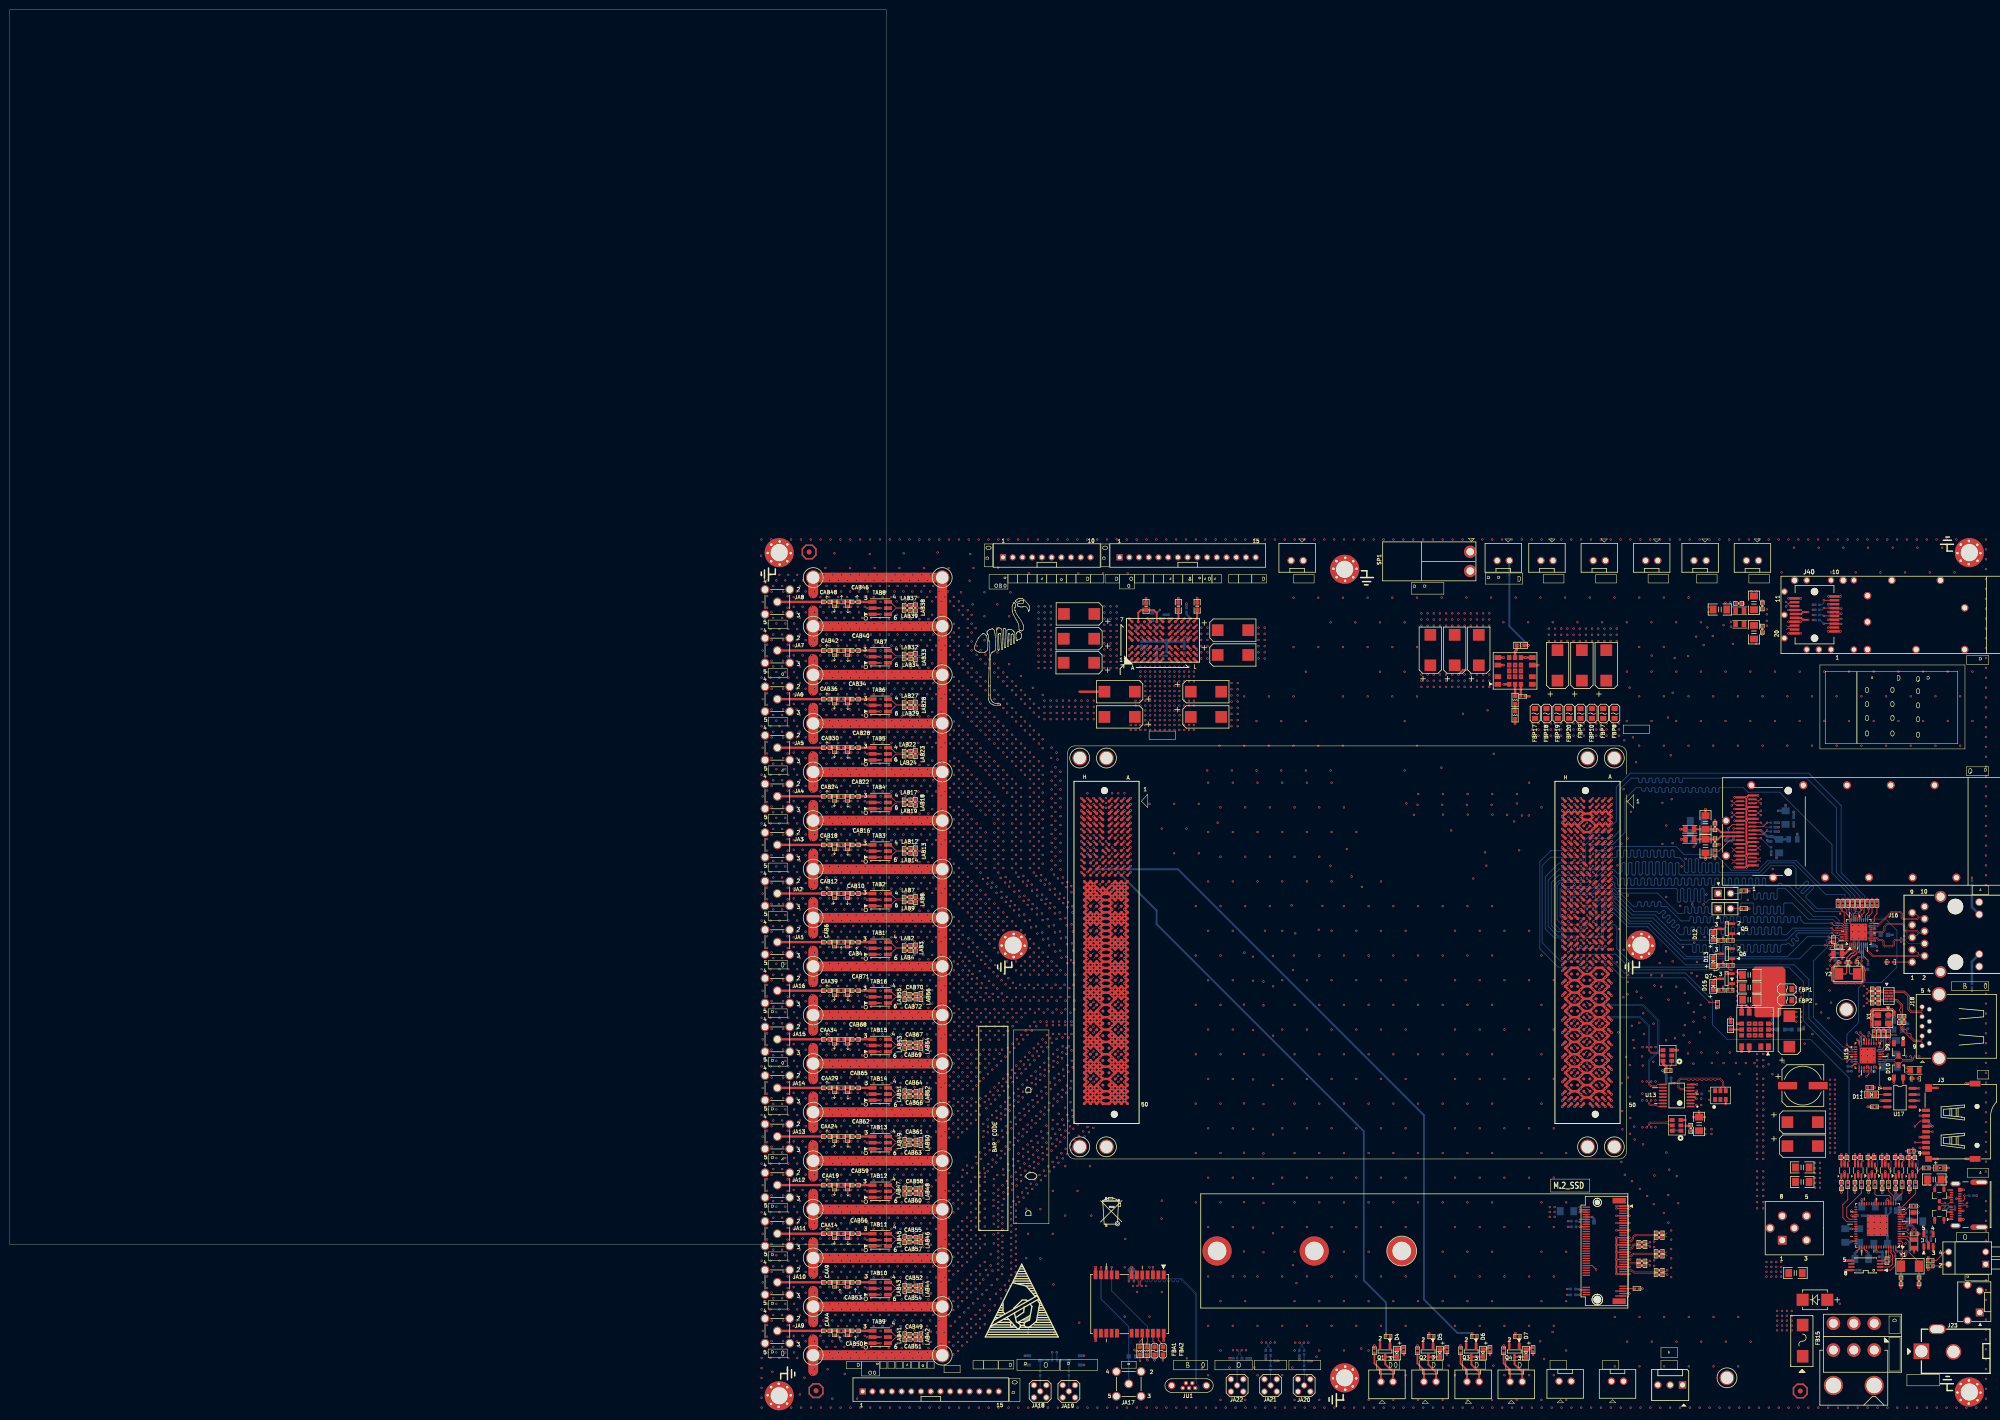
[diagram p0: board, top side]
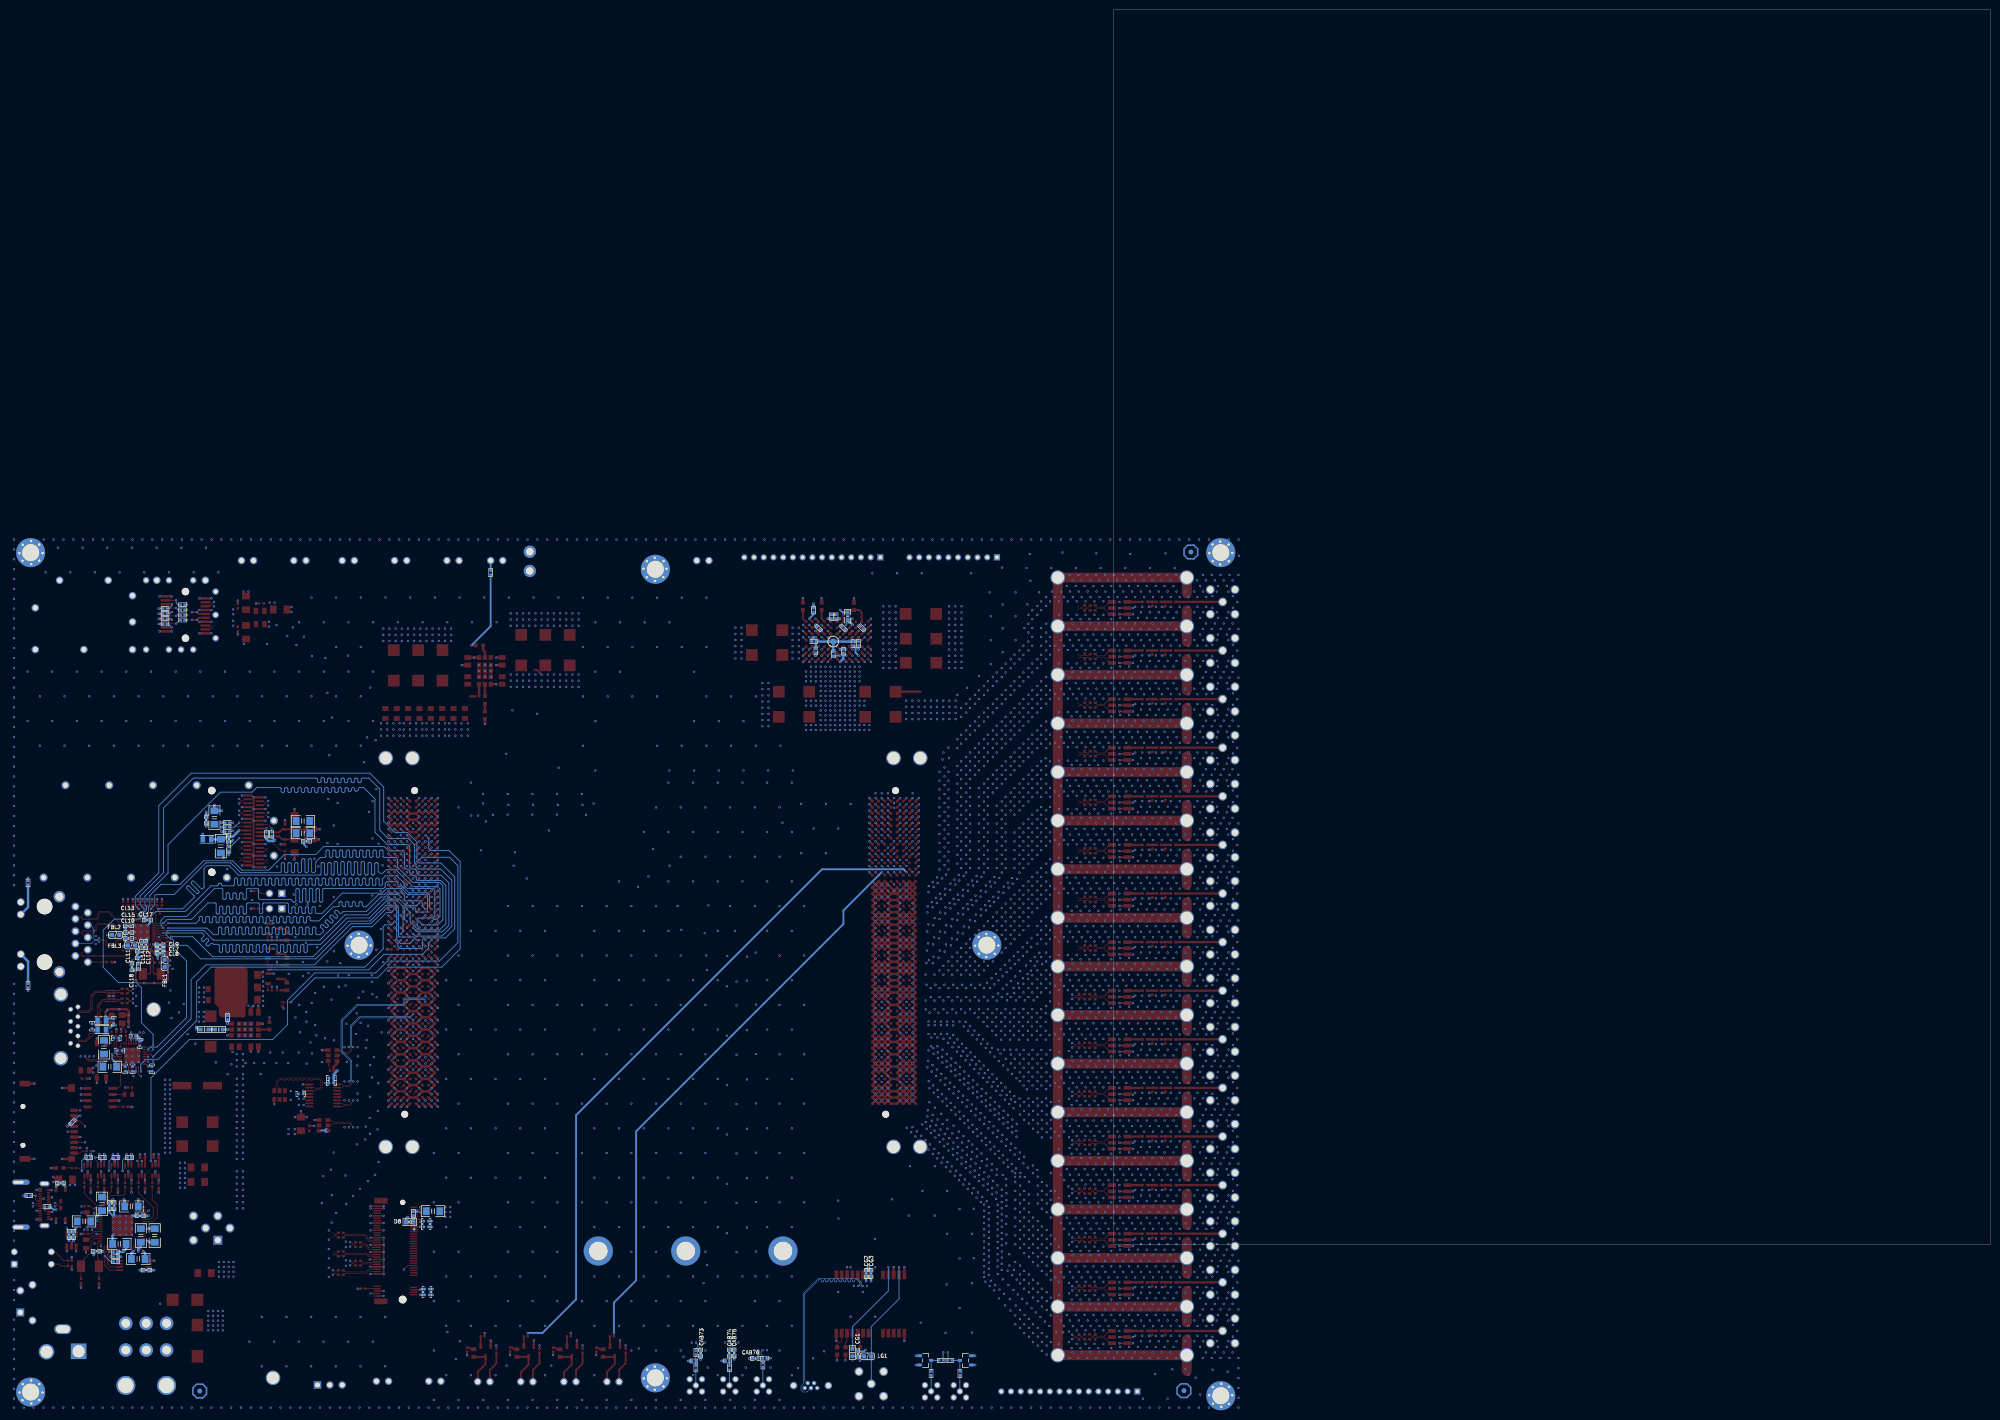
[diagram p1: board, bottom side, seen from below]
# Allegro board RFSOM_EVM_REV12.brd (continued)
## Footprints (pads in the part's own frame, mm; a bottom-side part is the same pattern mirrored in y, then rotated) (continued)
QFN40
  round 0.5 smd: (-3.8,3.8) (3.8,-3.8)
  oval 0.203x0.762 smd: 1(-1.8,-2.46) 2(-1.4,-2.46) 3(-1,-2.46) 4(-0.6,-2.46) 5(-0.2,-2.46) 6(0.2,-2.46) 7(0.6,-2.46) 8(1,-2.46) 9(1.4,-2.46) 10(1.8,-2.46) 21(1.8,2.46) 22(1.4,2.46) 23(1,2.46) 24(0.6,2.46) 25(0.2,2.46) 26(-0.2,2.46) 27(-0.6,2.46) 28(-1,2.46) 29(-1.4,2.46) 30(-1.8,2.46)
  oval 0.762x0.203 smd: 11(2.46,-1.8) 12(2.46,-1.4) 13(2.46,-1) 14(2.46,-0.6) 15(2.46,-0.2) 16(2.46,0.2) 17(2.46,0.6) 18(2.46,1) 19(2.46,1.4) 20(2.46,1.8) 31(-2.46,1.8) 32(-2.46,1.4) 33(-2.46,1) 34(-2.46,0.6) 35(-2.46,0.2) 36(-2.46,-0.2) 37(-2.46,-0.6) 38(-2.46,-1) 39(-2.46,-1.4) 40(-2.46,-1.8)
  rect 3.5x3.5 smd: 41(0,0)
QFN64
  oval 0.254x0.711 smd: 1(-3.749,-4.45) 2(-3.251,-4.45) 3(-2.751,-4.45) 4(-2.25,-4.45) 5(-1.75,-4.45) 6(-1.25,-4.45) 7(-0.749,-4.45) 8(-0.249,-4.45) 9(0.249,-4.45) 10(0.749,-4.45) 11(1.25,-4.45) 12(1.75,-4.45) 13(2.25,-4.45) 14(2.751,-4.45) 15(3.251,-4.45) 16(3.749,-4.45) 33(3.749,4.45) 34(3.251,4.45) 35(2.751,4.45) 36(2.25,4.45) 37(1.75,4.45) 38(1.25,4.45) 39(0.749,4.45) 40(0.249,4.45) 41(-0.249,4.45) 42(-0.749,4.45) 43(-1.25,4.45) 44(-1.75,4.45) 45(-2.25,4.45) 46(-2.751,4.45) 47(-3.251,4.45) 48(-3.749,4.45)
  oval 0.711x0.254 smd: 17(4.45,-3.749) 18(4.45,-3.251) 19(4.45,-2.751) 20(4.45,-2.25) 21(4.45,-1.75) 22(4.45,-1.25) 23(4.45,-0.749) 24(4.45,-0.249) 25(4.45,0.249) 26(4.45,0.749) 27(4.45,1.25) 28(4.45,1.75) 29(4.45,2.25) 30(4.45,2.751) 31(4.45,3.251) 32(4.45,3.749) 49(-4.45,3.749) 50(-4.45,3.251) 51(-4.45,2.751) 52(-4.45,2.25) 53(-4.45,1.75) 54(-4.45,1.25) 55(-4.45,0.749) 56(-4.45,0.249) 57(-4.45,-0.249) 58(-4.45,-0.749) 59(-4.45,-1.25) 60(-4.45,-1.75) 61(-4.45,-2.25) 62(-4.45,-2.751) 63(-4.45,-3.251) 64(-4.45,-3.749)
  rect 4.42x4.42 smd: 65(0,0)
QSFP28_CON
  round 1.549 hole 1.549 unplated: (-8.4,0) (8.4,0)
  oval 0.399x1.801 smd: 1(-7,7.37) 2(-6.2,7.37) 3(-5.4,7.37) 4(-4.6,7.37) 5(-3.8,7.37) 6(-3,7.37) 7(-2.2,7.37) 8(-1.4,7.37) 9(-0.6,7.37) 10(0.2,7.37) 11(1,7.37) 12(1.8,7.37) 13(2.6,7.37) 14(3.4,7.37) 15(4.2,7.37) 16(5,7.37) 17(5.8,7.37) 18(6.6,7.37) 19(7.4,7.37) 20(7,9.88) 21(6.2,9.88) 22(5.4,9.88) 23(4.6,9.88) 24(3.8,9.88) 25(3,9.88) 26(2.2,9.88) 27(1.4,9.88) 28(0.6,9.88) 29(-0.2,9.88) 30(-1,9.88) 31(-1.8,9.88) 32(-2.6,9.88) 33(-3.4,9.88) 34(-4.2,9.88) 35(-5,9.88) 36(-5.8,9.88) 37(-6.6,9.88) 38(-7.4,9.88)
R0402
  rect 0.5x0.5 smd: 1(-0.399,0) 2(0.399,0)
R0603
  rect 0.762x0.813 smd: 1(-0.762,0) 2(0.762,0)
SC70_6
  rect 1.016x0.406 smd: 1(-1.1,0.658) 2(-1.1,0) 3(-1.1,-0.658) 4(1.1,-0.658) 5(1.1,0) 6(1.1,0.658)
SFP_MODULE
  round 1.549 hole 1.524 unplated: (4.1,1.402) (4.1,-8.199)
  rect 2.007x0.508 smd: 1(0,0) 2(0,-0.8) 3(0,-1.6) 4(0,-2.4) 5(0,-3.2) 6(0,-4) 7(0,-4.8) 8(0,-5.6) 9(0,-6.4) 10(0,-7.2) 11(8.202,-6.799) 12(8.202,-5.999) 13(8.202,-5.199) 14(8.202,-4.399) 15(8.202,-3.599) 16(8.202,-2.799) 17(8.202,-1.999) 18(8.202,-1.199) 19(8.202,-0.399) 20(8.202,0.401)
  round 1.346 hole 0.838: 21(3.2,3.731) A1(-4,3.731) A2(0.701,3.731) A3(5.7,3.731) A4(10.3,1.402) A5(10.3,-3.399) A6(10.3,-8.199) A8(5.7,-10.518) A9(0.701,-10.518) A10(-4,-10.518)
  round 1.549 hole 1.041: 22(-6.8,3.731) 23(-16.8,3.731) 24(-26.8,3.731) 25(-26.8,-4.849) 26(-21.798,-10.518) 27(-11.798,-10.518) 28(-1.798,-10.518) 29(8.202,-10.518) 30(-6.8,-7.348) 31(-6.8,-1.948)
SIP2
  rect 1.524x1.524 hole 1.016: 1(-0.004,-0.008)
  round 1.524 hole 1.016: 2(2.536,-0.008)
SIP2_HV
  round 2.54 hole 1.524: 1(0.013,0.01) 2(3.973,0.01)
SIP10_2-0MM_S
  rect 1.27x1.27 hole 0.762: 1(-9,0)
  round 1.27 hole 0.762: 2(-7,0) 3(-5,0) 4(-3,0) 5(-1,0) 6(1,0) 7(3,0) 8(5,0) 9(7,0) 10(9,0)
SIP15_2-0MM_S
  rect 1.27x1.27 hole 0.762: 1(-14,0)
  round 1.27 hole 0.762: 2(-11.999,0) 3(-10,0) 4(-8.001,0) 5(-5.999,0) 6(-4,0) 7(-1.999,0) 8(0,0) 9(1.999,0) 10(4,0) 11(5.999,0) 12(8.001,0) 13(10,0) 14(11.999,0) 15(14,0)
SMB
  rect 2.489x2.489 smd: 1(-2.54,0) 2(2.54,0)
SMB_RF
  round 1.803 hole 1.321: 1(0,0) 2(-2.54,2.54) 3(2.54,2.54) 4(-2.54,-2.54) 5(2.54,-2.54)
SO-G3
  rect 0.838x1.245 smd: 1(0.95,1.275) 2(-0.95,1.275) 3(0,-1.275)
SO_8
  rect 1.803x0.61 smd: 1(-2.593,1.905)
  oval 1.803x0.61 smd: 2(-2.593,0.635) 3(-2.593,-0.635) 4(-2.593,-1.905) 5(2.593,-1.905) 6(2.593,-0.635) 7(2.593,0.635) 8(2.593,1.905)
SOT23
  rect 0.899x0.599 smd: 1(-1.151,0.95) 2(-1.151,-0.95) 3(1.151,0)
SOT_23
  rect 1.194x0.61 smd: 1(0,1.025)
  rect 1.194x0.508 smd: 2(0,-1.025) 3(2.225,0.05)
SOT_25
  rect 0.635x1.27 smd: 1(-0.95,-1.25) 2(0,-1.25) 3(0.95,-1.25) 4(0.95,1.25) 5(-0.95,1.25)
SWP1
  round 1.626 hole 1.118: (-1.66,2.523) (5.669,2.523) 2(4.483,0.01)
  rect 1.626x1.626 hole 1.118: 1(-0.01,0.01)
TCM1-63AX_
  rect 0.762x1.651 smd: 1(-1.27,1.59) 2(0,1.59) 3(1.27,1.59) 4(1.27,-1.59) 5(0,-1.59) 6(-1.27,-1.59)
TF01A
  round 1.016 hole 1.016 unplated: (-7.201,-10.5) (0.8,-10.5)
  rect 0.711x1.6 smd: 1(0,0) 2(-1.1,0) 3(-2.2,0) 4(-3.299,0) 5(-4.399,0) 6(-5.499,0) 7(-6.599,0) 8(-7.701,0) 9(-8.801,0)
  rect 1.194x1.397 smd: 10(-10,-0.5)
  rect 1.6x1.397 smd: 11(4.6,-0.5)
  rect 1.194x2.21 smd: 12(-10,-10.099) 13(5.499,-10.099)
TSSOP8
  rect 0.356x1.321 smd: 1(-0.975,-2.949) 2(-0.325,-2.949) 3(0.325,-2.949) 4(0.975,-2.949) 5(0.975,2.949) 6(0.325,2.949) 7(-0.325,2.949) 8(-0.975,2.949)
TSSOP16
  oval 1.702x0.356 smd: 1(-2.85,2.275) 2(-2.85,1.625) 3(-2.85,0.975) 4(-2.85,0.325) 5(-2.85,-0.325) 6(-2.85,-0.975) 7(-2.85,-1.625) 8(-2.85,-2.275) 9(2.85,-2.275) 10(2.85,-1.625) 11(2.85,-0.975) 12(2.85,-0.325) 13(2.85,0.325) 14(2.85,0.975) 15(2.85,1.625) 16(2.85,2.275)
TVS_0524J
  rect 0.305x0.686 smd: 1(-1.118,-0.442) 2(-0.61,-0.442) 3(0.61,-0.442) 4(1.118,-0.442) 5(1.118,0.442) 6(0.61,0.442) 7(-0.61,0.442) 8(-1.118,0.442)
  rect 0.508x0.889 smd: 9(0,0.432) 10(0,-0.432)
U95-T1N1-101A
  round 1.651 hole 1.041: 1(1.1,-3.1) 2(-3.4,-12.79) 3(-10.6,-12.79) 4(-17.9,-7.6) 5(-17.9,3.1) 6(-17.9,12.1) 7(-17.9,21.1) 8(-17.9,30.1) 9(1.1,34.6) 10(1.1,25.6) 11(1.1,16.6) 12(1.1,7.6)
unnamed#2
  round 1.016 smd: 1(0,0)
USB3-A
  round 1.016 hole 0.711: 1(-3.5,2) 2(-1,2) 3(1,2) 4(3.5,2) 5(4,3.5) 6(2,3.5) 7(0,3.5) 8(-2,3.5) 9(-4,3.5)
  round 2.997 hole 2.311: 10(-6.57,0) 11(6.57,0)
USB-MICRO-VER
  round 0.914 hole 0.432: 1(-1.3,0.5) 2(-0.665,-0.5) 3(0,0.5) 4(0.635,-0.5) 5(1.3,0.5)
  round 1.524 hole 1.016: 6(-3.575,0) 7(3.575,0)
XTALSMD_3225
  oval 1.397x1.194 smd: 1(-1.1,-0.85)
  rect 1.397x1.194 smd: 2(1.1,-0.85) 3(1.1,0.85) 4(-1.1,0.85)
XTALSMD_3225_DP
  rect 0.813x1.016 smd: 1(-1.1,-0.9) 2(0,-0.9) 3(1.1,-0.9) 4(1.1,0.9) 5(0,0.9) 6(-1.1,0.9)

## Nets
+1.8V: C2.1 C4.1 C6.1 C8.1 FBP1.1 FBP2.1 R7.1 R8.1 R9.1 R10.1 R64.1 R99.2 U3.6(VCCB) U4.6(VCCB) U5.6(VCCB) U6.6(VCCB) U15.28 U15.30
+3.3V: C13.1 C18.1 C31.1 C32.1 C39.1 C40.1 C41.1 C42.1 C43.1 C44.1 C78.1 C79.1 C80.1 C81.1 C84.1 C85.1 C86.1 C98.1 C101.1 C102.1 C103.1 C104.1 C288.1 C289.1 CG2.1 CG3.1 D14.2 D16.2 FB3.1 FB4.1 FB5.1 FB6.1 FB7.1 FBA1.2 FBA2.2 FBL2.1 FBL3.1 FBP7.1 FBP8.1 J3.4 J11.10 J17.2 J17.4 J17.12 J17.14 J17.16 J17.18 J17.70 J17.72 J17.74 R1.1 R2.1 R22.1 R23.1 R25.1 R26.1 R28.1 R29.1 R31.1 R32.1 R34.2 R35.2 R36.2 R37.2 R38.2 R39.2 R62.1 R63.1 R66.1 R72.2 R74.1 R78.1 R80.1 R104.2 R184.2 R186.2 R187.2 R188.2 R189.2 R190.2 R191.2 R208.2 RP129.1 U7.6(VCCB) U8.6(VCCB) U13.1 U13.2 U13.3 U13.4(VCC) U13.8 U15.8 U15.11 U15.14 U15.32 UG1.7 X1.4(VCC) XS1.1 XS1.6(VCC) XS2.1 XS2.6(VCC) Y7.6(VDD)
AVDD33: CL15.2 FBL2.2 U12.14
AVDDL: CL10.2 CL11.2 CL13.2 FBL1.2 U12.6 U12.11 U12.17
DGND: C1.2 C2.2 C3.2 C4.2 C5.2 C6.2 C7.2 C8.2 C9.2 C10.2 C11.2 C12.2 C13.2 C14.2 C15.2 C16.2 C17.2 C18.2 C19.2 C20.2 C21.2 C22.2 C23.2 C24.2 C25.2 C26.2 C27.2 C28.2 C29.2 C30.2 C31.2 C32.2 C33.2 C34.2 C35.2 C36.2 C37.2 C38.2 C39.2 C40.2 C41.2 C42.2 C43.2 C44.2 C45.2 C46.2 C47.2 C48.2 C53.2 C57.1 C58.1 C78.2 C79.2 C80.2 C81.2 C84.2 C85.2 C86.2 C90.2 C91.2 C93.2 C94.2 C98.2 C101.2 C102.2 C103.2 C104.2 C105.2 C106.2 C107.2 C109.2 C110.2 C288.2 C289.2 C290.2 CAB73.1 CAB75.1 CAB76.1 CG1.2 CG2.2 CG3.2 CIN1.2 CIN2.2 CIN3.2 CIN4.2 CIN5.2 CIN6.2 CIN7.2 CIN8.2 CIN9.2 CIN10.2 CIN11.2 CL7.1 CL8.1 CL9.1 CL10.1 CL11.1 CL12.1 CL13.1 CL14.1 CL15.1 CL17.1 CL18.1 COUT1.2 COUT2.2 COUT3.2 COUT4.2 COUT5.2 COUT9.2 COUT10.2 COUT11.2 COUT12.2 COUT13.2 COUT14.2 D1.1 D2.1 D3.2(K) D9.1 D10.1 D14.1 D16.1 EC1.2 FB13.1 FB14.1 H7.1 H8.1 H9.1 H10.1 H11.1 H12.1 H13.1 H14.1 H15.1 H16.1 H17.1 H18.1 H19.1 H20.1 H21.1 H22.1 H23.1 H24.1 H25.1 H26.1 H27.1 H28.1 H29.1 H30.1 H31.1 H32.1 H33.1 H34.1 H35.1 H36.1 H37.1 H38.1 H39.1 H40.1 H41.1 H41.2 H41.3 H41.4 H41.5(GND9) H41.6 H41.7 H41.8 H41.9 H42.1 H42.2 H42.3 H42.4 H42.5(GND9) H42.6 H42.7 H42.8 H42.9 H43.1 H43.2 H43.3 H43.4 H43.5(GND9) H43.6 H43.7 H43.8 H43.9 H44.1 H44.2 H44.3 H44.4 H44.5(GND9) H44.6 H44.7 H44.8 H44.9 H45.1 H45.2 H45.3 H45.4 H45.5(GND9) H45.6 H45.7 H45.8 H45.9 H46.1 H46.2 H46.3 H46.4 H46.5(GND9) H46.6 H46.7 H46.8 H46.9 H47.1 H47.2 H47.3 H47.4 H47.5(GND9) H47.6 H47.7 H47.8 H47.9 H48.1 H48.2 H48.3 H48.4 H48.5(GND9) H48.6 H48.7 H48.8 H48.9 J1.A1 J1.A2 J1.A3 J1.A4 J1.A5 J1.A6 J1.A7 J1.A8 J1.A9 J1.A10 J1.A11 J1.A12 J1.A13 J1.A14 J1.A15 J1.A16 J1.A17 J1.A18 J1.A19 J1.A20 J1.A21 J1.A22 J1.A23 J1.A24 J1.A25 J1.A26 J1.A27 J1.A28 J1.A29 J1.A30 J1.A31 J1.A32 J1.A33 J1.A34 J1.A35 J1.A36 J1.A37 J1.A38 J1.A39 J1.A40 J1.A41 J1.A42 J1.A43 J1.A44 J1.A45 J1.A46 J1.A47 J1.A48 J1.A49 J1.A50 J1.B3 J1.B4 J1.B5 J1.B6 J1.B8 J1.B10 J1.B12 J1.B14 J1.B15 J1.B16 J1.B17 J1.B19 J1.B20 J1.B21 J1.B23 J1.B24 J1.B25 J1.B27 J1.B28 J1.B29 J1.B31 J1.B32 J1.B33 J1.B35 J1.B36 J1.B37 J1.B39 J1.B40 J1.B41 J1.B43 J1.B44 J1.B45 J1.B47 J1.B48 J1.B49 J1.B50 J1.C3 J1.C4 J1.C5 J1.C6 J1.C8 J1.C10 J1.C12 J1.C14 J1.C15 J1.C16 J1.C17 J1.C19 J1.C20 J1.C21 J1.C23 J1.C24 J1.C25 J1.C27 J1.C28 J1.C29 J1.C31 J1.C32 J1.C33 J1.C35 J1.C36 J1.C37 J1.C39 J1.C40 J1.C41 J1.C43 J1.C44 J1.C45 J1.C47 J1.C48 J1.C49 J1.C50 J1.D3 J1.D4 J1.D5 J1.D6 J1.D7 J1.D9 J1.D11 J1.D13 J1.D15 J1.D16 J1.D17 J1.D18 J1.D19 J1.D20 J1.D21 J1.D22 J1.D23 J1.D24 J1.D25 J1.D26 J1.D27 J1.D28 J1.D29 J1.D30 J1.D31 J1.D32 J1.D34 J1.D35 J1.D36 J1.D38 J1.D39 J1.D40 J1.D42 J1.D43 J1.D44 J1.D46 J1.D47 J1.D48 J1.D49 J1.D50 J1.E3 J1.E4 J1.E5 J1.E6 J1.E7 J1.E9 J1.E11 J1.E13 J1.E15 J1.E16 J1.E17 J1.E18 J1.E19 J1.E20 J1.E21 J1.E22 J1.E23 J1.E24 J1.E25 J1.E26 J1.E27 J1.E28 J1.E29 J1.E30 J1.E31 J1.E32 J1.E33 J1.E34 J1.E36 J1.E37 J1.E38 J1.E40 J1.E41 J1.E42 J1.E44 J1.E45 J1.E46 J1.E48 J1.E49 J1.E50 J1.F3 J1.F4 J1.F5 J1.F6 J1.F8 J1.F10 J1.F12 J1.F14 J1.F15 J1.F16 J1.F17 J1.F19 J1.F20 J1.F21 J1.F23 J1.F24 J1.F25 J1.F27 J1.F28 J1.F29 J1.F31 J1.F32 J1.F33 J1.F35 J1.F36 J1.F37 J1.F39 J1.F40 J1.F41 J1.F43 J1.F44 J1.F45 J1.F47 J1.F48 J1.F49 J1.F50 J1.G3 J1.G4 J1.G5 J1.G6 J1.G8 J1.G10 J1.G12 J1.G14 J1.G15 J1.G16 J1.G17 J1.G19 J1.G20 J1.G21 J1.G23 J1.G24 J1.G25 J1.G27 J1.G28 J1.G29 J1.G31 J1.G32 J1.G33 J1.G35 J1.G36 J1.G37 J1.G39 J1.G40 J1.G41 J1.G43 J1.G44 J1.G45 J1.G47 J1.G48 J1.G49 J1.G50 J1.H1 J1.H2 J1.H3 J1.H4 J1.H5 J1.H6 J1.H7 J1.H8 J1.H9 J1.H10 J1.H11 J1.H12 J1.H13 J1.H14 J1.H15 J1.H16 J1.H17 J1.H18 J1.H19 J1.H20 J1.H21 J1.H22 J1.H23 J1.H24 J1.H25 J1.H26 J1.H27 J1.H28 J1.H29 J1.H30 J1.H31 J1.H32 J1.H33 J1.H34 J1.H35 J1.H36 J1.H37 J1.H38 J1.H39 J1.H40 J1.H41 J1.H42 J1.H43 J1.H44 J1.H45 J1.H46 J1.H47 J1.H48 J1.H49 J1.H50 J2.A1 J2.A2 J2.A3 J2.A4 J2.A5 J2.A6 J2.A7 J2.A8 J2.A9 J2.A10 J2.A11 J2.A12 J2.A13 J2.A14 J2.A15 J2.A16 J2.A17 J2.A18 J2.A19 J2.A20 J2.A21 J2.A22 J2.A23 J2.A24 J2.A25 J2.A26 J2.A27 J2.A28 J2.A29 J2.A30 J2.A31 J2.A32 J2.A33 J2.A34 J2.A35 J2.A36 J2.A37 J2.A38 J2.A39 J2.A40 J2.A41 J2.A42 J2.A43 J2.A44 J2.A45 J2.A46 J2.A47 J2.A48 J2.A49 J2.A50 J2.B3 J2.B5 J2.B6 J2.B8 J2.B10 J2.B12 J2.B14 J2.B16 J2.B18 J2.B20 J2.B22 J2.B24 J2.B26 J2.B28 J2.B30 J2.B32 J2.B34 J2.B36 J2.B38 J2.B40 J2.B42 J2.B44 J2.B46 J2.B48 J2.B49 J2.B50 J2.C3 J2.C5 J2.C6 J2.C8 J2.C10 J2.C12 J2.C14 J2.C16 J2.C18 J2.C20 J2.C22 J2.C24 J2.C26 J2.C28 J2.C30 J2.C32 J2.C34 J2.C36 J2.C38 J2.C40 J2.C42 J2.C44 J2.C46 J2.C48 J2.C49 J2.C50 J2.D3 J2.D4 J2.D6 J2.D7 J2.D9 J2.D11 J2.D13 J2.D15 J2.D17 J2.D19 J2.D21 J2.D23 J2.D25 J2.D27 J2.D29 J2.D31 J2.D33 J2.D35 J2.D37 J2.D39 J2.D41 J2.D43 J2.D45 J2.D47 J2.D49 J2.D50 J2.E3 J2.E4 J2.E6 J2.E7 J2.E9 J2.E11 J2.E13 J2.E15 J2.E17 J2.E19 J2.E21 J2.E23 J2.E25 J2.E27 J2.E29 J2.E31 J2.E33 J2.E35 J2.E37 J2.E39 J2.E41 J2.E43 J2.E45 J2.E47 J2.E49 J2.E50 J2.F3 J2.F5 J2.F6 J2.F8 J2.F10 J2.F12 J2.F14 J2.F16 J2.F18 J2.F20 J2.F22 J2.F24 J2.F26 J2.F28 J2.F30 J2.F32 J2.F34 J2.F36 J2.F38 J2.F40 J2.F42 J2.F44 J2.F46 J2.F48 J2.F49 J2.F50 J2.G3 J2.G5 J2.G6 J2.G8 J2.G10 J2.G12 J2.G14 J2.G16 J2.G18 J2.G20 J2.G22 J2.G24 J2.G26 J2.G28 J2.G30 J2.G32 J2.G34 J2.G36 J2.G38 J2.G40 J2.G42 J2.G44 J2.G46 J2.G48 J2.G49 J2.G50 J2.H1 J2.H2 J2.H3 J2.H4 J2.H5 J2.H6 J2.H7 J2.H8 J2.H9 J2.H10 J2.H11 J2.H12 J2.H13 J2.H14 J2.H15 J2.H16 J2.H17 J2.H18 J2.H19 J2.H20 J2.H21 J2.H22 J2.H23 J2.H24 J2.H25 J2.H26 J2.H27 J2.H28 J2.H29 J2.H30 J2.H31 J2.H32 J2.H33 J2.H34 J2.H35 J2.H36 J2.H37 J2.H38 J2.H39 J2.H40 J2.H41 J2.H42 J2.H43 J2.H44 J2.H45 J2.H46 J2.H47 J2.H48 J2.H49 J2.H50 J3.6(VSS) J3.10 J3.11 J3.12 J3.13 J4.A1 J4.A12 J4.B1 J4.B12 J4.SH1 J4.SH2 J4.SH3 J4.SH4 J9.9 J10.1 J10.15 J11.1 J11.15 J12.1 J12.4 J12.7 J12.13 J12.16 J12.19 J12.20 J12.23 J12.26 J12.32 J12.35 J12.38 J13.1 J13.2 J13.3 J13.4 J13.5 J13.6 J13.7 J13.8 J13.9(P9) J13.10 J13.11 J13.12 J16.10 J16.15 J16.16 J17.1 J17.3 J17.9 J17.15 J17.21 J17.27 J17.33 J17.39 J17.45 J17.51 J17.57 J17.71 J17.73 J17.75 J18.7 J19.2 J20.2 J21.2 J22.2 J24.2 J25.2 J27.2 J28.2 J32.1 J40.1 J40.10 J40.11 J40.14 J40.17 J40.20(VEET_20) J40.21 J40.22 J40.23 J40.24 J40.25 J40.26 J40.27 J40.28 J40.29 J40.30 J40.31 JA1.2 JA1.3 JA1.4 JA1.5(SHIELD4) JA2.2 JA2.3 JA2.4 JA2.5(SHIELD4) JA3.2 JA3.3 JA3.4 JA3.5(SHIELD4) JA4.2 JA4.3 JA4.4 JA4.5(SHIELD4) JA5.2 JA5.3 JA5.4 JA5.5(SHIELD4) JA6.2 JA6.3 JA6.4 JA6.5(SHIELD4) JA7.2 JA7.3 JA7.4 JA7.5(SHIELD4) JA8.2 JA8.3 JA8.4 JA8.5(SHIELD4) JA9.2 JA9.3 JA9.4 JA9.5(SHIELD4) JA10.2 JA10.3 JA10.4 JA10.5(SHIELD4) JA11.2 JA11.3 JA11.4 JA11.5(SHIELD4) JA12.2 JA12.3 JA12.4 JA12.5(SHIELD4) JA13.2 JA13.3 JA13.4 JA13.5(SHIELD4) JA14.2 JA14.3 JA14.4 JA14.5(SHIELD4) JA15.2 JA15.3 JA15.4 JA15.5(SHIELD4) JA16.2 JA16.3 JA16.4 JA16.5(SHIELD4) JA17.2 JA17.3 JA17.4 JA17.5(SHIELD4) JA18.2 JA18.3 JA18.4 JA18.5(SHIELD4) JA19.2 JA19.3 JA19.4 JA19.5(SHIELD4) JA20.2 JA20.3 JA20.4 JA20.5(SHIELD4) JA21.2 JA21.3 JA21.4 JA21.5(SHIELD4) JA22.2 JA22.3 JA22.4 JA22.5(SHIELD4) JFA6.2 JU1.5 JU1.6 JU1.7 P3.1 P4.1 P5.1 P7.1 P8.1 P9.1 P11.1 P12.1 P13.1 P14.1 Q1.2(E) Q2.2(E) Q3.2(E) Q4.2(E) Q5.2(E) Q6.2(E) Q7.2(E) R4.1 R13.2 R15.2 R40.2 R48.1 R49.2 R50.2 R68.1 R69.1 R73.2 R84.1 R85.1 R86.1 R87.1 R90.2 R92.2 R94.2 R96.2 R101.2 R185.2 RAA3.2 RAA4.2 RAA7.2 RAA8.2 RAA11.2 RAA12.2 RAA15.2 RAA16.2 RAA19.2 RAA20.2 RAA23.2 RAA24.2 RAA27.2 RAA28.2 RAA31.2 RAA32.2 RAB3.2 RAB4.2 RAB7.2 RAB8.2 RAB11.2 RAB12.2 RAB15.2 RAB16.2 RAB19.2 RAB20.2 RAB23.2 RAB24.2 RAB27.2 RAB28.2 RAB31.2 RAB32.2 RL16.2 RL17.2 RL18.2 RL19.2 RL20.2 RP2.2 SWC4.2 TAB1.1 TAB1.2 TAB1.5 TAB2.1 TAB2.2 TAB2.5 TAB3.1 TAB3.2 TAB3.5 TAB4.1 TAB4.2 TAB4.5 TAB5.1 TAB5.2 TAB5.5 TAB6.1 TAB6.2 TAB6.5 TAB7.1 TAB7.2 TAB7.5 TAB8.1 TAB8.2 TAB8.5 TAB9.1 TAB9.2 TAB9.5 TAB10.1 TAB10.2 TAB10.5 TAB11.1 TAB11.2 TAB11.5 TAB12.1 TAB12.2 TAB12.5 TAB13.1 TAB13.2 TAB13.5 TAB14.1 TAB14.2 TAB14.5 TAB15.1 TAB15.2 TAB15.5 TAB16.1 TAB16.2 TAB16.5 U2.1 U2.5 U2.10 U2.11 U2.13 U2.15 U2.25 U2.35 U2.47 U2.51 U2.65 U3.2 U4.2 U5.2 U6.2 U6.5 U7.2 U8.2 U8.5 U9.2 U10.5 U12.41 U13.5 U15.33 U17.3 U18.9 U18.10 U19.A4 U19.A5 U19.B1 U19.B2 U19.C5 U19.D3 U19.D4 U19.D5 U19.E1 U19.E2 U19.F5 U19.F7 U19.G3 U19.G4 U19.G5 U19.H1 U19.H2 U19.J5 U19.K3 U19.K4 U19.L1 U19.L2 U20.3 U20.8 U20.9 U20.10 U20.13 U20.14 U20.15 U20.16 U20.17 U20.18 U20.19 U20.20 U20.21 U20.22 U20.23 U21.3 U21.8 U21.9 U21.10 U21.13 U21.14 U21.15 U21.16 U21.17 U21.18 U21.19 U21.20 U21.21 U21.22 U21.23 U22.5 U22.6 U22.7 UG1.10 UG1.12 UG1.13 UG1.24 X1.2 XS1.3 XS2.3 Y7.3
DVDDL: CL7.2 CL8.2 CL9.2 FB9.1 FBL1.1 U12.38
VBUS: C15.1 C16.1 D1.2 D2.2 J4.A4 J4.A9 J4.B4 J4.B9(VBUS4) U9.1 U9.3
VCC_1V8_FT: C25.1 C26.1 C27.1 C28.1 U2.12 U2.37 U2.49(VREGOUT) U2.64
VCC_3V3_FT: C1.1 C3.1 C5.1 C7.1 C9.1 C10.1 C12.1 C17.1 C19.1 C20.1 C21.1 C22.1 C23.1 C24.1 C30.1 FB1.1 FB2.1 R5.2 R17.2 R19.2 R20.2 U2.20 U2.31 U2.42 U2.50 U2.56 U3.1 U3.5 U4.1 U4.5 U5.1 U5.5 U6.1 U7.1 U7.5 U8.1 U9.5(VOUT) U10.8(VCC)
VCC_5V: C290.1 COUT1.1 COUT2.1 COUT3.1 COUT4.1 J1.B1 J1.B2 J1.C1 J1.C2 J1.D1 J1.D2 J1.E1 J1.E2 J1.F1 J1.F2 J1.G1 J1.G2(VCC3D) J2.F1 J2.G1 J2.G2 J10.13 J11.13 RP12.1 U15.21 U17.7 U19.A1 U19.A2 U19.A3 U19.C1 U19.D1 U19.D2 U19.F1 U19.G1 U19.G2 U19.J1 U19.K1 U19.K2(VOUT4C)
VCC_12V: C109.1 C110.1 CIN1.1 CIN2.1 CIN3.1 CIN4.1 CIN5.1 CIN6.1 CIN7.1 CIN8.1 CIN9.1 CIN10.1 CIN11.1 EC1.1 J9.10 J10.14 J11.14 J19.1 J20.1 J21.1 J22.1 J24.1 J25.1 J27.1 J28.1 J32.2 RP3.1 RP4.1 RP5.1 RP6.1 U19.B3 U19.B4 U19.B5 U19.E3 U19.E4 U19.E5 U19.H3 U19.H4 U19.H5 U19.L3 U19.L4 U19.L5 U20.1 U20.2 U21.1 U21.2 U22.8
VCCO_89: FBP9.1 FBP10.1 J2.B2 J2.C1 J2.C2
VCCO_501: FBP17.1 FBP18.1 J2.E1 J2.E2 J2.F2
VCCO_502: FBP19.1 FBP20.1 J2.B1 J2.D1 J2.D2
VDD33: CL12.2 CL14.2 FBL3.2 U12.3
VDDH: CL17.2 CL18.2 RL10.2 RL11.2 RL14.2 RL15.2 RL21.2 U12.8 U12.27
BANK128_MGT_CLK1_N: J2.E40 XS1.5
BANK128_MGT_CLK1_P: J2.D40 XS1.4
BANK128_MGT_RX0_N: J2.C39 J12.18
BANK128_MGT_RX0_P: J2.B39 J12.17
BANK128_MGT_RX1_N: J2.G37 J12.21
BANK128_MGT_RX1_P: J2.F37 J12.22
BANK128_MGT_RX2_N: J2.E38 J12.15
BANK128_MGT_RX2_P: J2.D38 J12.14
BANK128_MGT_RX3_N: J2.C37 J12.24
BANK128_MGT_RX3_P: J2.B37 J12.25
BANK128_MGT_TX0_N: J2.G41 J12.37
BANK128_MGT_TX0_P: J2.F41 J12.36
BANK128_MGT_TX1_N: J2.E42 J12.2
BANK128_MGT_TX1_P: J2.D42 J12.3
BANK128_MGT_TX2_N: J2.G39 J12.34
BANK128_MGT_TX2_P: J2.F39 J12.33
BANK128_MGT_TX3_N: J2.C41 J12.5
BANK128_MGT_TX3_P: J2.B41 J12.6
BANK129_MGT_RX0_N: J2.C31 J40.12
BANK129_MGT_RX0_P: J2.B31 J40.13
BANK129_MGT_TX0_N: J2.E34 J40.19
BANK129_MGT_TX0_P: J2.D34 J40.18
BANK501_PS_MIO30: J2.D8 J10.2
BANK501_PS_MIO31: J2.C15 J10.3
BANK501_PS_MIO32: J2.D10 J10.4
BANK501_PS_MIO33: J2.B15 J10.5
BANK501_PS_MIO34: J2.G7 J10.6
BANK501_PS_MIO35: J2.C11 J10.7
BANK501_PS_MIO38: J2.G9 J10.8
BANK501_PS_MIO39: J2.E10 J10.9
BANK501_PS_MIO40: J2.B11 J10.10
BANK501_PS_MIO41: J2.F9 J10.11
BANK505_MGT_CLK0_N: J2.G33 U13.9
BANK505_MGT_CLK0_P: J2.F33 U13.10
BANK505_MGT_CLK2_N: J2.E36 Y7.5
BANK505_MGT_CLK2_P: J2.D36 Y7.4
BANK505_MGT_RX0_N: C72.2 J2.E48
BANK505_MGT_RX0_P: C73.2 J2.D48
BANK505_MGT_RX1_N: C68.2 J2.C47
BANK505_MGT_RX1_P: C69.2 J2.B47
BANK505_MGT_RX2_N: C92.2 J2.G45
BANK505_MGT_RX2_P: C95.2 J2.F45
BANK505_MGT_TX0_N: C74.2 J2.C45
BANK505_MGT_TX0_P: C75.2 J2.B45
BANK505_MGT_TX1_N: C70.2 J2.E44
BANK505_MGT_TX1_P: C71.2 J2.D44
BANK505_MGT_TX2_N: C97.2 J2.G43
BANK505_MGT_TX2_P: C96.2 J2.F43
CLK_100M_N: U13.7 XS2.5
CLK_100M_P: U13.6 XS2.4
CLKIN0_N: CAB75.2 J2.G4
CLKIN0_P: CAB74.2 J2.F4
DU+: D2.3 J4.A6 J4.B6 U2.8
DU-: D1.3 J4.A7 J4.B7 U2.7
EECLK: R19.1 U2.62 U10.2
EECS: R17.1 U2.63 U10.1
EEDATA: R18.2 R20.1 U2.61 U10.3
FT223_UART0_RX: R14.1 U2.38
FT223_UART0_TX: R16.1 U2.39
GPS_USB_DN: JU1.2 UG1.5
GPS_USB_DP: JU1.3 UG1.6
INTVCC1: RP10.1 U19.B6 U19.C4 U19.E6 U19.F4 U19.H6 U19.J4 U19.K5 U19.L6
JTAG_R_TCK: R6.1 U2.16
JTAG_R_TDI: R11.1 U2.17
JTAG_R_TDO: R12.1 U2.18
JTAG_R_TMS: R3.1 U2.19
JTAG_TCK: J2.E28 R10.2 R21.1 U4.4
JTAG_TDI: J2.F23 R7.2 U5.4
JTAG_TDO: J2.B25 R8.2 U6.4
JTAG_TMS: J2.D26 R9.2 U3.4
LEDG0: J1.C13 R24.1
LEDG1: J1.G7 R27.1
LEDG2: J1.G13 R30.1
LEDG3: J1.F7 R33.1
M2_DEV_CLKN: C76.2 U13.15
M2_DEV_CLKP: C77.2 U13.16
M2_NVME_DET: J17.69 R64.2
M2_PERST: J2.F7 J17.50 R63.2
NVME_ACT: D8.2(CATHODE) J17.10
OSCI: C11.1 U2.2 Y1.2
OSCO: C14.1 U2.3 Y1.1
PHY_LED_1000: J16.11 RL15.1 U12.22
PHY_LED_ACT: J16.14 RL18.1 U12.21
PHY_MDC: J2.D24 U12.40
PHY_MDINT: RL11.1 U12.20
PHY_MDIO: J2.E24 RL10.1 U12.39
PHY_RX_CLK: J2.G21 RL21.1 U12.31
PHY_RX_CTRL: J2.F21 RL17.1 U12.30
PHY_RXD0: J2.E20 RL20.1 U12.29
PHY_RXD1: J2.D22 RL19.1 U12.28
PHY_RXD2: J2.B23 RL16.1 U12.26
PHY_RXD3: J2.E22 RL14.1 U12.25
PHY_TRXN0: J16.3 U12.10
PHY_TRXN1: J16.7 U12.13
PHY_TRXN2: J16.6 U12.16
PHY_TRXN3: J16.9(T4-) U12.19
PHY_TRXP0: J16.2 U12.9
PHY_TRXP1: J16.4 U12.12
PHY_TRXP2: J16.5 U12.15
PHY_TRXP3: J16.8 U12.18
PHY_TX_CLK: J2.F19 U12.33
PHY_TX_CTRL: J2.C21 U12.32
PHY_TXD0: J2.G19 U12.34
PHY_TXD1: J2.C17 U12.35
PHY_TXD2: J2.B17 U12.36
PHY_TXD3: J2.C23 U12.37
PHY_XTAL_IN: C57.2 U12.5 Y2.2
PHY_XTAL_OUT: C58.2 U12.4(XTLO) Y2.1
PPS_1S_GPS: J1.B9 UG1.3
PS_DONE: J2.C27 R75.2
PS_ERR_STAT: J2.C25 R81.2
PS_ERROR: J2.G23 R79.2
PS_MODE0: J2.G25 SWC3.1
PS_MODE1: J2.E26 SWC2.1
PS_MODE2: J2.F25 SWC1.3
PS_MODE3: J2.D28 SWC1.1
PS_POR: J2.G11 R209.1
PS_POR_B: R209.2 U12.1
RX_00_N: CAB49.1 J1.C46 LAB42.2
RX_00_P: CAB51.1 J1.B46 LAB42.1
RX_01_N: CAB52.1 J1.G46 LAB44.2
RX_01_P: CAB54.1 J1.F46 LAB44.1
RX_02_N: CAB55.1 J1.C42 LAB46.2
RX_02_P: CAB57.1 J1.B42 LAB46.1
RX_03_N: CAB58.1 J1.G42 LAB48.2
RX_03_P: CAB60.1 J1.F42 LAB48.1
RX_04_N: CAB61.1 J1.C38 LAB50.2
RX_04_P: CAB63.1 J1.B38 LAB50.1
RX_05_N: CAB64.1 J1.G38 LAB52.2
RX_05_P: CAB66.1 J1.F38 LAB52.1
RX_06_N: CAB67.1 J1.C34 LAB54.2
RX_06_P: CAB69.1 J1.B34 LAB54.1
RX_07_N: CAB70.1 J1.G34 LAB56.2
RX_07_P: CAB72.1 J1.F34 LAB56.1
RXD_GPS: J2.C7 RG3.1
SDIO_CLK: J2.G13 J3.5
SDIO_CMD: J2.C13 J3.3
SDIO_DAT0: J2.D12 J3.7
SDIO_DAT1: J2.E14 J3.8
SDIO_DAT2: J2.F13 J3.1
SDIO_DAT3: J2.D14 J3.2 R2.2
SDIO_DETECT: J2.E12 J3.9 R1.2
SFP_VCCRX: C45.1 C46.1 FB6.2 J40.15
SFP_VCCTX: C47.1 C48.1 FB7.2 J40.16
SYS_CLK_OUT_N: CAB76.2 J2.C4
SYS_CLK_OUT_P: J2.B4 R93.2 R94.1
SYS_RESET#: J2.B27 SWC4.1
SYSREF_IN_N: CAB73.2 J2.E5
SYSREF_IN_P: J2.D5(SYSREF_P) R89.2
TRIG_IN: J1.C7 R76.1
TRIG_OUT: J1.B7 R82.1
TX_00_N: J1.C30 LAB2.2 LAB3.2
TX_00_P: J1.B30 LAB3.1 LAB4.2
TX_01_N: J1.G30 LAB7.2 LAB8.2
TX_01_P: J1.F30 LAB8.1 LAB9.2
TX_02_N: J1.C26 LAB12.2 LAB13.2
TX_02_P: J1.B26 LAB13.1 LAB14.2
TX_03_N: J1.G26 LAB17.2 LAB18.2
TX_03_P: J1.F26 LAB18.1 LAB19.2
TX_04_N: J1.C22 LAB22.2 LAB23.2
TX_04_P: J1.B22 LAB23.1 LAB24.2
TX_05_N: J1.G22 LAB27.2 LAB28.2
TX_05_P: J1.F22 LAB28.1 LAB29.2
TX_06_N: J1.C18 LAB32.2 LAB33.2
TX_06_P: J1.B18 LAB33.1 LAB34.2
TX_07_N: J1.G18 LAB37.2 LAB38.2
TX_07_P: J1.F18 LAB38.1 LAB39.2
TXD_GPS: J1.B13 J2.B9 RG2.1
UART0_RX: J2.B13 U7.4
UART0_TX: J2.F11 U8.4
USB_5V: C93.1 C94.1 D9.2 D10.2 FB12.1 R67.1 U17.6(OUT2) U17.8
USB_CLK: R70.1 U15.26
USB_CLKOUT: J2.C19 U15.1
USB_CPEN: U15.17 U17.1
USB_DATA0: J2.D16 U15.3
USB_DATA1: J2.B19 U15.4
USB_DATA2: J2.D18 U15.5
USB_DATA3: J2.E16 U15.6
USB_DATA4: J2.G15 U15.7
USB_DATA5: J2.B21 U15.9
USB_DATA6: J2.G17 U15.10
USB_DATA7: J2.F17 U15.13
USB_DIR: J2.D20 U15.31
USB_DM: D9.3 J18.2 U15.19
USB_DP: D10.3 J18.3 U15.18
USB_ID: R69.2 U15.23
USB_NXT: J2.E18 U15.2
USB_RESET#: J2.E8 R66.2 U15.27
USB_RX_N: C92.1 J18.5 U18.1 U18.8
USB_RX_P: C95.1 J18.6 U18.2 U18.7
USB_STP: J2.F15 U15.29
USB_TX_N: C88.1 C97.1 U18.3 U18.6
USB_TX_P: C89.1 C96.1 U18.4 U18.5(OUT4)
USER_IO0: J1.C11 J11.2
USER_IO1: J1.F9 J11.3
USER_IO2: J1.G9 J11.4
USER_IO3: J1.D14 J11.5
USER_IO4: J1.E14 J11.6
USER_IO5: J1.F11 J11.7
USER_IO6: J1.G11 J11.8
USER_IO7: J1.F13 J11.9
USER_IOB0: J1.C9 J9.1
USER_IOB1: J1.D8 J9.2
USER_IOB2: J1.E8 J9.3
USER_IOB3: J1.D10 J9.4
USER_IOB4: J1.E10 J9.5
USER_IOB5: J1.D12 J9.6
USER_IOB6: J1.E12 J9.7
USER_IOB7: J1.B11 J9.8
ZQSFP_VCC: C33.1 C34.1 FB3.2 J12.30
ZQSFP_VCCRX: C35.1 C36.1 FB4.2 J12.10
ZQSFP_VCCTX: C37.1 C38.1 FB5.2 J12.29(VCC_TX)
N21034969: RG1.1 UG1.9
N21034983: JA17.1 LG1.2 UG1.11
N21034987: CG1.1 LG1.1 RG1.2
N22362940: R70.2 X1.3
N22363073: C87.2 FB13.2 J18.4
N22363075: C91.1 FB14.2 J18.10 J18.11
N22363103: C87.1 FB12.2 J18.1(VBUS)
N22363153: D11.2(CATHODE) U17.2
N22481429: C108.2 D19.1 J23.2 J23.3 J26.4 J26.5 J26.6 U22.3(PSG)
N22481433: FB15.1 J23.1 J26.1 J26.2 J26.3
N22481513: C108.1 SP1.1 U22.1
N22481515: D19.2(CATHODE) FB15.2 SP1.2
N22531080: C29.1 U9.4
N22531228: R18.1 U10.4
N22531283: D3.1 R21.2
N22533284: RP4.2 U19.F6
N22533286: RP5.2 U19.J6
N22533326: RP9.2 U19.F2
N22533328: RP7.1 RP8.1 RP9.1 RP10.2 RP11.1 TP1.1(A)
N22533342: COUT5.1 U19.A6 U19.D6 U19.G6 U19.K6
N22533629: C105.1 U19.B7 U19.E7
N22533693: RP1.1 U19.A7 U19.D7 U19.G7 U19.J7
N22533770: RP3.2 U19.C6
N22533812: RP6.2 U19.K7
N22533845: RP7.2 U19.C3
N22533851: RP8.2 U19.C2
N22533867: RP11.2 U19.J2
N22533883: C106.1 U19.H7
N22533912: RP12.2 U19.F3
N22533999: C107.1 U19.L7
N22534068: RP1.2 RP2.1
N22535757: COUT9.1 COUT10.1 COUT11.1 FBP1.2 FBP2.2 R97.2 U20.6 U20.7(VOUT2)
N22535954: COUT12.1 COUT13.1 COUT14.1 FBP7.2 FBP8.2 FBP9.2 FBP10.2 FBP17.2 FBP18.2 FBP19.2 FBP20.2 R102.2 U21.6 U21.7(VOUT2)
N22536146: R95.2 R96.1
N22536167: R95.1 U20.4
N22536169: R97.1 U20.5
N22536187: R99.1 U20.11
N22536481: R100.2 R101.1
N22536506: R100.1 U21.4
N22536508: R102.1 U21.5
N22536526: R104.1 U21.11
N22545864: LAB32.1 TAB7.4
N22545929: CAB40.1 TAB7.3
N22545941: CAB40.2 RAB26.1 RAB27.1
N22545947: CAB42.1 RAB26.2 RAB28.1
N22545953: CAB42.2 JA7.1
N22545955: LAB34.1 TAB7.6(SE D)
N22546147: LAB37.1 TAB8.4
N22546214: CAB46.1 TAB8.3
N22546226: CAB46.2 RAB30.1 RAB31.1
N22546232: CAB48.1 RAB30.2 RAB32.1
N22546238: CAB48.2 JA8.1
N22546240: LAB39.1 TAB8.6(SE D)
N22613335: D4.2(CATHODE) J5.2 Q1.3
N22613341: D5.2(CATHODE) J6.2 Q2.3
N22613343: D6.2(CATHODE) J7.2 Q3.3
N22613345: D7.2(CATHODE) J8.2 Q4.3
N22692224: LAB2.1 TAB1.4
N22692289: CAB4.1 TAB1.3
N22692291: CAB4.2 RAB2.1 RAB3.1
N22692307: CAB6.1 RAB2.2 RAB4.1
N22692313: CAB6.2 JA1.1
N22692315: LAB4.1 TAB1.6(SE D)
N22692505: LAB7.1 TAB2.4
N22692570: CAB10.1 TAB2.3
N22692582: CAB10.2 RAB6.1 RAB7.1
N22692588: CAB12.1 RAB6.2 RAB8.1
N22692594: CAB12.2 JA2.1
N22692596: LAB9.1 TAB2.6(SE D)
N22693543: LAB12.1 TAB3.4
N22693600: CAB16.1 TAB3.3
N22693620: CAB16.2 RAB10.1 RAB11.1
N22693626: CAB18.1 RAB10.2 RAB12.1
N22693632: CAB18.2 JA3.1
N22693634: LAB14.1 TAB3.6(SE D)
N22693824: LAB17.1 TAB4.4
N22693889: CAB22.1 TAB4.3
N22693901: CAB22.2 RAB14.1 RAB15.1
N22693907: CAB24.1 RAB14.2 RAB16.1
N22693913: CAB24.2 JA4.1
N22693915: LAB19.1 TAB4.6(SE D)
N22694836: LAB22.1 TAB5.4
N22694901: CAB28.1 TAB5.3
N22694903: CAB28.2 RAB18.1 RAB19.1
N22694919: CAB30.1 RAB18.2 RAB20.1
N22694925: CAB30.2 JA5.1
N22694927: LAB24.1 TAB5.6(SE D)
N22695117: LAB27.1 TAB6.4
N22695182: CAB34.1 TAB6.3
N22695184: CAB34.2 RAB22.1 RAB23.1
N22695200: CAB36.1 RAB22.2 RAB24.1
N22695206: CAB36.2 JA6.1
N22695208: LAB29.1 TAB6.6(SE D)
N22696156: CAB49.2 LAB41.2 TAB9.4
N22696251: CAA4.1 JA9.1
N22696263: CAA4.2 RAA2.1 RAA3.1
N22696269: CAB50.2 RAA2.2 RAA4.1
N22696275: CAB50.1 TAB9.3
N22696283: CAB51.2 LAB41.1 TAB9.6(SE D)
N22696463: CAB52.2 LAB43.2 TAB10.4
N22696550: CAA9.1 JA10.1
N22696562: CAA9.2 RAA6.1 RAA7.1
N22696568: CAB53.2 RAA6.2 RAA8.1
N22696574: CAB53.1 TAB10.3
N22696580: CAB54.2 LAB43.1 TAB10.6(SE D)
N22697544: CAB55.2 LAB45.2 TAB11.4
N22697619: CAA14.1 JA11.1
N22697639: CAA14.2 RAA10.1 RAA11.1
N22697645: CAB56.2 RAA10.2 RAA12.1
N22697651: CAB56.1 TAB11.3
N22697657: CAB57.2 LAB45.1 TAB11.6(SE D)
N22697841: CAB58.2 LAB47.2 TAB12.4
N22697916: CAA19.1 JA12.1
N22697918: CAA19.2 RAA14.1 RAA15.1
N22697942: CAB59.2 RAA14.2 RAA16.1
N22697948: CAB59.1 TAB12.3
N22697954: CAB60.2 LAB47.1 TAB12.6(SE D)
N22698936: CAB61.2 LAB49.2 TAB13.4
N22699019: CAA24.1 JA13.1
N22699033: CAA24.2 RAA18.1 RAA19.1
N22699037: CAB62.2 RAA18.2 RAA20.1
N22699043: CAB62.1 TAB13.3
N22699049: CAB63.2 LAB49.1 TAB13.6(SE D)
N22699217: CAB64.2 LAB51.2 TAB14.4
N22699300: CAA29.1 JA14.1
N22699302: CAA29.2 RAA22.1 RAA23.1
N22699318: CAB65.2 RAA22.2 RAA24.1
N22699324: CAB65.1 TAB14.3
N22699330: CAB66.2 LAB51.1 TAB14.6(SE D)
N22700324: CAB70.2 LAB55.2 TAB16.4
N22700407: CAA39.1 JA16.1
N22700409: CAA39.2 RAA30.1 RAA31.1
N22700425: CAB71.2 RAA30.2 RAA32.1
N22700431: CAB71.1 TAB16.3
N22700437: CAB72.2 LAB55.1 TAB16.6(SE D)
N22700663: CAB67.2 LAB53.2 TAB15.4
N22700760: CAA34.1 JA15.1
N22700762: CAA34.2 RAA26.1 RAA27.1
N22700790: CAB68.2 RAA26.2 RAA28.1
N22700796: CAB68.1 TAB15.3
N22700802: CAB69.2 LAB53.1 TAB15.6(SE D)
N22703406: CAB74.1 R91.2 R92.1
N22703440: R88.2 R89.1 R90.1
N22704009: JA20.1 R88.1
N22704037: JA21.1 R91.1
N22704041: JA22.1 R93.1
N22704055: D14.3 R76.2 R77.1
N22704067: D16.3 R82.2 R83.1
N22704077: JA18.1 R77.2
N22704079: JA19.1 R83.2
N22849015: JFA6.1 RP129.2
N210349064: RG2.2 UG1.20
N210349065: RG3.2 UG1.21
N210349066: FBA1.1 UG1.22(V_BCKP)
N210349067: FBA2.1 UG1.23
N213200537: J12.8 R36.1
N213200538: J12.9 R37.1
N223618380: C76.1 J17.53
N223618460: C77.1 J17.55
N223618760: D8.1 R62.2
N223630967: C88.2 J18.8
N223630968: C89.2 J18.9
N223631803: R73.1 U17.4
N223632060: D11.1 R72.1
N225299922: R4.2 U2.6
N225299926: R5.1 U2.14
N225300261: R3.2 U3.3
N225301861: R6.2 U4.3
N225303331: R11.2 U5.3
N225303874: J4.A5 R13.1
N225305011: R12.2 U6.3
N225306131: R14.2 U7.3
N225307991: R16.2 U8.3
N226131680: Q1.1 R24.2
N226131900: Q2.1 R27.2
N226132090: Q3.1 R30.2
N226132280: Q4.1 R33.2
N226132550: J5.1 R23.2
N226132710: D4.1 R22.2
N226132880: D5.1 R25.2
N226132960: D6.1 R28.2
N226133040: D7.1 R31.2
N226133650: J6.1 R26.2
N226133910: J7.1 R29.2
N226134170: J8.1 R32.2
N227036900: D12.1 R74.2
N227036901: D12.2(CATHODE) Q5.3
N227037101: Q5.1 R75.1
N227037300: D13.1 R78.2
N227037301: D13.2(CATHODE) Q6.3
N227037501: Q6.1 R79.1
N227037700: D15.1 R80.2
N227037701: D15.2(CATHODE) Q7.3
N227037901: Q7.1 R81.1
N227038121: R84.2 SWC1.2
N227038123: R85.2 SWC1.4
N227038461: R86.2 SWC2.2
N227038671: R87.2 SWC3.2
N227138570: R48.2 U12.7
N227140082: FB9.2 U12.2
N227630989: C53.1 J16.1
N229316351: R208.1 Y7.1
N231249851: J40.3 R185.1
N231249931: J40.2 R184.1
N231250011: J40.4 R186.1
N231250091: J40.5 R187.1
N231250171: J40.6 R188.1
N231250401: J40.7 R189.1
N231250481: J40.9 R190.1
N231250561: J40.8 R191.1
N2132005310: J12.11 R34.1
N2132005311: J12.12 R35.1
N2132005326: J12.27 R38.1
N2132005327: J12.28 R39.1
N2132005330: J12.31 R40.1
N2236203114: C68.1 J17.29
N2236203115: C69.1 J17.31
N2236203117: C70.1 J17.35
N2236203118: C71.1 J17.37
N2236203120: C72.1 J17.41
N2236203121: C73.1 J17.43
N2236203123: C74.1 J17.47
N2236203124: C75.1 J17.49
N2236302324: R68.2 U15.24
N2236302326: R67.2 U15.22
N2236302328: C90.1 U15.20
N2252999246: FB1.2 U2.4
N2252999247: FB2.2 U2.9
N2253038716: J4.B5 R15.1
N2276309811: J16.12 R49.1
N2276309813: J16.13 R50.1

Pads without a net: J1 D33 D37 D41 D45 E35 E39 E43 E47; J2 B7 B29 B33 B35 B43 C9 C29 C33 C35 C43 D30 D32 D46 E30 E32 E46 F27 F29 F31 F35 F47 G27 G29 G31 G35 G47; J4 A2 A3 A8 A10 A11 B2 B3 B8 B10 B11; J10 12; J11 11 12; J17 5 6 7 8 11 13 17 19 20 22 23 24 25 26 28 30 32 34 36 38 40 42 44 46 48 52 54 56 58 67 68 76 77; J26 7 8; J32 3; J40 A1 A2 A3 A4 A5 A6 A8 A9 A10; JU1 1 4; NOREF#2 1; NOREF#5 1; NOREF#9 1; NOREF#10 1; NOREF#11 1; NOREF#12 1; U2 21 22 23 24 26 27 28 29 30 32 33 34 36 40 41 43 44 45 46 48 52 53 54 55 57 58 59 60; U10 6 7; U12 23 24; U13 11 12 13 14; U15 12 15 16 25; U17 5; U19 C7 J3; U20 12; U21 12; UG1 1 2 4 8 14 15 16 17 18 19; X1 1; XS1 2; XS2 2; Y7 2

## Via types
v1: diameter 0.457, hole 0.254, TOP to BOTTOM, 6864 vias

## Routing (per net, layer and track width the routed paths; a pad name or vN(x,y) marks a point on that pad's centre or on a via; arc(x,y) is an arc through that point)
+1.8V: length 15
  TOP w0.254: U15.30 v1(381.55,42.09) ; U15.28 v1(382.55,42.09)
  TOP w0.381: v1(382.48,18.49) C2.1 U3.6 ; v1(390.86,18.49) C4.1 U4.6 ; U6.6 C8.1 v1(385.27,18.49) ; R99.2 v1(354.08,46.63) ; R64.1 v1(335.95,-9.16) ; U5.6 C6.1 v1(388.06,18.49)
  BOTTOM w0.508: R7.1 v1(388.06,18.49) ; R8.1 v1(385.27,18.49) ; R10.1 v1(390.86,18.49) ; R9.1 v1(382.48,18.49)
  vias: v1(367.56,52.78) v1(367.56,51.78) v1(367.56,50.78) v1(367.56,49.78) v1(368.56,52.78) v1(368.56,51.78) v1(368.56,50.78) v1(368.56,49.78)
+3.3V: length 86.5
  TOP w0.254: U15.32 380.55,41.67 v1(380.13,42.09) ; U15.14 v1(383.05,35.54) ; J17.12 323.04,5.09 ; U15.11 v1(381.55,35.54) ; v1(379.03,36.56) 379.53,37.06 U15.8
  TOP w0.305: J17.70 v1(323.05,-9.41) ; J17.18 v1(323.05,3.59) ; J17.4 323.01,7.09
  TOP w0.356: U13.8 v1(347.2,32.86) ; U13.4 346.72,30.26 v1(347.05,29.92)
  TOP w0.381: v1(376.89,18.49) C18.1 U8.6 ; R63.1 351.38,48.72 v1(351.15,48.49) ; R32.1 v1(307.39,-20.84) ; R78.1 v1(352.54,58.1) ; R23.1 v1(280.8,-20.84) ; v1(395.66,24.24) 394.82,24.24 394.82,24.23 J3.4 ; FBA2.2 v1(237.27,-23.91) ; R72.2 v1(383.77,32.23) ; v1(379.68,18.49) C13.1 U7.6 ; R26.1 v1(289.66,-20.84) ; R1.1 v1(390.25,19.14) ; UG1.7 v1(230.84,-4.73) ; FBA1.2 v1(235.56,-23.91) ; v1(386.82,44.58) 386.57,44.82 X1.4 ; R22.1 v1(286.84,-22.83) ; R74.1 v1(352.54,63.23) ; R25.1 v1(295.71,-22.83) ; R29.1 v1(298.53,-20.84) ; R80.1 v1(352.54,52.97) ; R31.1 v1(313.44,-22.83) ; R28.1 v1(304.57,-22.83)
  TOP w0.508: R104.2 v1(312.5,123.21) ; FB5.1 v1(343.76,85.37) ; FB3.1 v1(343.92,83.29) ; v1(340.09,35.69) R208.2 340.84,36.5 340.18,37.16 Y7.6
  BOTTOM w0.381: v1(323.05,-10.41) 323.02,-10.44 C80.1 ; C103.1 379.01,36.58 v1(379.03,36.56) ; v1(395.66,24.24) 395.01,24.88 394.85,24.88 ; v1(380.13,42.09) 380.42,41.8 C101.1 380.8,42.47 381.14,42.81 R66.1 ; R190.2 v1(371.02,131.57) ; v1(383.05,35.54) 383.72,35.54 C104.1 ; v1(381.55,35.54) 381.58,35.57 C102.1 ; R184.2 v1(376.88,127.62) ; v1(323.05,-9.41) 322.88,-9.25 C81.1 ; FBL2.1 v1(387.41,63.64) ; R186.2 v1(376.88,128.67) ; R187.2 v1(371.02,129.47) ; FBL3.1 383.95,61.46 v1(384.2,61.21) ; v1(386.82,44.58) 386.13,45.26 C98.1 ; R189.2 v1(371.02,130.52) ; R188.2 v1(376.88,129.73) ; v1(312.5,123.21) 308.56,127.15 RP129.1 ; R191.2 v1(376.88,130.78)
  BOTTOM w0.508: R39.2 354.71,83.34 354.33,82.96 353.14,82.96 v1(352.99,83.11) 353.64,83.76 R38.2 ; FB4.1 v1(367.79,84.4) ; R34.2 v1(363.98,86.73) ; R37.2 v1(363.98,84.89) ; CG2.1 231.32,-5.21 v1(230.84,-4.73) 230.3,-5.26 CG3.1 ; D14.2 v1(208.89,-22.97) ; C40.1 v1(367.08,85.96) ; R35.2 v1(363.98,85.8) ; C288.1 C289.1 340.84,34.94 v1(340.09,35.69) ; R62.1 323.63,6.69 ; R36.2 v1(362.43,80.06) ; D16.2 v1(221.05,-24.87)
  vias: v1(323.05,7.59) v1(323.05,6.59) v1(323.05,4.59) v1(327.3,107.16) v1(327.3,105.89) v1(327.3,104.62) v1(328.57,107.16) v1(328.57,105.89) v1(328.57,104.62) v1(329.84,107.16) v1(329.84,105.89) v1(329.84,104.62) v1(331.11,107.16) v1(331.11,105.89) v1(331.11,104.62) v1(347.05,28.62) v1(348.05,29.92) v1(348.05,28.62) v1(348.89,23.66) v1(348.89,22.66) v1(349.71,31.49) v1(349.71,29.69) v1(350.16,23.66) v1(350.16,22.66) v1(353.03,132) v1(354.03,132) v1(354.18,128.07) v1(354.18,127.07)
AVDD33: length 1.5
  TOP w0.203: U12.14 v1(383.79,63.61)
  BOTTOM w0.254: CL15.2 383.53,63.87 v1(383.79,63.61)
AVDDL: length 5.5
  TOP w0.203: v1(380.58,60.1) 380.58,60.41 380.64,60.48 U12.6 ; U12.17 383.81,64.81 v1(383.82,64.82) ; U12.11 v1(383.79,62.41)
  BOTTOM w0.508: CL13.2 383.63,65.01 v1(383.82,64.82) ; CL10.2 383.6,62.6 v1(383.79,62.41) ; CL11.2 380.84,60.07 380.81,60.1 v1(380.58,60.1)
  vias: v1(374.04,56.63) v1(374.6,57.34)
DGND: length 1436
  TOP w0.173: 177.63,53.42 177.53,53.42
  TOP w0.254: U2.11 389.41,5.11 v1(389.65,4.87) 389.39,4.61 U2.10 ; v1(330.6,-6.16) J17.57 v1(333.29,-6.16) ; U2.47 v1(378.99,0.61) ; v1(333.29,2.84) J17.21 v1(330.6,2.84) ; v1(333.29,-0.16) J17.33 v1(330.6,-0.16) ; U2.51 381.58,-0.97 v1(382.08,-1.47) ; v1(333.42,-3.16) J17.45 v1(330.6,-3.16) ; J4.A1 v1(398.92,5.12) ; v1(333.29,-4.66) J17.51 v1(330.6,-4.66) ; U2.15 389.56,7.11 v1(389.86,7.42) ; J17.73 v1(333.29,-10.16) ; v1(333.29,1.34) J17.27 v1(330.6,1.34) ; U2.1 v1(388.78,-0.43) ; v1(390.16,6.36) 389.91,6.11 U2.13 ; J17.75 v1(330.6,-10.66) ; v1(333.29,5.84) J17.9 v1(330.6,5.84) ; v1(333.29,-1.66) J17.39 v1(330.6,-1.66) ; v1(333.29,4.34) J17.15 v1(330.6,4.34) ; v1(333.29,7.84) J17.1 v1(330.6,7.84) ; U2.25 v1(384.08,9.2) ; J4.A12 v1(398.92,11.12) ; U2.35 379.23,6.61 v1(378.95,6.89) ; v1(333.29,7.34) J17.3 v1(330.6,7.34) ; U2.5 v1(389.66,2.11) ; J17.71 v1(330.6,-9.66)
  TOP w0.356: U13.5 346.7,30.91 347.13,31.33 v1(347.13,31.54)
  TOP w0.381: J1.D6 v1(226.83,85.42) ; v1(376.71,133.28) J40.10 v1(374.22,133.28) ; RL19.2 v1(379.2,71.04) ; v1(173.13,91.14) 172.61,91.14 RAB15.2 ; v1(170.46,-8.86) 169.94,-8.86 RAA7.2 ; v1(173.13,11.14) 172.61,11.14 RAA16.2 ; v1(173.13,71.14) 172.61,71.14 RAB7.2 ; v1(170.46,1.14) 169.94,1.14 RAA11.2 ; RAB3.2 172.61,61.14 v1(173.13,61.14) ; v1(368.5,130.47) J40.14 v1(366.01,130.47) ; TAB1.1 v1(179.2,59.61) ; J1.F10 v1(223.02,80.34) ; TAB9.2 v1(179.2,-19.12) ; J1.D7 v1(226.83,84.15) ; J1.F6 v1(223.02,85.42) ; J1.E9 v1(225.56,80.34) ; J1.H12 v1(220.48,77.8) ; TAB6.1 v1(179.2,109.61) ; RAB31.2 172.61,131.14 v1(173.13,131.14) ; TAB4.2 v1(179.2,90.88) ; RAA4.2 172.61,-18.86 v1(173.13,-18.86) ; RAB4.2 169.94,61.14 v1(170.46,61.14) ; v1(308.55,-19.83) Q4.2 308.55,-20.98 ; TAB15.1 v1(179.2,39.61) ; J1.D11 v1(226.83,79.07) ; v1(359.74,80.33) J12.4 357.75,80.33 v1(357.35,79.93) ; TAB5.2 v1(179.2,100.88) ; v1(170.46,71.14) 169.94,71.14 RAB8.2 ; v1(390.32,35.3) 390.79,35.76 390.86,35.76 ; J1.B10 v1(229.37,80.34) ; C41.2 v1(348.83,26.13) ; C41.2 v1(346.38,26.13) ; C41.2 v1(347.6,27.36) ; J1.H10 v1(220.48,80.34) ; v1(357.35,79.93) J12.35 v1(354.91,79.93) ; v1(357.35,79.93) v1(357.35,77.53) ; v1(357.35,79.93) v1(357.35,82.33) ; v1(368.5,132.87) J40.11 v1(366.01,132.87) ; v1(359.74,92.33) J12.19 357.75,92.33 v1(357.35,91.93) ; RAA19.2 169.94,21.14 v1(170.46,21.14) ; XS1.3 v1(344.79,25.53) ; FB14.1 390.86,35.76 ; 390.86,35.76 v1(390.32,36.3) ; RL18.2 v1(383.2,71.04) ; J1.C6 v1(228.1,85.42) ; TAB5.1 v1(179.2,99.61) ; J1.G10 v1(221.75,80.34) ; v1(173.13,41.14) 172.61,41.14 RAA28.2 ; RAA3.2 169.94,-18.86 v1(170.46,-18.86) ; RAB12.2 169.94,81.14 v1(170.46,81.14) ; v1(330.6,1.34) v1(330.6,-0.16) v1(330.6,-1.66) v1(330.6,-3.16) v1(330.6,-4.66) v1(330.6,-6.16) ; J1.D9 v1(225.56,81.61) ; RAA23.2 169.94,31.14 v1(170.46,31.14) ; TAB15.2 v1(179.2,40.88) ; TAB13.1 v1(179.2,19.61) ; v1(354.91,89.53) J12.23 v1(357.35,89.53) ; J1.B8 v1(229.37,82.88) ; J1.E6 v1(224.29,85.42) ; J1.F12 v1(224.29,77.8) ; J1.A7 v1(230.64,84.15) ; TAB13.2 v1(179.2,20.88) ; v1(170.46,41.14) 169.94,41.14 RAA27.2 ; v1(359.74,87.53) J12.13 357.75,87.53 v1(357.35,87.13) ; J1.A6 v1(230.64,85.42) ; J1.H7 v1(220.48,84.15) ; v1(357.35,89.53) 357.75,89.93 J12.16 v1(359.74,89.93) ; v1(357.35,89.53) v1(357.35,87.13) ; v1(357.35,89.53) v1(357.35,91.93) ; v1(357.35,82.33) 357.75,82.73 J12.7 v1(359.74,82.73) ; v1(357.35,82.33) v1(357.35,87.13) ; v1(357.35,82.33) J12.32 v1(354.91,82.33) ; v1(380.4,59.05) 380.4,58.99 379.86,58.45 C57.1 380.56,57.9 381.6,56.87 v1(381.6,56.15) v1(381.6,54.32) 380.98,53.69 v1(379.84,53.69) v1(377.79,53.69) 375.57,53.69 v1(375.39,53.87) 374.94,54.32 v1(374.94,56.05) 374.94,56.88 375.97,57.92 C58.1 ; RAA12.2 172.61,1.14 v1(173.13,1.14) ; TAB10.2 v1(179.2,-9.12) ; v1(173.13,121.14) 172.61,121.14 RAB27.2 ; v1(170.46,111.14) 169.94,111.14 RAB24.2 ; RAB28.2 169.94,121.14 v1(170.46,121.14) ; v1(179.2,89.61) TAB4.1 v1(176.39,89.61) ; C48.2 v1(360.61,125.45) ; TAB11.2 v1(179.2,0.88) ; J1.G8 v1(221.75,82.88) ; J1.B6 v1(229.37,85.42) ; RAA24.2 172.61,31.14 v1(173.13,31.14) ; v1(170.46,131.14) 169.94,131.14 RAB32.2 ; TAB14.1 v1(179.2,29.61) ; J1.H9 v1(220.48,81.61) ; TAB10.1 v1(179.2,-10.39) ; 398.02,13.31 C15.2 ; 398.02,13.31 v1(398.55,12.78) ; 398.02,13.31 v1(398.55,13.84) ; J1.H13 v1(220.48,76.53) ; J1.F8 v1(223.02,82.88) ; v1(354.91,91.93) J12.20 v1(357.35,91.93) ; J1.E7 v1(224.29,84.15) ; TAB12.2 v1(179.2,10.88) ; J1.D13 v1(226.83,76.53) ; RAA8.2 172.61,-8.86 v1(173.13,-8.86) ; J1.B12 v1(229.37,77.8) ; C44.2 v1(356.84,131.83) ; RAB16.2 169.94,91.14 v1(170.46,91.14) ; v1(173.13,51.14) 172.61,51.14 RAA32.2 ; J1.H6 v1(220.48,85.42) ; v1(368.5,125.67) J40.20 v1(366.01,125.67) ; v1(357.35,87.13) J12.26 v1(354.91,87.13) ; v1(357.35,77.53) J12.38 v1(354.91,77.53) ; v1(357.35,77.53) 357.75,77.93 J12.1 v1(359.74,77.93) ; J1.H8 v1(220.48,82.88) ; C46.2 v1(360.61,132.42) ; Q3.2 v1(299.69,-19.83) ; RAB11.2 172.61,81.14 v1(173.13,81.14) ; RAA31.2 169.94,51.14 v1(170.46,51.14) ; J1.C12 v1(228.1,77.8) ; J1.E13 v1(225.56,76.53) ; TAB16.1 v1(179.2,49.61) ; v1(170.46,11.14) 169.94,11.14 RAA15.2 ; RAB23.2 172.61,111.14 v1(173.13,111.14) ; J1.C8 v1(228.1,82.88) ; TAB8.1 v1(179.2,129.61) ; RAA20.2 172.61,21.14 v1(173.13,21.14) ; v1(173.13,101.14) 172.61,101.14 RAB19.2 ; RL20.2 v1(378.2,71.04) ; RL17.2 v1(377.2,71.04) ; TAB3.1 v1(179.2,79.61) ; TAB6.2 v1(179.2,110.88) ; J1.A9 v1(230.64,81.61) ; TAB2.1 v1(179.2,69.61) ; RL16.2 v1(380.2,71.04) ; v1(376.71,126.08) J40.1 v1(374.22,126.08) ; J1.A10 v1(230.64,80.34) ; J1.A13 v1(230.64,76.53) ; J1.G6 v1(221.75,85.42) ; v1(368.5,128.07) J40.17 v1(366.01,128.07) ; TAB7.1 v1(179.2,119.61) ; Q2.2 v1(290.82,-19.83) ; v1(170.46,101.14) 169.94,101.14 RAB20.2 ; J1.C10 v1(228.1,80.34) ; Q1.2 v1(281.96,-19.83) ; XS2.3 v1(353.1,28.79) ; TAB14.2 v1(179.2,30.88) ; TAB2.2 v1(179.2,70.88) ; TAB16.2 v1(179.2,50.88) ; J1.G12 v1(221.75,76.53) ; TAB11.1 v1(179.2,-0.39) ; TAB9.1 v1(179.2,-20.39) ; TAB3.2 v1(179.2,80.88) ; J1.A8 v1(230.64,82.88) ; C42.2 v1(344.87,24.35) ; J1.E11 v1(225.56,79.07) ; J1.H11 v1(220.48,79.07) ; TAB12.1 v1(179.2,9.61) ; J1.A12 v1(230.64,77.8) ; J1.A11 v1(230.64,79.07) ; TAB7.2 v1(179.2,120.88) ; TAB1.2 v1(179.2,60.88) ; TAB8.2 v1(179.2,130.88)
  TOP w0.508: J2.B42 v1(328.33,39.7) J2.A41 v1(328.33,40.97) J2.B40 ; J2.B42 v1(328.33,38.43) J2.A43 v1(328.33,37.16) J2.B44 ; J2.B42 J2.C42 ; J2.E21 v1(324.52,66.37) ; v1(228.1,32.08) J1.B47 v1(229.37,32.08) ; v1(228.1,32.08) J1.C47 ; v1(228.1,32.08) J1.C48 ; v1(228.1,32.08) J1.B48 ; J1.B20 v1(229.37,66.37) ; J1.B20 v1(228.1,66.37) ; J1.B20 v1(229.37,67.64) ; J1.B20 v1(228.1,67.64) ; v1(229.37,66.37) J1.B21 v1(228.1,66.37) ; v1(229.37,66.37) J1.A21 v1(229.37,65.1) J1.A22 v1(229.37,63.83) J1.A23 v1(229.37,62.56) ; v1(229.37,66.37) J1.A20 v1(229.37,67.64) ; J2.F48 J2.G48 ; J2.F48 v1(323.25,30.81) J2.E49 ; J2.F48 v1(323.25,32.08) J2.E47 ; J2.G48 v1(320.71,30.81) ; J2.G48 v1(320.71,32.08) J2.H47 v1(320.71,33.35) J2.G46 ; v1(229.37,56.21) J1.A28 v1(229.37,57.48) ; v1(229.37,56.21) J1.B29 v1(228.1,56.21) ; v1(229.37,56.21) J1.A29 v1(229.37,54.94) J1.A30 v1(229.37,53.67) J1.A31 v1(229.37,52.4) ; v1(229.37,56.21) J1.B28 ; J2.H3 v1(319.44,89.23) ; J2.H3 v1(319.44,87.96) J2.H4 v1(319.44,86.69) J2.H5 v1(320.71,86.69) J2.G5 v1(321.98,86.69) J2.F5 ; J2.H3 v1(320.71,89.23) J2.G3 v1(321.98,89.23) J2.F3 v1(323.25,89.23) J2.E3 ; v1(226.83,40.97) J1.D40 ; v1(226.83,40.97) J1.C41 ; v1(226.83,40.97) J1.C40 ; J1.D40 v1(226.83,42.24) ; J1.D40 J1.E40 ; J1.G44 v1(221.75,35.89) ; J1.G44 v1(223.02,37.16) ; J1.G44 v1(223.02,35.89) ; J1.G44 v1(221.75,37.16) ; v1(221.75,35.89) J1.H44 v1(221.75,37.16) ; v1(221.75,35.89) J1.G45 v1(223.02,35.89) ; v1(221.75,35.89) J1.H45 v1(221.75,34.62) J1.H46 v1(221.75,33.35) J1.H47 v1(221.75,32.08) ; J2.C48 v1(325.79,30.81) J2.D49 ; J2.C48 J2.B48 ; J2.C48 v1(325.79,32.08) J2.D47 ; J2.D25 v1(325.79,61.29) ; v1(229.37,42.24) J1.A40 v1(229.37,40.97) ; v1(229.37,42.24) J1.A39 v1(229.37,43.51) J1.A38 v1(229.37,44.78) J1.A37 v1(229.37,46.05) ; v1(229.37,42.24) J1.B39 v1(228.1,42.24) ; v1(229.37,42.24) J1.B40 ; C3.2 v1(390.86,10.62) ; J1.H14 221.75,73.99 ; 221.75,73.99 J1.G15 ; 221.75,73.99 J1.H15 221.75,72.72 ; 221.75,73.99 J1.G14 v1(223.02,73.99) ; J1.G48 v1(223.02,32.08) ; J1.G48 v1(221.75,30.81) ; J1.G48 v1(221.75,32.08) ; J1.G48 v1(223.02,30.81) ; v1(223.02,32.08) J1.F48 ; v1(223.02,32.08) J1.G47 v1(221.75,32.08) ; v1(223.02,32.08) J1.F47 ; J2.H42 v1(319.44,38.43) ; R68.1 v1(384.58,44.27) ; J2.D49 v1(325.79,29.54) ; J2.D49 J2.E49 ; v1(228.1,67.64) J1.B19 v1(229.37,67.64) ; v1(228.1,67.64) J1.C19 v1(226.83,67.64) ; v1(228.1,67.64) J1.C20 ; v1(229.37,37.16) J1.A44 v1(229.37,35.89) ; v1(229.37,37.16) J1.B44 ; v1(229.37,37.16) J1.B43 v1(228.1,37.16) ; v1(229.37,37.16) J1.A43 v1(229.37,38.43) J1.A42 v1(229.37,39.7) J1.A41 v1(229.37,40.97) ; J1.F48 v1(223.02,30.81) ; J1.F48 v1(224.29,30.81) ; J1.F48 v1(224.29,32.08) ; v1(228.1,47.32) J1.B36 ; v1(228.1,47.32) J1.C35 ; v1(228.1,47.32) J1.C36 ; v1(228.1,47.32) J1.B35 v1(229.37,47.32) ; J1.B36 v1(229.37,47.32) ; J1.B36 v1(229.37,46.05) ; J1.B36 v1(228.1,46.05) ; J1.D23 v1(226.83,63.83) J1.D22 ; J1.D23 v1(226.83,62.56) ; J1.D23 J1.E23 ; J2.G34 v1(320.71,48.59) J2.H35 v1(320.71,47.32) J2.G36 ; J2.G34 v1(320.71,49.86) J2.H33 v1(320.71,51.13) J2.G32 ; J2.G34 J2.F34 ; J1.G5 v1(221.75,86.69) ; J2.E37 v1(323.25,46.05) J2.F36 ; J2.E37 v1(323.25,44.78) J2.F38 ; J2.E37 J2.D37 ; J1.F20 v1(223.02,66.37) ; J1.F20 v1(224.29,67.64) ; J1.F20 v1(224.29,66.37) ; J1.F20 v1(223.02,67.64) ; v1(223.02,66.37) J1.G20 ; v1(223.02,66.37) J1.F21 v1(224.29,66.37) ; v1(223.02,66.37) J1.G21 v1(221.75,66.37) ; R101.2 v1(309.74,107.03) ; v1(223.02,42.24) J1.F40 ; v1(223.02,42.24) J1.G39 v1(221.75,42.24) ; v1(223.02,42.24) J1.F39 ; v1(223.02,42.24) J1.G40 ; J1.F40 v1(223.02,40.97) ; J1.F40 v1(224.29,40.97) ; J1.F40 v1(224.29,42.24) ; v1(223.02,62.56) J1.G23 v1(221.75,62.56) ; v1(223.02,62.56) J1.F23 v1(224.29,62.56) ; v1(223.02,62.56) J1.G24 ; v1(223.02,62.56) J1.F24 ; J2.C12 v1(327.06,77.8) ; v1(226.83,71.45) J1.D16 ; v1(226.83,71.45) J1.C17 v1(228.1,71.45) ; v1(226.83,71.45) J1.D17 ; v1(226.83,71.45) J1.C16 ; J1.D16 v1(226.83,72.72) J1.C15 ; J1.D16 v1(225.56,72.72) ; J1.D16 J1.E16 ; v1(221.75,30.81) J1.G49 ; v1(221.75,30.81) J1.H48 v1(221.75,32.08) ; v1(221.75,30.81) J1.H49 v1(221.75,29.54) ; J1.G49 v1(223.02,29.54) ; J1.G49 v1(223.02,30.81) ; J1.G49 v1(221.75,29.54) ; J2.H17 v1(319.44,71.45) ; J1.E32 v1(224.29,52.4) ; J1.E32 J1.D32 ; J1.E32 v1(224.29,51.13) ; v1(224.29,52.4) J1.F32 ; v1(224.29,52.4) J1.F31 v1(223.02,52.4) ; v1(224.29,52.4) J1.E31 ; J2.F36 J2.G36 ; J2.F36 v1(323.25,47.32) J2.E35 ; J2.G36 v1(320.71,46.05) J2.H37 v1(320.71,44.78) J2.G38 ; J2.H13 v1(319.44,76.53) ; v1(228.1,56.21) J1.C29 v1(226.83,56.21) ; v1(228.1,56.21) J1.C28 ; v1(228.1,56.21) J1.B28 ; J2.A49 v1(329.6,29.54) ; v1(221.75,57.48) J1.G27 v1(223.02,57.48) ; v1(221.75,57.48) J1.H28 v1(221.75,56.21) ; v1(221.75,57.48) J1.H27 v1(221.75,58.75) J1.H26 v1(221.75,60.02) J1.H25 v1(221.75,61.29) ; v1(221.75,57.48) J1.G28 ; J2.E27 v1(323.25,57.48) ; v1(224.29,62.56) J1.E24 ; v1(224.29,62.56) J1.F24 ; v1(224.29,62.56) J1.E23 ; J1.D32 v1(226.83,52.4) ; J1.D32 v1(226.83,51.13) ; v1(226.83,52.4) J1.C32 ; v1(226.83,52.4) J1.D31 ; v1(226.83,52.4) J1.C31 v1(228.1,52.4) ; J2.D37 v1(325.79,44.78) J2.C38 ; J2.D37 v1(325.79,46.05) J2.C36 ; v1(224.29,67.64) J1.E19 ; v1(224.29,67.64) J1.F19 v1(223.02,67.64) ; v1(224.29,67.64) J1.E20 ; v1(221.75,29.54) J1.G50 v1(223.02,29.54) ; v1(221.75,29.54) J1.H50 ; J1.F32 v1(223.02,51.13) ; J1.F32 v1(224.29,51.13) ; J1.F32 v1(223.02,52.4) ; J1.E19 J1.D19 ; J1.E19 v1(224.29,68.91) J1.E18 ; J1.D19 v1(226.83,68.91) J1.D18 ; J1.D19 v1(226.83,67.64) ; J2.E47 v1(323.25,33.35) J2.F46 ; J2.E47 J2.D47 ; v1(394.41,0.69) 394.82,0.28 U9.2 ; J2.H23 v1(319.44,63.83) ; J1.C33 v1(226.83,51.13) ; J1.C33 v1(226.83,49.86) J1.D34 ; J1.C33 v1(228.1,51.13) ; v1(226.83,51.13) J1.C32 ; v1(223.02,51.13) J1.F33 ; v1(223.02,51.13) J1.G32 ; v1(223.02,51.13) J1.G33 v1(221.75,51.13) ; C7.2 v1(385.27,10.62) ; J2.A9 v1(329.6,81.61) ; 221.75,67.64 J1.H20 v1(221.75,66.37) ; 221.75,67.64 J1.G20 ; 221.75,67.64 J1.H19 v1(221.75,68.91) J1.H18 v1(221.75,70.18) J1.H17 221.75,71.45 ; 221.75,67.64 J1.G19 v1(223.02,67.64) ; J2.C16 v1(327.06,72.72) ; J1.E24 v1(224.29,61.29) ; J1.E24 J1.D24 ; J2.C32 v1(325.79,52.4) J2.D31 ; J2.C32 v1(325.79,51.13) J2.D33 ; J2.C32 J2.B32 ; J2.A3 v1(329.6,89.23) ; J2.A3 v1(329.6,87.96) J2.A4 v1(329.6,86.69) J2.A5 v1(328.33,86.69) J2.B5 v1(327.06,86.69) J2.C5 ; J2.A3 v1(328.33,89.23) J2.B3 v1(327.06,89.23) J2.C3 v1(325.79,89.23) J2.D3 ; J2.D27 v1(325.79,57.48) ; J2.B44 v1(328.33,35.89) J2.A45 v1(328.33,34.62) J2.B46 ; J2.B44 J2.C44 ; J1.F3 v1(223.02,89.23) ; J2.A46 v1(329.6,33.35) ; v1(226.83,61.29) J1.D24 ; v1(226.83,61.29) J1.C24 ; v1(226.83,61.29) J1.D25 ; v1(226.83,61.29) J1.C25 v1(228.1,61.29) ; J1.D24 v1(226.83,62.56) ; J1.D18 v1(226.83,70.18) J1.D17 ; J1.D18 J1.E18 ; v1(228.1,71.45) J1.B17 v1(229.37,71.45) ; v1(228.1,71.45) J1.C16 ; v1(228.1,71.45) J1.B16 ; UG1.13 v1(223.44,-19.92) ; v1(228.1,30.81) J1.B48 ; v1(228.1,30.81) J1.B49 ; v1(228.1,30.81) J1.C48 ; v1(228.1,30.81) J1.C49 ; J1.B48 v1(229.37,30.81) ; J1.B48 v1(229.37,32.08) ; v1(226.83,57.48) J1.C27 v1(228.1,57.48) ; v1(226.83,57.48) J1.D28 ; v1(226.83,57.48) J1.C28 ; v1(226.83,57.48) J1.D27 ; U19.F5 v1(236.66,126.16) ; J2.H25 v1(319.44,61.29) ; J1.E17 v1(224.29,71.45) ; J1.E17 v1(224.29,70.18) J1.E18 ; J1.E17 J1.D17 ; v1(224.29,71.45) J1.E16 ; v1(224.29,71.45) J1.F16 ; v1(224.29,71.45) J1.F17 v1(223.02,71.45) ; J2.H16 v1(319.44,72.72) ; J2.F20 v1(321.98,67.64) ; v1(228.1,57.48) J1.B27 v1(229.37,57.48) ; v1(228.1,57.48) J1.C28 ; v1(228.1,57.48) J1.B28 ; v1(221.75,51.13) J1.G32 ; v1(221.75,51.13) J1.H33 v1(221.75,49.86) J1.H34 v1(221.75,48.59) J1.H35 v1(221.75,47.32) ; v1(221.75,51.13) J1.H32 v1(221.75,52.4) ; C13.2 v1(380.7,18.49) ; v1(357.4,49.05) 357.92,48.53 U20.8 ; J1.F49 v1(224.29,29.54) ; J1.F49 v1(223.02,30.81) ; J1.F49 v1(224.29,30.81) ; J1.F49 v1(223.02,29.54) ; v1(224.29,29.54) J1.F50 v1(223.02,29.54) ; v1(224.29,29.54) J1.E49 ; v1(224.29,29.54) J1.E50 J1.D50 v1(226.83,29.54) ; J1.C24 v1(228.1,61.29) ; J1.C24 v1(228.1,62.56) ; J1.C24 v1(226.83,62.56) ; J2.G22 v1(320.71,65.1) ; v1(225.56,72.72) J1.E15 v1(224.29,72.72) ; v1(225.56,72.72) J1.E16 ; v1(225.56,72.72) J1.D15 v1(226.83,73.99) ; J2.B38 v1(328.33,43.51) J2.A39 v1(328.33,42.24) J2.B40 ; J2.B38 J2.C38 ; J2.B38 v1(328.33,44.78) J2.A37 v1(328.33,46.05) J2.B36 ; J1.C47 v1(226.83,32.08) ; J1.C47 v1(226.83,33.35) ; v1(226.83,32.08) J1.D48 ; v1(226.83,32.08) J1.C48 ; v1(226.83,32.08) J1.D47 v1(226.83,33.35) ; J2.B46 v1(328.33,33.35) J2.A47 v1(328.33,32.08) J2.B48 ; J2.B46 J2.C46 ; 221.75,71.45 J1.G16 ; 221.75,71.45 J1.G17 v1(223.02,71.45) ; 221.75,71.45 J1.H16 221.75,72.72 ; J1.G16 v1(223.02,72.72) ; J1.G16 v1(223.02,71.45) ; J1.G16 221.75,72.72 ; U20.13 v1(356.37,39.61) ; J2.C18 v1(325.79,70.18) ; J2.D39 J2.E39 ; J2.D39 v1(325.79,42.24) J2.C40 ; J2.D39 v1(325.79,43.51) J2.C38 ; J2.E39 v1(323.25,42.24) J2.F40 ; J2.E39 v1(323.25,43.51) J2.F38 ; v1(228.1,51.13) J1.B33 v1(229.37,51.13) ; v1(228.1,51.13) J1.C32 ; v1(228.1,51.13) J1.B32 ; J2.D3 J2.E3 ; J2.D3 v1(325.79,87.96) J2.D4 ; J2.E3 v1(323.25,87.96) J2.E4 ; J2.B32 v1(328.33,51.13) J2.A33 v1(328.33,49.86) J2.B34 ; J2.B32 v1(328.33,52.4) J2.A31 v1(328.33,53.67) J2.B30 ; J2.H2 v1(319.44,90.5) ; J2.G6 v1(320.71,85.42) ; v1(221.75,52.4) J1.G32 ; v1(221.75,52.4) J1.G31 v1(223.02,52.4) ; v1(221.75,52.4) J1.H31 v1(221.75,53.67) J1.H30 v1(221.75,54.94) J1.H29 v1(221.75,56.21) ; J1.G32 v1(223.02,52.4) ; J2.D43 J2.E43 ; J2.D43 v1(325.79,37.16) J2.C44 ; J2.D43 v1(325.79,38.43) J2.C42 ; J2.E43 v1(323.25,38.43) J2.F42 ; J2.E43 v1(323.25,37.16) J2.F44 ; v1(224.29,66.37) J1.E20 ; v1(224.29,66.37) J1.E21 ; v1(229.37,51.13) J1.A32 v1(229.37,52.4) ; v1(229.37,51.13) J1.B32 ; v1(229.37,51.13) J1.A33 v1(229.37,49.86) J1.A34 v1(229.37,48.59) J1.A35 v1(229.37,47.32) ; J1.C28 v1(226.83,56.21) ; v1(226.83,33.35) J1.D46 ; COUT10.2 356.05,55.4 v1(355.4,56.05) ; v1(353.29,66.08) 353.44,65.92 Q5.2 ; J2.F14 v1(321.98,75.26) ; J1.A1 v1(230.64,91.77) ; v1(229.37,57.48) J1.A27 v1(229.37,58.75) J1.A26 v1(229.37,60.02) J1.A25 v1(229.37,61.29) ; v1(229.37,57.48) J1.B28 ; v1(229.37,73.99) J1.A15 v1(229.37,72.72) ; v1(229.37,73.99) J1.A14 ; v1(229.37,73.99) J1.B15 ; v1(229.37,73.99) J1.B14 v1(228.1,73.99) ; U19.C5 v1(232.85,126.16) ; J2.B22 v1(328.33,65.1) ; v1(228.1,61.29) J1.B25 v1(229.37,61.29) ; v1(228.1,61.29) J1.B24 ; v1(229.37,67.64) J1.A19 v1(229.37,68.91) J1.A18 v1(229.37,70.18) J1.A17 v1(229.37,71.45) ; J2.G30 v1(320.71,53.67) J2.H31 v1(320.71,52.4) J2.G32 ; J2.G30 J2.F30 ; J2.G30 v1(320.71,54.94) J2.H29 v1(320.71,56.21) J2.G28 J2.F28 v1(323.25,56.21) J2.E29 ; v1(223.02,71.45) J1.F16 ; v1(226.83,66.37) J1.C21 v1(228.1,66.37) ; v1(226.83,66.37) J1.D20 ; v1(226.83,66.37) J1.D21 ; v1(226.83,66.37) J1.C20 ; J2.H36 v1(319.44,46.05) ; J2.D29 v1(325.79,54.94) J2.C30 ; J2.D29 J2.E29 ; J2.D29 v1(325.79,56.21) J2.C28 J2.B28 v1(328.33,56.21) J2.A29 v1(328.33,54.94) J2.B30 ; v1(229.37,46.05) J1.A36 v1(229.37,47.32) ; v1(229.37,46.05) J1.B37 v1(228.1,46.05) ; J1.F33 v1(224.29,49.86) ; J1.F33 v1(224.29,51.13) ; J2.A32 v1(329.6,51.13) ; J1.F28 v1(224.29,57.48) ; J1.F28 v1(223.02,56.21) ; J1.F28 v1(223.02,57.48) ; J1.F28 v1(224.29,56.21) ; v1(224.29,57.48) J1.E28 ; v1(224.29,57.48) J1.F27 v1(223.02,57.48) ; v1(224.29,57.48) J1.E27 ; J2.C5 v1(325.79,85.42) J2.D6 J2.E6 v1(323.25,85.42) J2.F5 ; J2.C5 v1(325.79,86.69) J2.D4 ; Q6.2 v1(353.24,60.79) ; v1(226.83,38.43) J1.C43 ; v1(226.83,38.43) J1.D43 v1(226.83,37.16) ; v1(226.83,38.43) J1.D42 ; J1.C43 v1(228.1,37.16) ; J1.C43 v1(226.83,37.16) ; C37.2 v1(348.93,89.48) ; D1.1 v1(397.99,11.86) ; R85.1 v1(394.75,-2.67) ; J2.C50 v1(327.06,28.27) ; v1(221.75,61.29) J1.H24 v1(221.75,62.56) ; v1(221.75,61.29) J1.G25 v1(223.02,61.29) ; v1(221.75,61.29) J1.G24 ; v1(223.02,73.99) J1.F15 ; v1(223.02,73.99) J1.G15 ; v1(223.02,73.99) J1.F14 ; J1.F15 v1(223.02,72.72) ; J1.F15 v1(224.29,72.72) ; J1.G4 v1(221.75,87.96) ; J2.A14 v1(329.6,75.26) ; J1.B44 v1(229.37,35.89) ; J1.B44 v1(228.1,37.16) ; J1.B44 v1(228.1,35.89) ; J1.B15 v1(229.37,72.72) ; J1.B15 v1(228.1,73.99) ; J1.B15 v1(228.1,72.72) ; v1(229.37,72.72) J1.B16 ; v1(229.37,72.72) J1.A16 v1(229.37,71.45) ; v1(226.83,67.64) J1.D20 ; v1(226.83,67.64) J1.C20 ; J1.D20 J1.E20 ; 394.31,22.04 v1(393.01,22.04) ; v1(228.1,46.05) J1.C37 ; v1(228.1,46.05) J1.C36 ; J1.C37 v1(226.83,44.78) J1.D38 ; J1.C37 v1(226.83,46.05) ; v1(226.83,48.59) J1.C35 ; v1(226.83,48.59) J1.D34 ; v1(226.83,48.59) J1.D35 v1(226.83,47.32) ; J1.C35 v1(226.83,47.32) ; v1(221.75,66.37) J1.H21 221.75,65.1 J1.H22 v1(221.75,63.83) J1.H23 v1(221.75,62.56) ; v1(221.75,66.37) J1.G20 ; J1.F47 v1(224.29,33.35) J1.E46 ; J1.F47 v1(224.29,32.08) ; C107.2 v1(244.33,132.93) ; J2.D15 v1(324.52,72.72) ; J2.C40 v1(325.79,40.97) J2.D41 ; J2.C40 J2.B40 ; U19.K3 v1(243.01,122.35) ; v1(228.1,40.97) J1.C40 ; v1(228.1,40.97) J1.B41 v1(229.37,40.97) ; v1(228.1,40.97) J1.B40 ; v1(228.1,40.97) J1.C41 ; J1.C40 v1(228.1,42.24) ; J1.C40 v1(226.83,42.24) ; v1(221.75,46.05) J1.H36 v1(221.75,47.32) ; v1(221.75,46.05) J1.G36 ; v1(221.75,46.05) J1.G37 v1(223.02,46.05) ; v1(221.75,46.05) J1.H37 v1(221.75,44.78) J1.H38 v1(221.75,43.51) J1.H39 v1(221.75,42.24) ; J2.G24 v1(320.71,61.29) ; v1(229.37,61.29) J1.A24 v1(229.37,62.56) ; v1(229.37,61.29) J1.B24 ; J2.E11 v1(324.52,77.8) ; J2.F38 J2.G38 ; J2.G38 v1(320.71,43.51) J2.H39 v1(320.71,42.24) J2.G40 ; J1.G15 v1(223.02,72.72) ; J1.G15 221.75,72.72 ; U20.14 v1(357.92,39.62) ; J2.D11 v1(325.79,79.07) ; J1.C15 v1(228.1,72.72) ; J1.C15 v1(228.1,73.99) ; J1.C15 v1(226.83,73.99) ; v1(228.1,72.72) J1.B16 ; v1(228.1,72.72) J1.C16 ; v1(228.1,29.54) J1.C49 ; v1(228.1,29.54) J1.C50 v1(226.83,29.54) ; v1(228.1,29.54) J1.B50 v1(229.37,29.54) ; v1(228.1,29.54) J1.B49 ; J1.C49 v1(226.83,29.54) ; J1.C49 v1(226.83,30.81) ; J1.G3 v1(221.75,89.23) ; J1.H1 v1(220.48,91.77) ; J1.H5 v1(220.48,86.69) ; J2.H46 v1(319.44,33.35) ; v1(229.37,30.81) J1.A48 v1(229.37,32.08) ; v1(229.37,30.81) J1.B49 ; v1(229.37,30.81) J1.A49 v1(229.37,29.54) ; U6.2 v1(385.93,14.96) ; J2.D33 v1(325.79,49.86) J2.C34 ; J2.D33 J2.E33 ; J2.E50 v1(323.25,28.27) ; C38.2 v1(350.88,87.22) ; C91.2 v1(391.03,34.06) ; U21.13 v1(307.4,120.7) ; J2.E25 v1(324.52,61.29) ; J1.D30 v1(226.83,53.67) J1.D31 ; J1.D30 v1(226.83,54.94) J1.D29 ; J1.D30 J1.E30 ; J1.E16 v1(224.29,72.72) ; J2.D41 v1(325.79,39.7) J2.C42 ; J2.D41 J2.E41 ; v1(229.37,32.08) J1.A47 v1(229.37,33.35) J1.A46 v1(229.37,34.62) J1.A45 v1(229.37,35.89) ; J2.D31 J2.E31 ; J2.D31 v1(325.79,53.67) J2.C30 ; J2.E31 v1(323.25,53.67) J2.F30 ; J2.E31 v1(323.25,52.4) J2.F32 ; v1(224.29,46.05) J1.E37 v1(224.29,44.78) ; v1(224.29,46.05) J1.F37 ; v1(224.29,46.05) J1.F36 ; v1(224.29,46.05) J1.E36 ; J1.F24 v1(223.02,61.29) ; J1.F24 v1(224.29,61.29) ; v1(223.02,61.29) J1.G24 ; v1(223.02,61.29) J1.F25 v1(224.29,61.29) ; J2.A8 v1(329.6,82.88) ; J2.A15 v1(329.6,73.99) ; v1(224.29,44.78) J1.E38 ; v1(224.29,44.78) J1.F37 ; J1.C32 v1(228.1,52.4) ; J2.F40 v1(323.25,40.97) J2.E41 ; J2.F40 J2.G40 ; C106.2 v1(240.46,132.93) ; v1(223.02,56.21) J1.G28 ; v1(223.02,56.21) J1.G29 v1(221.75,56.21) ; v1(223.02,56.21) J1.F29 v1(224.29,56.21) ; J1.G28 v1(221.75,56.21) ; J1.G28 v1(223.02,57.48) ; J1.D25 v1(226.83,60.02) J1.D26 ; J1.D25 J1.E25 ; v1(228.1,42.24) J1.C39 ; v1(228.1,42.24) J1.B40 ; v1(224.29,49.86) J1.E33 v1(224.29,51.13) ; v1(224.29,49.86) J1.E34 ; v1(223.02,37.16) J1.F44 ; v1(223.02,37.16) J1.G43 v1(221.75,37.16) ; v1(223.02,37.16) J1.F43 ; J1.F44 v1(224.29,37.16) ; J1.F44 v1(224.29,35.89) ; J1.F44 v1(223.02,35.89) ; v1(223.02,46.05) J1.G36 ; v1(223.02,46.05) J1.F37 ; v1(223.02,46.05) J1.F36 ; J1.G36 v1(223.02,47.32) ; J1.G36 v1(221.75,47.32) ; U21.3 v1(307.4,115.2) ; v1(228.1,73.99) J1.C14 v1(226.83,73.99) ; J2.F32 J2.G32 ; J2.F32 v1(323.25,51.13) J2.E33 ; U19.D5 v1(234.12,126.16) ; R40.2 v1(350.88,79.26) ; C18.2 v1(377.9,18.49) ; C2.2 v1(383.49,18.49) ; J1.D26 v1(226.83,58.75) J1.D27 ; J1.D26 J1.E26 ; v1(221.75,42.24) J1.H40 v1(221.75,40.97) ; v1(221.75,42.24) J1.G40 ; J2.C36 J2.B36 ; J2.C36 v1(325.79,47.32) J2.D35 ; J2.B36 v1(328.33,47.32) J2.A35 v1(328.33,48.59) J2.B34 ; J2.F42 v1(323.25,39.7) J2.E41 ; J2.F42 J2.G42 ; J1.B32 v1(228.1,52.4) ; J1.B32 v1(229.37,52.4) ; J1.D5 v1(226.83,86.69) ; v1(224.29,37.16) J1.F43 ; v1(224.29,37.16) J1.E44 ; J2.H40 v1(319.44,40.97) ; J2.D35 J2.E35 ; J2.D35 v1(325.79,48.59) J2.C34 ; J2.E35 v1(323.25,48.59) J2.F34 ; J2.C46 v1(325.79,34.62) J2.D45 ; J2.C46 v1(325.79,33.35) J2.D47 ; v1(224.29,61.29) J1.E25 ; J1.E25 v1(224.29,60.02) J1.E26 ; J2.D45 J2.E45 ; J2.D45 v1(325.79,35.89) J2.C44 ; J2.E45 v1(323.25,34.62) J2.F46 ; J2.E45 v1(323.25,35.89) J2.F44 ; J1.E22 v1(224.29,65.1) J1.E21 ; J1.E22 v1(224.29,63.83) J1.E23 ; J1.E22 J1.D22 ; J2.H8 v1(319.44,82.88) ; C4.2 v1(391.87,18.49) ; J1.D4 v1(226.83,87.96) ; v1(224.29,35.89) J1.E44 ; v1(224.29,35.89) J1.E45 v1(224.29,34.62) ; v1(224.29,35.89) J1.F45 ; J1.E44 J1.D44 ; J1.E5 v1(224.29,86.69) ; v1(221.75,47.32) J1.G35 v1(223.02,47.32) ; J1.E42 J1.D42 ; J1.E42 v1(224.29,38.43) J1.F43 ; J1.E42 v1(224.29,39.7) ; J1.D42 v1(226.83,39.7) J1.C41 ; J2.G12 v1(320.71,77.8) ; J2.D4 J2.E4 ; J2.A7 v1(329.6,84.15) ; J2.C10 v1(327.06,80.34) ; J2.G46 v1(320.71,34.62) J2.H45 v1(320.71,35.89) J2.G44 ; J2.G46 J2.F46 ; J2.F44 J2.G44 ; J2.A28 v1(329.6,56.21) ; J1.C20 v1(228.1,66.37) ; J2.B18 v1(328.33,70.18) ; J2.A50 v1(329.6,28.27) ; J2.F12 v1(321.98,77.8) ; v1(228.1,52.4) J1.B31 v1(229.37,52.4) ; U19.H1 v1(240.47,119.81) ; C1.2 v1(382.48,10.62) ; J2.G44 v1(320.71,37.16) J2.H43 v1(320.71,38.43) J2.G42 ; v1(221.75,40.97) J1.H41 v1(221.75,39.7) J1.H42 v1(221.75,38.43) J1.H43 v1(221.75,37.16) ; v1(221.75,40.97) J1.G40 ; v1(221.75,40.97) J1.G41 v1(223.02,40.97) ; C14.2 v1(392.86,-8.99) ; v1(223.02,67.64) J1.G20 ; J1.C44 v1(226.83,35.89) ; J1.C44 v1(226.83,37.16) ; J1.C44 v1(228.1,37.16) ; J1.C44 v1(228.1,35.89) ; v1(226.83,35.89) J1.C45 ; v1(226.83,35.89) J1.D44 ; v1(224.29,39.7) J1.E41 v1(224.29,40.97) ; v1(224.29,39.7) J1.F41 ; J1.D46 J1.E46 ; J1.D46 v1(226.83,34.62) J1.C45 ; J2.H32 v1(319.44,51.13) ; v1(226.83,42.24) J1.D39 v1(226.83,43.51) ; v1(226.83,42.24) J1.C39 ; v1(223.02,35.89) J1.F45 ; J1.F45 v1(224.29,34.62) ; J2.A20 v1(329.6,67.64) ; J2.G10 v1(320.71,80.34) ; J1.D21 v1(226.83,65.1) J1.D22 ; J1.D21 J1.E21 ; J2.H7 v1(319.44,84.15) ; J1.C45 v1(228.1,35.89) ; J1.E46 v1(224.29,34.62) ; C17.2 v1(376.89,10.62) ; J1.B16 v1(229.37,71.45) ; J2.F5 v1(323.25,86.69) J2.E4 ; J1.B3 v1(229.37,89.23) ; J2.G40 v1(320.71,40.97) J2.H41 v1(320.71,39.7) J2.G42 ; C33.2 v1(348.93,79.17) ; C53.2 v1(385.87,58.03) ; U19.E1 v1(235.39,119.81) ; J2.B16 v1(328.33,72.72) ; R4.1 v1(392.89,2.11) ; J2.F24 v1(321.98,61.29) ; v1(223.02,40.97) J1.G40 ; v1(223.02,40.97) J1.F41 ; v1(356.4,49.05) 356.37,49.01 U20.9 ; J1.C5 v1(228.1,86.69) ; J2.A30 v1(329.6,53.67) ; J2.C34 J2.B34 ; J2.B48 v1(328.33,30.81) ; J1.B49 v1(229.37,29.54) ; v1(229.37,29.54) J1.A50 ; v1(223.02,47.32) J1.F35 ; v1(223.02,47.32) J1.F36 ; J1.F35 v1(224.29,47.32) ; J1.F35 v1(224.29,48.59) J1.E34 ; v1(224.29,30.81) J1.E49 ; v1(224.29,30.81) J1.E48 ; J2.H26 v1(319.44,58.75) ; v1(383.08,44.7) v1(383.08,45.77) 383.08,47.08 v1(383.03,47.13) ; J2.H48 v1(319.44,30.81) ; U20.3 v1(362.7,42.96) ; J1.F16 v1(223.02,72.72) ; J1.D31 J1.E31 ; v1(229.37,62.56) J1.B23 v1(228.1,62.56) ; v1(229.37,62.56) J1.B24 ; J2.B26 v1(328.33,58.75) ; J2.F26 v1(321.98,58.75) ; J1.A5 v1(230.64,86.69) ; J1.F39 v1(224.29,43.51) J1.E38 ; J1.F39 v1(224.29,42.24) ; J1.E38 J1.D38 ; J2.E17 v1(323.25,71.45) ; J2.A17 v1(329.6,71.45) ; R73.2 v1(382.32,28.24) ; J1.F5 v1(223.02,86.69) ; v1(228.1,35.89) J1.B45 v1(229.37,35.89) ; J1.C48 v1(226.83,30.81) ; v1(226.83,30.81) J1.D48 ; v1(226.83,30.81) J1.D49 ; J1.G24 v1(221.75,62.56) ; J2.E29 v1(323.25,54.94) J2.F30 ; J2.H50 v1(319.44,28.27) ; J1.D34 J1.E34 ; J1.D3 v1(226.83,89.23) ; J1.D48 J1.E48 ; J1.B4 v1(229.37,87.96) ; J1.E29 J1.D29 ; J1.E29 v1(224.29,56.21) ; J1.E29 v1(224.29,54.94) J1.E30 ; J1.D29 v1(226.83,56.21) ; R87.1 v1(357.91,72.67) ; v1(383.03,47.13) X1.2 ; v1(383.03,47.13) 383.03,47.98 383.39,48.34 v1(384.96,48.34) 387.25,48.34 v1(387.46,48.12) 387.8,47.79 v1(387.8,46.89) ; J2.A40 v1(329.6,40.97) ; J1.E27 v1(224.29,58.75) J1.E26 ; J1.E27 J1.D27 ; J2.C14 v1(325.79,73.99) ; J1.F36 v1(224.29,47.32) ; v1(224.29,47.32) J1.E36 ; J2.C24 v1(325.79,62.56) ; J1.F4 v1(223.02,87.96) ; J2.C30 J2.B30 ; J1.E28 v1(224.29,56.21) ; J1.E28 J1.D28 ; U7.2 v1(380.34,14.96) ; J1.D44 v1(226.83,37.16) ; J2.G50 v1(320.71,28.27) ; J1.E4 v1(224.29,87.96) ; J2.C6 v1(327.06,85.42) ; v1(226.83,62.56) J1.C23 v1(228.1,62.56) ; R69.1 v1(385.6,44.27) ; 394.81,32.14 v1(396.74,32.14) ; J1.C36 v1(226.83,46.05) ; J1.C36 v1(226.83,47.32) ; J2.F22 v1(321.98,65.1) ; J1.E3 v1(224.29,89.23) ; J2.F10 v1(321.98,80.34) ; J2.C26 v1(327.06,58.75) ; J2.B14 v1(328.33,75.26) ; v1(226.83,47.32) J1.D36 ; J2.F34 v1(323.25,49.86) J2.E33 ; U19.J5 v1(241.74,126.16) ; J2.D21 v1(325.79,65.1) ; U19.G3 v1(239.2,122.35) ; J2.H21 v1(319.44,66.37) ; D9.1 v1(389.59,42.34) ; UG1.10 v1(225.64,-4.73) ; J2.B8 v1(328.33,82.88) ; J2.G26 v1(320.71,58.75) ; v1(228.1,62.56) J1.B24 ; J2.B24 v1(327.06,62.56) ; J2.F50 v1(321.98,28.27) ; v1(226.83,43.51) J1.D38 ; v1(226.83,43.51) J1.C39 ; U19.H2 v1(240.47,121.08) ; J1.E36 J1.D36 ; J1.D36 v1(226.83,46.05) ; J1.D49 v1(226.83,29.54) ; J1.D49 J1.E49 ; J2.A21 v1(329.6,66.37) ; J1.E48 v1(224.29,32.08) ; J2.H30 v1(319.44,53.67) ; J1.H3 v1(220.48,89.23) ; J1.E30 v1(224.29,53.67) J1.E31 ; v1(226.83,56.21) J1.D28 ; J2.H6 v1(319.44,85.42) ; U5.2 v1(388.72,14.96) ; J2.C49 v1(327.06,29.54) ; U19.F7 v1(236.66,128.7) ; J1.B40 v1(229.37,40.97) ; U21.10 v1(311.95,120.7) U21.9 ; J2.E15 v1(323.25,72.72) ; J2.B20 v1(328.33,67.64) ; C5.2 v1(388.06,10.62) ; J2.G18 v1(320.71,70.18) ; U19.D3 v1(234.12,122.35) ; J2.F16 v1(321.98,72.72) ; UG1.12 v1(223.44,-4.73) ; J2.A22 v1(329.6,65.1) ; J2.A18 v1(329.6,70.18) ; J2.D9 v1(325.79,81.61) ; v1(224.29,40.97) J1.F41 ; v1(224.29,40.97) J1.E40 ; J2.A38 v1(329.6,43.51) ; U17.3 v1(384.99,29.51) ; J2.B50 v1(328.33,28.27) ; UG1.24 v1(237.44,-19.92) ; J2.H19 v1(319.44,68.91) ; J2.F8 v1(321.98,82.88) ; C34.2 v1(351.79,82.27) ; J2.G20 v1(320.71,67.64) ; J2.A1 v1(329.6,91.77) ; J2.H15 v1(319.44,73.99) ; J2.A16 v1(329.6,72.72) ; D2.1 v1(396.09,4.38) ; J2.H38 v1(319.44,43.51) ; U19.E2 v1(235.39,121.08) ; J2.H27 v1(319.44,57.48) ; J2.H44 v1(319.44,35.89) ; U19.A5 v1(230.31,126.16) ; U19.D4 v1(234.12,124.89) ; C12.2 v1(379.68,10.62) ; J1.E40 v1(224.29,42.24) ; J2.A2 v1(329.6,90.5) ; J2.B49 v1(328.33,29.54) ; J2.A23 v1(329.6,63.83) ; J2.G14 v1(320.71,75.26) ; C11.2 v1(389.15,-8.99) ; U6.5 v1(385.93,17.12) ; J1.B5 v1(229.37,86.69) ; D10.1 v1(387.69,33.26) ; J2.A44 v1(329.6,35.89) ; J2.F18 v1(321.98,70.18) ; R84.1 v1(394.75,-5.23) ; J1.C4 v1(228.1,87.96) ; J2.A13 v1(329.6,76.53) ; J2.A11 v1(329.6,79.07) ; C8.2 v1(386.29,18.49) ; J2.A27 v1(329.6,57.48) ; J2.E7 v1(323.25,84.15) ; R86.1 v1(357.91,69.03) ; J2.G16 v1(320.71,72.72) ; 220.14,113.67 COUT2.2 ; C6.2 v1(389.08,18.49) ; J2.D19 v1(325.79,67.64) ; J1.H2 v1(220.48,90.5) ; J4.B1 v1(401.99,11.17) ; U19.K4 v1(243.01,124.89) ; J2.G8 v1(320.71,82.88) ; U19.G4 v1(239.2,124.89) ; U19.L1 v1(244.28,119.81) ; J2.A10 v1(329.6,80.34) ; J2.G49 v1(320.71,29.54) ; J2.A12 v1(329.6,77.8) ; J2.H28 v1(319.44,56.21) ; J1.A2 v1(230.64,90.5) ; J2.E19 v1(323.25,68.91) ; 404.41,33.03 v1(402.47,33.03) ; J2.C22 v1(327.06,65.1) ; J1.A4 v1(230.64,87.96) ; J2.A6 v1(329.6,85.42) ; J2.F6 v1(321.98,85.42) ; J2.D50 v1(325.79,28.27) ; J2.A24 v1(329.6,62.56) ; J2.B6 v1(328.33,85.42) ; v1(323.25,29.54) J2.E49 ; J2.H12 v1(319.44,77.8) ; J2.C20 v1(327.06,67.64) ; J2.H49 v1(319.44,29.54) ; J2.C8 v1(327.06,82.88) ; U10.5 v1(377.8,-3.4) ; U3.2 v1(383.13,14.96) ; J1.H4 v1(220.48,87.96) ; J2.F49 v1(321.98,29.54) ; J2.H14 v1(319.44,75.26) ; J2.H34 v1(319.44,48.59) ; C105.2 v1(233.82,132.91) ; J1.A3 v1(230.64,89.23) ; J2.A48 v1(329.6,30.81) ; U20.10 v1(355.47,45.36) ; J2.A26 v1(329.6,58.75) ; U8.2 v1(377.55,14.96) ; J1.C3 v1(228.1,89.23) ; J2.A36 v1(329.6,46.05) ; J2.H22 v1(319.44,65.1) ; D3.2 v1(398.98,15.67) ; J2.H11 v1(319.44,79.07) ; J2.D17 v1(324.52,70.18) ; J2.D7 v1(325.79,84.15) ; J2.B12 v1(328.33,77.8) ; U19.G5 v1(239.2,126.16) ; J2.H24 v1(319.44,62.56) ; U4.2 v1(391.52,14.96) ; J2.A19 v1(329.6,68.91) ; J2.B10 v1(328.33,80.34) ; U19.B2 v1(231.58,121.08) ; U19.A4 v1(230.31,124.89) ; J2.E13 v1(323.25,76.53) ; J2.A25 v1(329.84,60.66) ; J2.H1 v1(319.44,91.77) ; J2.A42 v1(329.6,38.43) ; Q7.2 v1(353.19,55.66) ; U21.14 v1(307.4,119.15) ; U8.5 v1(377.55,17.12) ; 394.81,17.54 v1(396.74,17.54) ; J2.E9 v1(323.25,81.61) ; U19.L2 v1(244.28,121.08) ; J2.H9 v1(319.44,81.61) ; J2.H20 v1(319.44,67.64) ; J4.B12 v1(401.99,5.07) ; 404.41,17.54 v1(402.47,17.54) ; Y7.3 v1(343.27,39.92) ; J2.D13 v1(324.52,76.53) ; J2.E23 v1(323.25,63.83) ; J2.A34 v1(329.6,48.59) ; J2.H10 v1(319.44,80.34) ; J2.H18 v1(319.44,70.18) ; U19.B1 v1(231.58,119.81) ; J2.D23 v1(325.79,63.83) ; U21.8 v1(314.5,119.15)
  ART10 w0.135: 386.2,23.64 386.65,23.19 386.65,21.13 387.52,20.25 392.33,20.25 393.01,20.94 ; 393.01,23.14 393.01,24.73 391.83,25.92 387.48,25.92 386.2,24.64
  BOTTOM w0.381: C85.2 v1(320.62,3.56) ; CL18.1 382,56.56 v1(381.6,56.15) 381.04,56.71 R48.1 ; R15.2 v1(404.72,9.98) ; v1(377.99,61.74) 377.85,61.61 CL9.1 CL7.1 CL8.1 377.1,58.79 v1(377.03,58.72) ; R49.2 v1(403.75,52.12) ; C98.2 387.27,46.4 FB13.1 387.7,46.79 v1(387.8,46.89) ; R50.2 v1(403.75,75.4) ; v1(231.42,-21.74) 231.75,-22.07 CG1.2 ; v1(342.54,33.11) C288.2 C289.2 ; C103.2 v1(378.96,35.58) ; C94.2 v1(385.1,41.8) ; COUT5.2 236.12,129.97 v1(236.65,130.51) ; C78.2 v1(347.13,31.54) ; R13.2 399.15,7.71 398.56,7.12 v1(397.9,7.12) ; C81.2 v1(320.45,-9.25) ; v1(386.18,5.74) 387.02,6.58 C21.2 ; R185.2 v1(371.02,128.42) ; C86.2 v1(320.62,4.72) ; 343.38,23.39 342.7,23.39 ; 342.7,23.39 342.34,23.75 ; 342.7,23.39 342.34,23.04 ; CL12.1 379.5,62.71 379.19,63.02 ; v1(346.49,81.76) 346.99,82.26 C32.2 ; v1(379.19,65.56) 378.68,66.07 CL17.1 ; C80.2 v1(320.45,-10.44) ; v1(380.4,59.05) CL11.1
  BOTTOM w0.508: CAB76.1 v1(255.34,-23.52) ; v1(365.4,90.35) C39.2 v1(363.87,89.17) ; C30.2 v1(380.76,-5.35) ; C27.2 v1(390.19,-2.26) ; D14.1 v1(208.89,-24.87) ; C35.2 363.55,79.96 v1(363.55,79.46) ; C36.2 361.89,82.86 v1(361.61,83.13) ; 369.2,44.71 368.65,44.16 R96.2 ; v1(384.08,9.2) 383.87,8.99 C19.2 ; C40.2 v1(367.08,88.95) ; v1(378.99,0.61) 378.76,0.38 C20.2 ; C16.2 397.56,12.29 v1(397.99,11.86) ; RP2.2 v1(236.66,128.7) ; CG2.2 v1(231.32,-7.63) ; D16.1 v1(221.05,-22.97) ; v1(382.08,-1.47) 382.47,-1.87 C26.2 ; R92.2 v1(261.02,-24.03) ; v1(386.18,5.74) 386.05,5.87 C22.2 ; C29.2 v1(395.33,0.69) ; R94.2 v1(250.98,-23.47) ; C24.2 v1(394.41,0.69) ; CAB73.1 v1(265.35,-23.71) ; CAB75.1 v1(258.46,-23.68) ; CG3.2 v1(230.3,-7.63) ; R90.2 v1(267.92,-24.06) ; v1(386.18,1.93) 386.36,1.75 C10.2 ; v1(382.37,5.74) 382.26,5.86 C28.2
  vias: v1(154.61,141.65) v1(154.67,144.99) v1(154.71,137.72) v1(154.71,126.57) v1(154.71,116.57) v1(154.71,106.57) v1(154.71,96.57) v1(154.71,86.57) v1(154.71,76.57) v1(154.71,66.57) v1(154.71,56.57) v1(154.71,46.57) v1(154.71,36.57) v1(154.71,26.57) v1(154.71,16.57) v1(154.71,6.57) v1(154.71,-3.43) v1(154.71,-13.43) v1(154.71,-23.43) v1(154.7,-25.51) v1(154.7,-27.54) v1(154.7,-29.58) v1(154.7,-31.61) v1(154.7,-33.64) v1(154.94,132.13) v1(154.94,122.13) v1(154.94,112.13) v1(154.94,102.13) v1(154.94,92.13) v1(154.94,82.13) v1(154.94,72.13) v1(154.94,62.13) v1(154.94,52.13) v1(154.94,42.13) v1(154.94,32.13) v1(154.94,22.13) v1(154.94,12.13) v1(154.94,2.13) v1(154.94,-7.87) v1(154.94,-17.87) v1(155.91,136.58) v1(155.83,133.35) v1(155.83,130.96) v1(155.91,127.71) v1(155.83,123.35) v1(155.83,120.96) v1(155.91,117.71) v1(155.83,113.35) v1(155.83,110.96) v1(155.91,107.71) v1(155.83,103.35) v1(155.83,100.96) v1(155.91,97.71) v1(155.83,93.35) v1(155.83,90.96) v1(155.91,87.71) v1(155.83,83.35) v1(155.83,80.96) v1(155.91,77.71) v1(155.83,73.35) v1(155.83,70.96) v1(155.91,67.71) v1(155.83,63.35) v1(155.83,60.96) v1(155.91,57.71) v1(155.83,53.35) v1(155.83,50.96) v1(155.91,47.71) v1(155.83,43.35) v1(155.83,40.96) v1(155.91,37.71) v1(155.83,33.35) v1(155.83,30.96) v1(155.91,27.71) v1(155.83,23.35) v1(155.83,20.96) v1(155.91,17.71) v1(155.83,13.35) v1(155.83,10.96) v1(155.91,7.71) v1(155.83,3.35) v1(155.83,0.96) v1(155.91,-2.29) v1(155.83,-6.65) v1(155.83,-9.04) v1(155.91,-12.29) v1(155.83,-16.65) v1(155.83,-19.04) v1(155.91,-22.29) v1(156.54,137.72) v1(156.54,126.57) v1(156.54,116.57) v1(156.54,106.57) v1(156.54,96.57) v1(156.54,86.57) v1(156.54,76.57) v1(156.54,66.57) v1(156.54,56.57) v1(156.54,46.57) v1(156.54,36.57) v1(156.54,26.57) v1(156.54,16.57) v1(156.54,6.57) v1(156.54,-3.43) v1(156.54,-13.43) v1(156.54,-23.43) v1(156.7,144.99) v1(156.77,134.26) v1(156.75,130.03) v1(156.77,124.26) v1(156.75,120.03) v1(156.77,114.26) v1(156.75,110.03) v1(156.77,104.26) v1(156.75,100.03) v1(156.77,94.26) v1(156.75,90.03) v1(156.77,84.26) v1(156.75,80.03) v1(156.77,74.26) v1(156.75,70.03) v1(156.77,64.26) v1(156.75,60.03) v1(156.77,54.26) v1(156.75,50.03) v1(156.77,44.26) v1(156.75,40.03) v1(156.77,34.26) v1(156.75,30.03) v1(156.77,24.26) v1(156.75,20.03) v1(156.77,14.26) v1(156.75,10.03) v1(156.77,4.26) v1(156.75,0.03) v1(156.77,-5.74) v1(156.75,-9.97) v1(156.77,-15.74) v1(156.75,-19.97) v1(156.92,-26.26) v1(157.1,135.43) v1(157.1,128.86) v1(157.1,125.43) v1(157.1,118.86) v1(157.1,115.43) v1(157.1,108.86) v1(157.1,105.43) v1(157.1,98.86) v1(157.1,95.43) v1(157.1,88.86) v1(157.1,85.43) v1(157.1,78.86) v1(157.1,75.43) v1(157.1,68.86) v1(157.1,65.43) v1(157.1,58.86) v1(157.1,55.43) v1(157.1,48.86) v1(157.1,45.43) v1(157.1,38.86) v1(157.1,35.43) v1(157.1,28.86) v1(157.1,25.43) v1(157.1,18.86) v1(157.1,15.43) v1(157.1,8.86) v1(157.1,5.43) v1(157.1,-1.14) v1(157.1,-4.57) v1(157.1,-11.14) v1(157.1,-14.57) v1(157.1,-21.14) v1(157.73,136.58) v1(157.73,127.71) v1(157.73,117.71) v1(157.73,107.71) v1(157.73,97.71) v1(157.73,87.71) v1(157.73,77.71) v1(157.73,67.71) v1(157.73,57.71) v1(157.73,47.71) v1(157.73,37.71) v1(157.73,27.71) v1(157.73,17.71) v1(157.73,7.71) v1(157.73,-2.29) v1(157.73,-12.29) v1(157.73,-22.29) v1(158.24,69.97) v1(158.37,137.72) v1(158.37,126.57) v1(158.37,116.57) v1(158.37,106.57) v1(158.37,96.57) v1(158.37,86.57) v1(158.37,76.57) v1(158.37,66.57) v1(158.37,56.57) v1(158.37,46.57) v1(158.37,36.57) v1(158.37,26.57) v1(158.37,16.57) v1(158.37,6.57) v1(158.37,-3.43) v1(158.37,-13.43) v1(158.37,-23.43) v1(158.93,135.43) v1(158.93,128.86) v1(158.93,125.43) v1(158.93,118.86) v1(158.93,115.43) v1(158.93,108.86) v1(158.93,105.43) v1(158.93,98.86) v1(158.93,95.43) v1(158.93,88.86) v1(158.93,85.43) v1(158.93,78.86) v1(158.93,75.43) v1(158.93,68.86) v1(158.93,65.43) v1(158.93,58.86) v1(158.93,55.43) v1(158.93,48.86) v1(158.93,45.43) v1(158.93,38.86) v1(158.93,35.43) v1(158.93,28.86) v1(158.93,25.43) v1(158.93,18.86) v1(158.93,15.43) v1(158.93,8.86) v1(158.93,5.43) v1(158.93,-1.14) v1(158.93,-4.57) v1(158.93,-11.14) v1(158.93,-14.57) v1(158.93,-21.14) v1(159.16,134.26) v1(159.14,130.03) v1(159.16,124.26) v1(159.14,120.03) v1(159.16,114.26) v1(159.14,110.03) v1(159.16,104.26) v1(159.14,100.03) v1(159.16,94.26) v1(159.14,90.03) v1(159.16,84.26) v1(159.14,80.03) v1(159.16,74.26) v1(159.14,70.03) v1(159.16,64.26) v1(159.14,60.03) v1(159.16,54.26) v1(159.14,50.03) v1(159.16,44.26) v1(159.14,40.03) v1(159.16,34.26) v1(159.14,30.03) v1(159.16,24.26) v1(159.14,20.03) v1(159.16,14.26) v1(159.14,10.03) v1(159.16,4.26) v1(159.14,0.03) v1(159.16,-5.74) v1(159.14,-9.97) v1(159.16,-15.74) v1(159.14,-19.97) v1(159.56,136.58) v1(159.56,127.71) v1(159.56,117.71) v1(159.56,107.71) v1(159.56,97.71) v1(159.56,87.71) v1(159.56,77.71) v1(159.56,67.71) v1(159.56,57.71) v1(159.56,47.71) v1(159.56,37.71) v1(159.56,27.71) v1(159.56,17.71) v1(159.56,7.71) v1(159.56,-2.29) v1(159.56,-12.29) v1(159.56,-22.29) v1(160.07,133.33) v1(160.07,130.94) v1(160.07,123.33) v1(160.07,120.94) v1(160.07,113.33) v1(160.07,110.94) v1(160.07,103.33) v1(160.07,100.94) v1(160.07,93.33) v1(160.07,90.94) v1(160.07,83.33) v1(160.07,80.94) v1(160.07,73.33) v1(160.07,70.94) v1(160.07,63.33) v1(160.07,60.94) v1(160.07,53.33) v1(160.07,50.94) v1(160.07,43.33) v1(160.07,40.94) v1(160.07,33.33) v1(160.07,30.94) v1(160.07,23.33) v1(160.07,20.94) v1(160.07,13.33) v1(160.07,10.94) v1(160.07,3.33) v1(160.07,0.94) v1(160.07,-6.67) v1(160.07,-9.06) v1(160.07,-16.67) v1(160.07,-19.06) v1(160.03,-25.85) v1(160.2,137.72) v1(160.2,126.57) v1(160.2,116.57) v1(160.2,106.57) v1(160.2,96.57) v1(160.2,86.57) v1(160.2,76.57) v1(160.2,66.57) v1(160.2,56.57) v1(160.2,46.57) v1(160.2,36.57) v1(160.2,26.57) v1(160.2,16.57) v1(160.2,6.57) v1(160.2,-3.43) v1(160.2,-13.43) v1(160.2,-23.43) v1(160.76,144.99) v1(160.8,-33.64) v1(161.32,133.15) v1(161.32,131.14) v1(161.32,123.15) v1(161.32,121.14) v1(161.32,113.15) v1(161.32,111.14) v1(161.32,103.15) v1(161.32,101.14) v1(161.32,93.15) v1(161.32,91.14) v1(161.32,83.15) v1(161.32,81.14) v1(161.32,73.15) v1(161.32,71.14) v1(161.32,63.15) v1(161.32,61.14) v1(161.32,53.15) v1(161.32,51.14) v1(161.32,43.15) v1(161.32,41.14) v1(161.32,33.15) v1(161.32,31.14) v1(161.32,23.15) v1(161.32,21.14) v1(161.32,13.15) v1(161.32,11.14) v1(161.32,3.15) v1(161.32,1.14) v1(161.32,-6.85) v1(161.32,-8.86) v1(161.32,-16.85) v1(161.32,-18.86) v1(161.39,136.58) v1(161.39,127.71) v1(161.39,117.71) v1(161.39,107.71) v1(161.39,97.71) v1(161.39,87.71) v1(161.39,77.71) v1(161.39,67.71) v1(161.39,57.71) v1(161.39,47.71) v1(161.39,37.71) v1(161.39,27.71) v1(161.39,17.71) v1(161.39,7.71) v1(161.39,-2.29) v1(161.39,-12.29) v1(161.39,-22.29) v1(161.95,134.29) v1(161.95,130) v1(161.95,124.29) v1(161.95,120) v1(161.95,114.29) v1(161.95,110) v1(161.95,104.29) v1(161.95,100) v1(161.95,94.29) v1(161.95,90) v1(161.95,84.29) v1(161.95,80) v1(161.95,74.29) v1(161.95,70) v1(161.95,64.29) v1(161.95,60) v1(161.95,54.29) v1(161.95,50) v1(161.95,44.29) v1(161.95,40) v1(161.95,34.29) v1(161.95,30) v1(161.95,24.29) v1(161.95,20) v1(161.95,14.29) v1(161.95,10) v1(161.95,4.29) v1(161.95,0) v1(161.95,-5.71) v1(161.95,-10) v1(161.95,-15.71) v1(161.95,-20) v1(162.03,137.72) v1(162.03,126.57) v1(162.03,116.57) v1(162.03,106.57) v1(162.03,96.57) v1(162.03,86.57) v1(162.03,76.57) v1(162.03,66.57) v1(162.03,56.57) v1(162.03,46.57) v1(162.03,36.57) v1(162.03,26.57) v1(162.03,16.57) v1(162.03,6.57) v1(162.03,-3.43) v1(162.03,-13.43) v1(162.03,-23.43) v1(162.59,135.43) v1(162.59,128.86) v1(162.59,125.43) v1(162.59,118.86) v1(162.59,115.43) v1(162.59,108.86) v1(162.59,105.43) v1(162.59,98.86) v1(162.59,95.43) v1(162.59,88.86) v1(162.59,85.43) v1(162.59,78.86) v1(162.59,75.43) v1(162.59,68.86) v1(162.59,65.43) v1(162.59,58.86) v1(162.59,55.43) v1(162.59,48.86) v1(162.59,45.43) v1(162.59,38.86) v1(162.59,35.43) v1(162.59,28.86) v1(162.59,25.43) v1(162.59,18.86) v1(162.59,15.43) v1(162.59,8.86) v1(162.59,5.43) v1(162.59,-1.14) v1(162.59,-4.57) v1(162.59,-11.14) v1(162.59,-14.57) v1(162.59,-21.14) v1(162.57,-30.93) v1(162.8,144.99) v1(162.83,-33.64) v1(163.22,136.58) v1(163.14,133.15) v1(163.14,131.14) v1(163.14,123.15) v1(163.14,121.14) v1(163.14,113.15) v1(163.14,111.14) v1(163.14,103.15) v1(163.14,101.14) v1(163.14,93.15) v1(163.14,91.14) v1(163.14,83.15) v1(163.14,81.14) v1(163.14,73.15) v1(163.14,71.14) v1(163.14,63.15) v1(163.14,61.14) v1(163.14,53.15) v1(163.14,51.14) v1(163.14,43.15) v1(163.14,41.14) v1(163.14,33.15) v1(163.14,31.14) v1(163.14,23.15) v1(163.14,21.14) v1(163.14,13.15) v1(163.14,11.14) v1(163.14,3.15) v1(163.14,1.14) v1(163.14,-6.85) v1(163.14,-8.86) v1(163.14,-16.85) v1(163.14,-18.86) v1(163.53,-27.48) v1(163.78,134.29) v1(163.78,130) v1(163.78,124.29) v1(163.78,120) v1(163.78,114.29) v1(163.78,110) v1(163.78,104.29) v1(163.78,100) v1(163.78,94.29) v1(163.78,90) v1(163.78,84.29) v1(163.78,80) v1(163.78,74.29) v1(163.78,70) v1(163.78,64.29) v1(163.78,60) v1(163.78,54.29) v1(163.78,50) v1(163.78,44.29) v1(163.78,40) v1(163.78,34.29) v1(163.78,30) v1(163.78,24.29) v1(163.78,20) v1(163.78,14.29) v1(163.78,10) v1(163.78,4.29) v1(163.78,0) v1(163.78,-5.71) v1(163.78,-10) v1(163.78,-15.71) v1(163.78,-20) v1(164.83,144.99) v1(164.86,-33.64) v1(164.97,133.15) v1(164.97,131.14) v1(164.97,123.15) v1(164.97,121.14) v1(164.97,113.15) v1(164.97,111.14) v1(164.97,103.15) v1(164.97,101.14) v1(164.97,93.15) v1(164.97,91.14) v1(164.97,83.15) v1(164.97,81.14) v1(164.97,73.15) v1(164.97,71.14) v1(164.97,63.15) v1(164.97,61.14) v1(164.97,53.15) v1(164.97,51.14) v1(164.97,43.15) v1(164.97,41.14) v1(164.97,33.15) v1(164.97,31.14) v1(164.97,23.15) v1(164.97,21.14) v1(164.97,13.15) v1(164.97,11.14) v1(164.97,3.15) v1(164.97,1.14) v1(164.97,-6.85) v1(164.97,-8.86) v1(164.97,-16.85) v1(164.97,-18.86) v1(164.97,-26.85) v1(165.61,134.29) v1(165.61,130) v1(165.61,124.29) v1(165.61,120) v1(165.61,114.29) v1(165.61,110) v1(165.61,104.29) v1(165.61,100) v1(165.61,94.29) v1(165.61,90) v1(165.61,84.29) v1(165.61,80) v1(165.61,74.29) v1(165.61,70) v1(165.61,64.29) v1(165.61,60) v1(165.61,54.29) v1(165.61,50) v1(165.61,44.29) v1(165.61,40) v1(165.61,34.29) v1(165.61,30) v1(165.61,24.29) v1(165.61,20) v1(165.61,14.29) v1(165.61,10) v1(165.61,4.29) v1(165.61,0) v1(165.61,-5.71) v1(165.61,-10) v1(165.61,-15.71) v1(165.61,-20) v1(165.61,-25.71) v1(166.8,133.15) v1(166.8,131.14) v1(166.8,123.15) v1(166.8,121.14) v1(166.8,113.15) v1(166.8,111.14) v1(166.8,103.15) v1(166.8,101.14) v1(166.8,93.15) v1(166.8,91.14) v1(166.8,83.15) v1(166.8,81.14) v1(166.8,73.15) v1(166.8,71.14) v1(166.8,63.15) v1(166.8,61.14) v1(166.8,53.15) v1(166.8,51.14) v1(166.8,43.15) v1(166.8,41.14) v1(166.8,33.15) v1(166.8,31.14) v1(166.8,23.15) v1(166.8,21.14) v1(166.8,13.15) v1(166.8,11.14) v1(166.8,3.15) v1(166.8,1.14) v1(166.8,-6.85) v1(166.8,-8.86) v1(166.8,-16.85) v1(166.8,-18.86) v1(166.86,144.99) v1(166.89,-33.64) v1(167.51,137.72) v1(167.44,134.29) v1(167.44,130) v1(167.51,126.57) v1(167.44,124.29) v1(167.44,120) v1(167.51,116.57) v1(167.44,114.29) v1(167.44,110) v1(167.51,106.57) v1(167.44,104.29) v1(167.44,100) v1(167.51,96.57) v1(167.44,94.29) v1(167.44,90) v1(167.51,86.57) v1(167.44,84.29) v1(167.44,80) v1(167.51,76.57) v1(167.44,74.29) v1(167.44,70) v1(167.51,66.57) v1(167.44,64.29) v1(167.44,60) v1(167.51,56.57) v1(167.44,54.29) v1(167.44,50) v1(167.51,46.57) v1(167.44,44.29) v1(167.44,40) v1(167.51,36.57) v1(167.44,34.29) v1(167.44,30) v1(167.51,26.57) v1(167.44,24.29) v1(167.44,20) v1(167.51,16.57) v1(167.44,14.29) v1(167.44,10) v1(167.51,6.57) v1(167.44,4.29) v1(167.44,0) v1(167.51,-3.43) v1(167.44,-5.71) v1(167.44,-10) v1(167.51,-13.43) v1(167.44,-15.71) v1(167.44,-20) v1(167.51,-23.43) v1(167.82,139.12) v1(168.07,135.43) v1(168.07,128.86) v1(168.07,125.43) v1(168.07,118.86) v1(168.07,115.43) v1(168.07,108.86) v1(168.07,105.43) v1(168.07,98.86) v1(168.07,95.43) v1(168.07,88.86) v1(168.07,85.43) v1(168.07,78.86) v1(168.07,75.43) v1(168.07,68.86) v1(168.07,65.43) v1(168.07,58.86) v1(168.07,55.43) v1(168.07,48.86) v1(168.07,45.43) v1(168.07,38.86) v1(168.07,35.43) v1(168.07,28.86) v1(168.07,25.43) v1(168.07,18.86) v1(168.07,15.43) v1(168.07,8.86) v1(168.07,5.43) v1(168.07,-1.14) v1(168.07,-4.57) v1(168.07,-11.14) v1(168.07,-14.57) v1(168.07,-21.14) v1(168.3,-25.76) v1(168.71,136.58) v1(168.63,133.15) v1(168.63,131.14) v1(168.71,127.71) v1(168.63,123.15) v1(168.63,121.14) v1(168.71,117.71) v1(168.63,113.15) v1(168.63,111.14) v1(168.71,107.71) v1(168.63,103.15) v1(168.63,101.14) v1(168.71,97.71) v1(168.63,93.15) v1(168.63,91.14) v1(168.71,87.71) v1(168.63,83.15) v1(168.63,81.14) v1(168.71,77.71) v1(168.63,73.15) v1(168.63,71.14) v1(168.71,67.71) v1(168.63,63.15) v1(168.63,61.14) v1(168.71,57.71) v1(168.63,53.15) v1(168.63,51.14) v1(168.71,47.71) v1(168.63,43.15) v1(168.63,41.14) v1(168.71,37.71) v1(168.63,33.15) v1(168.63,31.14) v1(168.71,27.71) v1(168.63,23.15) v1(168.63,21.14) v1(168.71,17.71) v1(168.63,13.15) v1(168.63,11.14) v1(168.71,7.71) v1(168.63,3.15) v1(168.63,1.14) v1(168.71,-2.29) v1(168.63,-6.85) v1(168.63,-8.86) v1(168.71,-12.29) v1(168.63,-16.85) v1(168.63,-18.86) v1(168.71,-22.29) v1(168.89,144.99) v1(168.93,-33.64) v1(169.27,134.29) v1(169.27,130) v1(169.27,124.29) v1(169.27,120) v1(169.27,114.29) v1(169.27,110) v1(169.27,104.29) v1(169.27,100) v1(169.27,94.29) v1(169.27,90) v1(169.27,84.29) v1(169.27,80) v1(169.27,74.29) v1(169.27,70) v1(169.27,64.29) v1(169.27,60) v1(169.27,54.29) v1(169.27,50) v1(169.27,44.29) v1(169.27,40) v1(169.27,34.29) v1(169.27,30) v1(169.27,24.29) v1(169.27,20) v1(169.27,14.29) v1(169.27,10) v1(169.27,4.29) v1(169.27,0) v1(169.27,-5.71) v1(169.27,-10) v1(169.27,-15.71) v1(169.27,-20) v1(169.27,-31.79) v1(169.34,137.72) v1(169.34,126.57) v1(169.34,116.57) v1(169.34,106.57) v1(169.34,96.57) v1(169.34,86.57) v1(169.34,76.57) v1(169.34,66.57) v1(169.34,56.57) v1(169.34,46.57) v1(169.34,36.57) v1(169.34,26.57) v1(169.34,16.57) v1(169.34,6.57) v1(169.34,-3.43) v1(169.34,-13.43) v1(169.34,-23.43) v1(169.68,142.15) v1(169.9,135.43) v1(169.9,128.86) v1(169.9,125.43) v1(169.9,118.86) v1(169.9,115.43) v1(169.9,108.86) v1(169.9,105.43) v1(169.9,98.86) v1(169.9,95.43) v1(169.9,88.86) v1(169.9,85.43) v1(169.9,78.86) v1(169.9,75.43) v1(169.9,68.86) v1(169.9,65.43) v1(169.9,58.86) v1(169.9,55.43) v1(169.9,48.86) v1(169.9,45.43) v1(169.9,38.86) v1(169.9,35.43) v1(169.9,28.86) v1(169.9,25.43) v1(169.9,18.86) v1(169.9,15.43) v1(169.9,8.86) v1(169.9,5.43) v1(169.9,-1.14) v1(169.9,-4.57) v1(169.9,-11.14) v1(169.9,-14.57) v1(169.9,-21.14) v1(170.46,133.15) v1(170.46,123.15) v1(170.46,113.15) v1(170.46,103.15) v1(170.46,93.15) v1(170.46,83.15) v1(170.46,73.15) v1(170.46,63.15) v1(170.46,53.15) v1(170.46,43.15) v1(170.46,33.15) v1(170.46,23.15) v1(170.46,13.15) v1(170.46,3.15) v1(170.46,-6.85) v1(170.46,-16.85) v1(170.54,136.58) v1(170.54,127.71) v1(170.54,117.71) v1(170.54,107.71) v1(170.54,97.71) v1(170.54,87.71) v1(170.54,77.71) v1(170.54,67.71) v1(170.54,57.71) v1(170.54,47.71) v1(170.54,37.71) v1(170.54,27.71) v1(170.54,17.71) v1(170.54,7.71) v1(170.54,-2.29) v1(170.54,-12.29) v1(170.54,-22.29) v1(170.92,144.99) v1(170.96,-33.64) v1(171.09,134.29) v1(171.09,130) v1(171.09,124.29) v1(171.09,120) v1(171.09,114.29) v1(171.09,110) v1(171.09,104.29) v1(171.09,100) v1(171.09,94.29) v1(171.09,90) v1(171.09,84.29) v1(171.09,80) v1(171.09,74.29) v1(171.09,70) v1(171.09,64.29) v1(171.09,60) v1(171.09,54.29) v1(171.09,50) v1(171.09,44.29) v1(171.09,40) v1(171.09,34.29) v1(171.09,30) v1(171.09,24.29) v1(171.09,20) v1(171.09,14.29) v1(171.09,10) v1(171.09,4.29) v1(171.09,0) v1(171.09,-5.71) v1(171.09,-10) v1(171.09,-15.71) v1(171.09,-20) v1(171.17,137.72) v1(171.17,126.57) v1(171.17,116.57) v1(171.17,106.57) v1(171.17,96.57) v1(171.17,86.57) v1(171.17,76.57) v1(171.17,66.57) v1(171.17,56.57) v1(171.17,46.57) v1(171.17,36.57) v1(171.17,26.57) v1(171.17,16.57) v1(171.17,6.57) v1(171.17,-3.43) v1(171.17,-13.43) v1(171.17,-23.43) v1(171.68,131.14) v1(171.68,121.14) v1(171.68,111.14) v1(171.68,101.14) v1(171.68,91.14) v1(171.68,81.14) v1(171.68,71.14) v1(171.68,61.14) v1(171.68,51.14) v1(171.68,41.14) v1(171.68,31.14) v1(171.68,21.14) v1(171.68,11.14) v1(171.68,1.14) v1(171.68,-8.86) v1(171.68,-18.86) v1(171.73,135.43) v1(171.73,128.86) v1(171.73,125.43) v1(171.73,118.86) v1(171.73,115.43) v1(171.73,108.86) v1(171.73,105.43) v1(171.73,98.86) v1(171.73,95.43) v1(171.73,88.86) v1(171.73,85.43) v1(171.73,78.86) v1(171.73,75.43) v1(171.73,68.86) v1(171.73,65.43) v1(171.73,58.86) v1(171.73,55.43) v1(171.73,48.86) v1(171.73,45.43) v1(171.73,38.86) v1(171.73,35.43) v1(171.73,28.86) v1(171.73,25.43) v1(171.73,18.86) v1(171.73,15.43) v1(171.73,8.86) v1(171.73,5.43) v1(171.73,-1.14) v1(171.73,-4.57) v1(171.73,-11.14) v1(171.73,-14.57) v1(171.73,-21.14) v1(171.81,-26.71) v1(172.29,133.15) v1(172.29,123.15) v1(172.29,113.15) v1(172.29,103.15) v1(172.29,93.15) v1(172.29,83.15) v1(172.29,73.15) v1(172.29,63.15) v1(172.29,53.15) v1(172.29,43.15) v1(172.29,33.15) v1(172.29,23.15) v1(172.29,13.15) v1(172.29,3.15) v1(172.29,-6.85) v1(172.29,-16.85) v1(172.36,136.58) v1(172.36,127.71) v1(172.36,117.71) v1(172.36,107.71) v1(172.36,97.71) v1(172.36,87.71) v1(172.36,77.71) v1(172.36,67.71) v1(172.36,57.71) v1(172.36,47.71) v1(172.36,37.71) v1(172.36,27.71) v1(172.36,17.71) v1(172.36,7.71) v1(172.36,-2.29) v1(172.36,-12.29) v1(172.36,-22.29) v1(172.9,139.12) v1(172.96,144.99) v1(173,137.72) v1(172.92,134.29) v1(172.92,130) v1(173,126.57) v1(172.92,124.29) v1(172.92,120) v1(173,116.57) v1(172.92,114.29) v1(172.92,110) v1(173,106.57) v1(172.92,104.29) v1(172.92,100) v1(173,96.57) v1(172.92,94.29) v1(172.92,90) v1(173,86.57) v1(172.92,84.29) v1(172.92,80) v1(173,76.57) v1(172.92,74.29) v1(172.92,70) v1(173,66.57) v1(172.92,64.29) v1(172.92,60) v1(173,56.57) v1(172.92,54.29) v1(172.92,50) v1(173,46.57) v1(172.92,44.29) v1(172.92,40) v1(173,36.57) v1(172.92,34.29) v1(172.92,30) v1(173,26.57) v1(172.92,24.29) v1(172.92,20) v1(173,16.57) v1(172.92,14.29) v1(172.92,10) v1(173,6.57) v1(172.92,4.29) v1(172.92,0) v1(173,-3.43) v1(172.92,-5.71) v1(172.92,-10) v1(173,-13.43) v1(172.92,-15.71) v1(172.92,-20) v1(173,-23.43) v1(172.99,-33.64) v1(173.56,135.43) v1(173.56,128.86) v1(173.56,125.43) v1(173.56,118.86) v1(173.56,115.43) v1(173.56,108.86) v1(173.56,105.43) v1(173.56,98.86) v1(173.56,95.43) v1(173.56,88.86) v1(173.56,85.43) v1(173.56,78.86) v1(173.56,75.43) v1(173.56,68.86) v1(173.56,65.43) v1(173.56,58.86) v1(173.56,55.43) v1(173.56,48.86) v1(173.56,45.43) v1(173.56,38.86) v1(173.56,35.43) v1(173.56,28.86) v1(173.56,25.43) v1(173.56,18.86) v1(173.56,15.43) v1(173.56,8.86) v1(173.56,5.43) v1(173.56,-1.14) v1(173.56,-4.57) v1(173.56,-11.14) v1(173.56,-14.57) v1(173.56,-21.14) v1(174.12,133.15) v1(174.12,123.15) v1(174.12,113.15) v1(174.12,103.15) v1(174.12,93.15) v1(174.12,83.15) v1(174.12,73.15) v1(174.12,63.15) v1(174.12,53.15) v1(174.12,43.15) v1(174.12,33.15) v1(174.12,23.15) v1(174.12,13.15) v1(174.12,3.15) v1(174.12,-6.85) v1(174.12,-16.85) v1(174.19,136.58) v1(174.19,127.71) v1(174.19,117.71) v1(174.19,107.71) v1(174.19,97.71) v1(174.19,87.71) v1(174.19,77.71) v1(174.19,67.71) v1(174.19,57.71) v1(174.19,47.71) v1(174.19,37.71) v1(174.19,27.71) v1(174.19,17.71) v1(174.19,7.71) v1(174.19,-2.29) v1(174.19,-12.29) v1(174.19,-22.29) v1(174.35,-31.79) v1(174.5,131.14) v1(174.5,121.14) v1(174.5,111.14) v1(174.5,101.14) v1(174.5,91.14) v1(174.5,81.14) v1(174.5,71.14) v1(174.5,61.14) v1(174.5,51.14) v1(174.5,41.14) v1(174.5,31.14) v1(174.5,21.14) v1(174.5,11.14) v1(174.5,1.14) v1(174.5,-8.86) v1(174.5,-18.86) v1(174.75,134.29) v1(174.75,130) v1(174.75,124.29) v1(174.75,120) v1(174.75,114.29) v1(174.75,110) v1(174.75,104.29) v1(174.75,100) v1(174.75,94.29) v1(174.75,90) v1(174.75,84.29) v1(174.75,80) v1(174.75,74.29) v1(174.75,70) v1(174.75,64.29) v1(174.75,60) v1(174.75,54.29) v1(174.75,50) v1(174.75,44.29) v1(174.75,40) v1(174.75,34.29) v1(174.75,30) v1(174.75,24.29) v1(174.75,20) v1(174.75,14.29) v1(174.75,10) v1(174.75,4.29) v1(174.75,0) v1(174.75,-5.71) v1(174.75,-10) v1(174.75,-15.71) v1(174.75,-20) v1(174.83,137.72) v1(174.83,126.57) v1(174.83,116.57) v1(174.83,106.57) v1(174.83,96.57) v1(174.83,86.57) v1(174.83,76.57) v1(174.83,66.57) v1(174.83,56.57) v1(174.83,46.57) v1(174.83,36.57) v1(174.83,26.57) v1(174.83,16.57) v1(174.83,6.57) v1(174.83,-3.43) v1(174.83,-13.43) v1(174.83,-23.43) v1(174.99,144.99) v1(175.02,-33.64) v1(175.39,135.43) v1(175.39,128.86) v1(175.39,125.43) v1(175.39,118.86) v1(175.39,115.43) v1(175.39,108.86) v1(175.39,105.43) v1(175.39,98.86) v1(175.39,95.43) v1(175.39,88.86) v1(175.39,85.43) v1(175.39,78.86) v1(175.39,75.43) v1(175.39,68.86) v1(175.39,65.43) v1(175.39,58.86) v1(175.39,55.43) v1(175.39,48.86) v1(175.39,45.43) v1(175.39,38.86) v1(175.39,35.43) v1(175.39,28.86) v1(175.39,25.43) v1(175.39,18.86) v1(175.39,15.43) v1(175.39,8.86) v1(175.39,5.43) v1(175.39,-1.14) v1(175.39,-4.57) v1(175.39,-11.14) v1(175.39,-14.57) v1(175.39,-21.14) v1(175.95,133.15) v1(175.95,131.14) v1(175.95,123.15) v1(175.95,121.14) v1(175.95,113.15) v1(175.95,111.14) v1(175.95,103.15) v1(175.95,101.14) v1(175.95,93.15) v1(175.95,91.14) v1(175.95,83.15) v1(175.95,81.14) v1(175.95,73.15) v1(175.95,71.14) v1(175.95,63.15) v1(175.95,61.14) v1(175.95,53.15) v1(175.95,51.14) v1(175.95,43.15) v1(175.95,41.14) v1(175.95,33.15) v1(175.95,31.14) v1(175.95,23.15) v1(175.95,21.14) v1(175.95,13.15) v1(175.95,11.14) v1(175.95,3.15) v1(175.95,1.14) v1(175.95,-6.85) v1(175.95,-8.86) v1(175.95,-16.85) v1(175.95,-18.86) v1(176.02,136.58) v1(176.02,127.71) v1(176.02,117.71) v1(176.02,107.71) v1(176.02,97.71) v1(176.02,87.71) v1(176.02,77.71) v1(176.02,67.71) v1(176.02,57.71) v1(176.02,47.71) v1(176.02,37.71) v1(176.02,27.71) v1(176.02,17.71) v1(176.02,7.71) v1(176.02,-2.29) v1(176.02,-12.29) v1(176.02,-22.29) v1(176.39,130.88) v1(176.39,129.61) v1(176.39,120.88) v1(176.39,119.61) v1(176.39,110.88) v1(176.39,109.61) v1(176.39,100.88) v1(176.39,99.61) v1(176.39,90.88) v1(176.39,80.88) v1(176.39,79.61) v1(176.39,70.88) v1(176.39,69.61) v1(176.39,60.88) v1(176.39,59.61) v1(176.39,50.88) v1(176.39,49.61) v1(176.39,40.88) v1(176.39,39.61) v1(176.41,30.76) v1(176.39,29.61) v1(176.39,20.88) v1(176.39,19.61) v1(176.39,10.88) v1(176.39,9.61) v1(176.39,0.88) v1(176.39,-0.39) v1(176.39,-9.12) v1(176.39,-10.39) v1(176.39,-19.12) v1(176.39,-20.39) v1(176.58,134.29) v1(176.58,124.29) v1(176.58,114.29) v1(176.58,104.29) v1(176.58,94.29) v1(176.58,84.29) v1(176.58,74.29) v1(176.58,64.29) v1(176.58,54.29) v1(176.58,44.29) v1(176.58,34.29) v1(176.58,24.29) v1(176.58,14.29) v1(176.58,4.29) v1(176.58,-5.71) v1(176.58,-15.71) v1(176.66,137.72) v1(176.66,126.57) v1(176.66,116.57) v1(176.66,106.57) v1(176.66,96.57) v1(176.66,86.57) v1(176.66,76.57) v1(176.66,66.57) v1(176.66,56.57) v1(176.66,46.57) v1(176.66,36.57) v1(176.66,26.57) v1(176.66,16.57) v1(176.66,6.57) v1(176.66,-3.43) v1(176.66,-13.43) v1(176.66,-23.43) v1(177.02,144.99) v1(176.97,141.99) v1(177.05,-33.64) v1(177.22,135.43) v1(177.22,128.86) v1(177.22,125.43) v1(177.22,118.86) v1(177.22,115.43) v1(177.22,108.86) v1(177.22,105.43) v1(177.22,98.86) v1(177.22,95.43) v1(177.22,88.86) v1(177.22,85.43) v1(177.22,78.86) v1(177.22,75.43) v1(177.22,68.86) v1(177.22,65.43) v1(177.22,58.86) v1(177.22,55.43) v1(177.22,48.86) v1(177.22,45.43) v1(177.22,38.86) v1(177.22,35.43) v1(177.22,28.86) v1(177.22,25.43) v1(177.22,18.86) v1(177.22,15.43) v1(177.22,8.86) v1(177.22,5.43) v1(177.22,-1.14) v1(177.22,-4.57) v1(177.22,-11.14) v1(177.22,-14.57) v1(177.22,-21.14) v1(177.77,133.15) v1(177.77,123.15) v1(177.77,113.15) v1(177.77,103.15) v1(177.77,93.15) v1(177.77,83.15) v1(177.77,73.15) v1(177.77,63.15) v1(177.77,53.15) v1(177.77,43.15) v1(177.77,33.15) v1(177.77,23.15) v1(177.77,13.15) v1(177.77,3.15) v1(177.77,-6.85) v1(177.77,-16.85) v1(177.85,136.58) v1(177.85,127.71) v1(177.85,117.71) v1(177.85,107.71) v1(177.85,97.71) v1(177.85,87.71) v1(177.85,77.71) v1(177.85,67.71) v1(177.85,57.71) v1(177.85,47.71) v1(177.85,37.71) v1(177.85,27.71) v1(177.85,17.71) v1(177.85,7.71) v1(177.85,-2.29) v1(177.85,-12.29) v1(177.85,-22.29) v1(177.98,139.12) v1(178.41,134.29) v1(178.41,124.29) v1(178.41,114.29) v1(178.41,104.29) v1(178.41,94.29) v1(178.41,84.29) v1(178.41,74.29) v1(178.41,64.29) v1(178.41,54.29) v1(178.41,44.29) v1(178.41,34.29) v1(178.41,24.29) v1(178.41,14.29) v1(178.41,4.29) v1(178.41,-5.71) v1(178.41,-15.71) v1(178.49,137.72) v1(178.49,126.57) v1(178.49,116.57) v1(178.49,106.57) v1(178.49,96.57) v1(178.49,86.57) v1(178.49,76.57) v1(178.49,66.57) v1(178.49,56.57) v1(178.49,46.57) v1(178.49,36.57) v1(178.49,26.57) v1(178.49,16.57) v1(178.49,6.57) v1(178.49,-3.43) v1(178.49,-13.43) v1(178.49,-23.43) v1(179.05,144.99) v1(179.04,135.43) v1(179.04,128.86) v1(179.04,125.43) v1(179.04,118.86) v1(179.04,115.43) v1(179.04,108.86) v1(179.04,105.43) v1(179.04,98.86) v1(179.04,95.43) v1(179.04,88.86) v1(179.04,85.43) v1(179.04,78.86) v1(179.04,75.43) v1(179.04,68.86) v1(179.04,65.43) v1(179.04,58.86) v1(179.04,55.43) v1(179.04,48.86) v1(179.04,45.43) v1(179.04,38.86) v1(179.04,35.43) v1(179.04,28.86) v1(179.04,25.43) v1(179.04,18.86) v1(179.04,15.43) v1(179.04,8.86) v1(179.04,5.43) v1(179.04,-1.14) v1(179.04,-4.57) v1(179.04,-11.14) v1(179.04,-14.57) v1(179.04,-21.14) v1(179.09,-33.64) v1(179.2,132.15) v1(179.2,122.15) v1(179.2,112.15) v1(179.2,102.15) v1(179.2,92.15) v1(179.2,82.15) v1(179.2,72.15) v1(179.2,62.15) v1(179.2,52.15) v1(179.2,42.15) v1(179.2,32.15) v1(179.2,22.15) v1(179.2,12.15) v1(179.2,2.15) v1(179.2,-7.85) v1(179.2,-17.85) v1(179.6,133.15) v1(179.6,123.15) v1(179.6,113.15) v1(179.6,103.15) v1(179.6,93.15) v1(179.6,83.15) v1(179.6,73.15) v1(179.6,63.15) v1(179.6,53.15) v1(179.6,43.15) v1(179.6,33.15) v1(179.6,23.15) v1(179.6,13.15) v1(179.6,3.15) v1(179.6,-6.85) v1(179.6,-16.85) v1(179.68,136.58) v1(179.68,127.71) v1(179.68,117.71) v1(179.68,107.71) v1(179.68,97.71) v1(179.68,87.71) v1(179.68,77.71) v1(179.68,67.71) v1(179.68,57.71) v1(179.68,47.71) v1(179.68,37.71) v1(179.68,27.71) v1(179.68,17.71) v1(179.68,7.71) v1(179.68,-2.29) v1(179.68,-12.29) v1(179.68,-22.29) v1(180.31,137.72) v1(180.24,134.29) v1(180.31,126.57) v1(180.24,124.29) v1(180.31,116.57) v1(180.24,114.29) v1(180.31,106.57) v1(180.24,104.29) v1(180.31,96.57) v1(180.24,94.29) v1(180.31,86.57) v1(180.24,84.29) v1(180.31,76.57) v1(180.24,74.29) v1(180.31,66.57) v1(180.24,64.29) v1(180.31,56.57) v1(180.24,54.29) v1(180.31,46.57) v1(180.24,44.29) v1(180.31,36.57) v1(180.24,34.29) v1(180.31,26.57) v1(180.24,24.29) v1(180.31,16.57) v1(180.24,14.29) v1(180.31,6.57) v1(180.24,4.29) v1(180.31,-3.43) v1(180.24,-5.71) v1(180.31,-13.43) v1(180.24,-15.71) v1(180.31,-23.43) v1(180.87,135.43) v1(180.87,128.6) v1(180.87,125.43) v1(180.87,118.6) v1(180.87,115.43) v1(180.87,108.6) v1(180.87,105.43) v1(180.87,98.6) v1(180.87,95.43) v1(180.87,88.6) v1(180.87,85.43) v1(180.87,78.6) v1(180.87,75.43) v1(180.87,68.6) v1(180.87,65.43) v1(180.87,58.6) v1(180.87,55.43) v1(180.87,48.6) v1(180.87,45.43) v1(180.87,38.6) v1(180.87,35.43) v1(180.87,28.6) v1(180.87,25.43) v1(180.87,18.6) v1(180.87,15.43) v1(180.87,8.6) v1(180.87,5.43) v1(180.87,-1.4) v1(180.87,-4.57) v1(180.87,-11.4) v1(180.87,-14.57) v1(180.87,-21.4) v1(181.08,144.99) v1(181.12,-33.64) v1(181.51,136.58) v1(181.43,133.15) v1(181.51,127.71) v1(181.43,123.15) v1(181.51,117.71) v1(181.43,113.15) v1(181.51,107.71) v1(181.43,103.15) v1(181.51,97.71) v1(181.43,93.15) v1(181.51,87.71) v1(181.43,83.15) v1(181.51,77.71) v1(181.43,73.15) v1(181.51,67.71) v1(181.43,63.15) v1(181.51,57.71) v1(181.43,53.15) v1(181.51,47.71) v1(181.43,43.15) v1(181.51,37.71) v1(181.43,33.15) v1(181.51,27.71) v1(181.43,23.15) v1(181.51,17.71) v1(181.43,13.15) v1(181.51,7.71) v1(181.43,3.15) v1(181.51,-2.29) v1(181.43,-6.85) v1(181.51,-12.29) v1(181.43,-16.85) v1(181.51,-22.29) v1(182.07,134.29) v1(182.07,124.29) v1(182.07,114.29) v1(182.07,104.29) v1(182.07,94.29) v1(182.07,84.29) v1(182.07,74.29) v1(182.07,64.29) v1(182.07,54.29) v1(182.07,44.29) v1(182.07,34.29) v1(182.07,24.29) v1(182.07,14.29) v1(182.07,4.29) v1(182.07,-5.71) v1(182.07,-15.71) v1(182.14,137.72) v1(182.14,126.57) v1(182.14,116.57) v1(182.14,106.57) v1(182.14,96.57) v1(182.14,86.57) v1(182.14,76.57) v1(182.14,66.57) v1(182.14,56.57) v1(182.14,46.57) v1(182.14,36.57) v1(182.14,26.57) v1(182.14,16.57) v1(182.14,6.57) v1(182.14,-3.43) v1(182.14,-13.43) v1(182.14,-23.43) v1(182.5,132.26) v1(182.5,129.49) v1(182.5,122.26) v1(182.5,119.49) v1(182.5,112.26) v1(182.5,109.49) v1(182.5,102.26) v1(182.5,99.49) v1(182.5,92.26) v1(182.5,89.49) v1(182.5,82.26) v1(182.5,79.49) v1(182.5,72.26) v1(182.5,69.49) v1(182.5,62.26) v1(182.5,59.49) v1(182.5,52.26) v1(182.5,49.49) v1(182.5,42.26) v1(182.5,39.49) v1(182.5,32.26) v1(182.5,29.49) v1(182.5,22.26) v1(182.5,19.49) v1(182.5,12.26) v1(182.5,9.49) v1(182.5,2.26) v1(182.5,-0.51) v1(182.5,-7.74) v1(182.5,-10.51) v1(182.5,-17.74) v1(182.5,-20.51) v1(182.7,135.43) v1(182.7,125.43) v1(182.7,115.43) v1(182.7,105.43) v1(182.7,95.43) v1(182.7,85.43) v1(182.7,75.43) v1(182.7,65.43) v1(182.7,55.43) v1(182.7,45.43) v1(182.7,35.43) v1(182.7,25.43) v1(182.7,15.43) v1(182.7,5.43) v1(182.7,-4.57) v1(182.7,-14.57) v1(183.12,144.99) v1(183.06,139.12) v1(183.15,-33.64) v1(183.29,133.15) v1(183.29,123.15) v1(183.29,113.15) v1(183.29,103.15) v1(183.29,93.15) v1(183.29,83.15) v1(183.29,73.15) v1(183.29,63.15) v1(183.29,53.15) v1(183.29,43.15) v1(183.29,33.15) v1(183.29,23.15) v1(183.29,13.15) v1(183.29,3.15) v1(183.29,-6.85) v1(183.29,-16.85) v1(183.34,136.58) v1(183.34,127.71) v1(183.34,117.71) v1(183.34,107.71) v1(183.34,97.71) v1(183.34,87.71) v1(183.34,77.71) v1(183.34,67.71) v1(183.34,57.71) v1(183.34,47.71) v1(183.34,37.71) v1(183.34,27.71) v1(183.34,17.71) v1(183.34,7.71) v1(183.34,-2.29) v1(183.34,-12.29) v1(183.34,-22.29) v1(183.54,128.6) v1(183.54,118.6) v1(183.54,108.6) v1(183.54,98.6) v1(183.54,88.6) v1(183.54,78.6) v1(183.54,68.6) v1(183.54,58.6) v1(183.54,48.6) v1(183.54,38.6) v1(183.54,28.6) v1(183.54,18.6) v1(183.54,8.6) v1(183.54,-1.4) v1(183.54,-11.4) v1(183.54,-21.4) v1(183.9,134.29) v1(183.9,124.29) v1(183.9,114.29) v1(183.9,104.29) v1(183.9,94.29) v1(183.9,84.29) v1(183.9,74.29) v1(183.9,64.29) v1(183.9,54.29) v1(183.9,44.29) v1(183.9,34.29) v1(183.9,24.29) v1(183.9,14.29) v1(183.9,4.29) v1(183.9,-5.71) v1(183.9,-15.71) v1(183.94,142.15) v1(183.97,137.72) v1(183.97,126.57) v1(183.97,116.57) v1(183.97,106.57) v1(183.97,96.57) v1(183.97,86.57) v1(183.97,76.57) v1(183.97,66.57) v1(183.97,56.57) v1(183.97,46.57) v1(183.97,36.57) v1(183.97,26.57) v1(183.97,16.57) v1(183.97,6.57) v1(183.97,-3.43) v1(183.97,-13.43) v1(183.97,-23.43) v1(184.33,132.26) v1(184.33,129.49) v1(184.33,122.26) v1(184.33,119.49) v1(184.33,112.26) v1(184.33,109.49) v1(184.33,102.26) v1(184.33,99.49) v1(184.33,92.26) v1(184.33,89.49) v1(184.33,82.26) v1(184.33,79.49) v1(184.33,72.26) v1(184.33,69.49) v1(184.33,62.26) v1(184.33,59.49) v1(184.33,52.26) v1(184.33,49.49) v1(184.33,42.26) v1(184.33,39.49) v1(184.33,32.26) v1(184.33,29.49) v1(184.33,22.26) v1(184.33,19.49) v1(184.33,12.26) v1(184.33,9.49) v1(184.33,2.26) v1(184.33,-0.51) v1(184.33,-7.74) v1(184.33,-10.51) v1(184.33,-17.74) v1(184.33,-20.51) v1(184.53,135.43) v1(184.53,125.43) v1(184.53,115.43) v1(184.53,105.43) v1(184.53,95.43) v1(184.53,85.43) v1(184.53,75.43) v1(184.53,65.43) v1(184.53,55.43) v1(184.53,45.43) v1(184.53,35.43) v1(184.53,25.43) v1(184.53,15.43) v1(184.53,5.43) v1(184.53,-4.57) v1(184.53,-14.57) v1(185.12,133.15) v1(185.12,123.15) v1(185.12,113.15) v1(185.12,103.15) v1(185.12,93.15) v1(185.12,83.15) v1(185.12,73.15) v1(185.12,63.15) v1(185.12,53.15) v1(185.12,43.15) v1(185.12,33.15) v1(185.12,23.15) v1(185.12,13.15) v1(185.12,3.15) v1(185.12,-6.85) v1(185.12,-16.85) v1(185.15,144.99) v1(185.17,136.58) v1(185.17,127.71) v1(185.17,117.71) v1(185.17,107.71) v1(185.17,97.71) v1(185.17,87.71) v1(185.17,77.71) v1(185.17,67.71) v1(185.17,57.71) v1(185.17,47.71) v1(185.17,37.71) v1(185.17,27.71) v1(185.17,17.71) v1(185.17,7.71) v1(185.17,-2.29) v1(185.17,-12.29) v1(185.17,-22.29) v1(185.18,-33.64) v1(185.37,128.6) v1(185.37,118.6) v1(185.37,108.6) v1(185.37,98.6) v1(185.37,88.6) v1(185.37,78.6) v1(185.37,68.6) v1(185.37,58.6) v1(185.37,48.6) v1(185.37,38.6) v1(185.37,28.6) v1(185.37,18.6) v1(185.37,8.6) v1(185.37,-1.4) v1(185.37,-11.4) v1(185.37,-21.4) v1(185.8,137.72) v1(185.72,134.29) v1(185.8,126.57) v1(185.72,124.29) v1(185.8,116.57) v1(185.72,114.29) v1(185.8,106.57) v1(185.72,104.29) v1(185.8,96.57) v1(185.72,94.29) v1(185.8,86.57) v1(185.72,84.29) v1(185.8,76.57) v1(185.72,74.29) v1(185.8,66.57) v1(185.72,64.29) v1(185.8,56.57) v1(185.72,54.29) v1(185.8,46.57) v1(185.72,44.29) v1(185.8,36.57) v1(185.72,34.29) v1(185.8,26.57) v1(185.72,24.29) v1(185.8,16.57) v1(185.72,14.29) v1(185.8,6.57) v1(185.72,4.29) v1(185.8,-3.43) v1(185.72,-5.71) v1(185.8,-13.43) v1(185.72,-15.71) v1(185.8,-23.43) v1(186.16,132.26) v1(186.16,129.49) v1(186.16,122.26) v1(186.16,119.49) v1(186.16,112.26) v1(186.16,109.49) v1(186.16,102.26) v1(186.16,99.49) v1(186.16,92.26) v1(186.16,89.49) v1(186.16,82.26) v1(186.16,79.49) v1(186.16,72.26) v1(186.16,69.49) v1(186.16,62.26) v1(186.16,59.49) v1(186.16,52.26) v1(186.16,49.49) v1(186.16,42.26) v1(186.16,39.49) v1(186.16,32.26) v1(186.16,29.49) v1(186.16,22.26) v1(186.16,19.49) v1(186.16,12.26) v1(186.16,9.49) v1(186.16,2.26) v1(186.16,-0.51) v1(186.16,-7.74) v1(186.16,-10.51) v1(186.16,-17.74) v1(186.16,-20.51) v1(186.36,135.43) v1(186.36,125.43) v1(186.36,115.43) v1(186.36,105.43) v1(186.36,95.43) v1(186.36,85.43) v1(186.36,75.43) v1(186.36,65.43) v1(186.36,55.43) v1(186.36,45.43) v1(186.36,35.43) v1(186.36,25.43) v1(186.36,15.43) v1(186.36,5.43) v1(186.36,-4.57) v1(186.36,-14.57) v1(186.99,136.58) v1(186.94,133.15) v1(186.99,127.71) v1(186.94,123.15) v1(186.99,117.71) v1(186.94,113.15) v1(186.99,107.71) v1(186.94,103.15) v1(186.99,97.71) v1(186.94,93.15) v1(186.99,87.71) v1(186.94,83.15) v1(186.99,77.71) v1(186.94,73.15) v1(186.99,67.71) v1(186.94,63.15) v1(186.99,57.71) v1(186.94,53.15) v1(186.99,47.71) v1(186.94,43.15) v1(186.99,37.71) v1(186.94,33.15) v1(186.99,27.71) v1(186.94,23.15) v1(186.99,17.71) v1(186.94,13.15) v1(186.99,7.71) v1(186.94,3.15) v1(186.99,-2.29) v1(186.94,-6.85) v1(186.99,-12.29) v1(186.94,-16.85) v1(186.99,-22.29) v1(187.18,144.99) v1(187.2,128.6) v1(187.2,118.6) v1(187.2,108.6) v1(187.2,98.6) v1(187.2,88.6) v1(187.2,78.6) v1(187.2,68.6) v1(187.2,58.6) v1(187.2,48.6) v1(187.2,38.6) v1(187.2,28.6) v1(187.2,18.6) v1(187.2,8.6) v1(187.2,-1.4) v1(187.2,-11.4) v1(187.2,-21.4) v1(187.21,-33.64) v1(187.55,134.29) v1(187.55,124.29) v1(187.55,114.29) v1(187.55,104.29) v1(187.55,94.29) v1(187.55,84.29) v1(187.55,74.29) v1(187.55,64.29) v1(187.55,54.29) v1(187.55,44.29) v1(187.55,34.29) v1(187.55,24.29) v1(187.55,14.29) v1(187.55,4.29) v1(187.55,-5.71) v1(187.55,-15.71) v1(187.63,137.72) v1(187.63,126.57) v1(187.63,116.57) v1(187.63,106.57) v1(187.63,96.57) v1(187.63,86.57) v1(187.63,76.57) v1(187.63,66.57) v1(187.63,56.57) v1(187.63,46.57) v1(187.63,36.57) v1(187.63,26.57) v1(187.63,16.57) v1(187.63,6.57) v1(187.63,-3.43) v1(187.63,-13.43) v1(187.63,-23.43) v1(187.99,132.26) v1(187.99,129.49) v1(187.99,122.26) v1(187.99,119.49) v1(187.99,112.26) v1(187.99,109.49) v1(187.99,102.26) v1(187.99,99.49) v1(187.99,92.26) v1(187.99,89.49) v1(187.99,82.26) v1(187.99,79.49) v1(187.99,72.26) v1(187.99,69.49) v1(187.99,62.26) v1(187.99,59.49) v1(187.99,52.26) v1(187.99,49.49) v1(187.99,42.26) v1(187.99,39.49) v1(187.99,32.26) v1(187.99,29.49) v1(187.99,22.26) v1(187.99,19.49) v1(187.99,12.26) v1(187.99,9.49) v1(187.99,2.26) v1(187.99,-0.51) v1(187.99,-7.74) v1(187.99,-10.51) v1(187.99,-17.74) v1(187.99,-20.51) v1(188.14,139.12) v1(188.19,135.43) v1(188.19,125.43) v1(188.19,115.43) v1(188.19,105.43) v1(188.19,95.43) v1(188.19,85.43) v1(188.19,75.43) v1(188.19,65.43) v1(188.19,55.43) v1(188.19,45.43) v1(188.19,35.43) v1(188.19,25.43) v1(188.19,15.43) v1(188.19,5.43) v1(188.19,-4.57) v1(188.19,-14.57) v1(188.77,133.15) v1(188.77,123.15) v1(188.77,113.15) v1(188.77,103.15) v1(188.77,93.15) v1(188.77,83.15) v1(188.77,73.15) v1(188.77,63.15) v1(188.77,53.15) v1(188.77,43.15) v1(188.77,33.15) v1(188.77,23.15) v1(188.77,13.15) v1(188.77,3.15) v1(188.77,-6.85) v1(188.77,-16.85) v1(188.82,136.58) v1(188.82,127.71) v1(188.82,117.71) v1(188.82,107.71) v1(188.82,97.71) v1(188.82,87.71) v1(188.82,77.71) v1(188.82,67.71) v1(188.82,57.71) v1(188.82,47.71) v1(188.82,37.71) v1(188.82,27.71) v1(188.82,17.71) v1(188.82,7.71) v1(188.82,-2.29) v1(188.82,-12.29) v1(188.82,-22.29) v1(189.03,128.6) v1(189.03,118.6) v1(189.03,108.6) v1(189.03,98.6) v1(189.03,88.6) v1(189.03,78.6) v1(189.03,68.6) v1(189.03,58.6) v1(189.03,48.6) v1(189.03,38.6) v1(189.03,28.6) v1(189.03,18.6) v1(189.03,8.6) v1(189.03,-1.4) v1(189.03,-11.4) v1(189.03,-21.4) v1(189.21,144.99) v1(189.25,-33.64) v1(189.38,134.29) v1(189.38,124.29) v1(189.38,114.29) v1(189.38,104.29) v1(189.38,94.29) v1(189.38,84.29) v1(189.38,74.29) v1(189.38,64.29) v1(189.38,54.29) v1(189.38,44.29) v1(189.38,34.29) v1(189.38,24.29) v1(189.38,14.29) v1(189.38,4.29) v1(189.38,-5.71) v1(189.38,-15.71) v1(189.46,137.72) v1(189.46,126.57) v1(189.46,116.57) v1(189.46,106.57) v1(189.46,96.57) v1(189.46,86.57) v1(189.46,76.57) v1(189.46,66.57) v1(189.46,56.57) v1(189.46,46.57) v1(189.46,36.57) v1(189.46,26.57) v1(189.43,19.75) v1(189.46,16.57) v1(189.46,6.57) v1(189.46,-3.43) v1(189.46,-13.43) v1(189.46,-23.43) v1(189.56,42) v1(189.56,39.75) v1(189.56,32) v1(189.56,29.87) v1(189.56,22) v1(189.56,9.87) v1(189.56,2) v1(189.56,-0.13) v1(189.56,-8) v1(189.56,-10.13) v1(189.56,-18) v1(189.56,-20.13) v1(189.69,11.88) v1(189.81,132.26) v1(189.81,129.49) v1(189.81,122.26) v1(189.81,119.49) v1(189.81,112.26) v1(189.81,109.49) v1(189.81,102.26) v1(189.81,99.49) v1(189.81,92.26) v1(189.81,89.49) v1(189.81,82.26) v1(189.81,79.49) v1(189.81,72.26) v1(189.81,69.49) v1(189.81,62.26) v1(189.81,59.49) v1(189.81,52.26) v1(189.81,49.49) v1(190.02,135.43) v1(190.02,125.43) v1(190.02,115.43) v1(190.02,105.43) v1(190.02,95.43) v1(190.02,85.43) v1(190.02,75.43) v1(190.02,65.43) v1(190.02,55.43) v1(190.02,45.43) v1(190.02,35.43) v1(190.02,25.43) v1(190.02,15.43) v1(190.02,5.43) v1(190.02,-4.57) v1(190.02,-14.57) v1(190.6,133.15) v1(190.6,123.15) v1(190.6,113.15) v1(190.6,103.15) v1(190.6,93.15) v1(190.6,83.15) v1(190.6,73.15) v1(190.6,63.15) v1(190.6,53.15) v1(190.6,43.15) v1(190.6,33.15) v1(190.6,23.15) v1(190.6,13.15) v1(190.6,3.15) v1(190.6,-6.85) v1(190.6,-16.85) v1(190.78,-18.17) v1(190.91,142.31) v1(191.21,134.29) v1(191.21,124.29) v1(191.21,114.29) v1(191.21,104.29) v1(191.21,94.29) v1(191.21,84.29) v1(191.21,74.29) v1(191.21,64.29) v1(191.21,54.29) v1(191.21,44.29) v1(191.21,34.29) v1(191.21,24.29) v1(191.21,14.29) v1(191.21,4.29) v1(191.21,-5.71) v1(191.21,-15.71) v1(191.24,144.99) v1(191.28,-33.64) v1(191.64,132.26) v1(191.64,129.49) v1(191.64,122.26) v1(191.64,119.49) v1(191.64,112.26) v1(191.64,109.49) v1(191.64,102.26) v1(191.64,99.49) v1(191.64,92.26) v1(191.64,89.49) v1(191.64,82.26) v1(191.64,79.49) v1(191.64,72.26) v1(191.64,69.49) v1(191.64,62.26) v1(191.64,59.49) v1(191.64,52.26) v1(191.64,49.49) v1(191.64,42.26) v1(191.64,39.49) v1(191.64,32.26) v1(191.64,29.49) v1(191.64,22.26) v1(191.64,19.49) v1(191.64,9.49) v1(191.64,-0.51) v1(191.64,-7.74) v1(191.64,-10.51) v1(191.64,-20.51) v1(192.28,-18.15) v1(192.43,133.15) v1(192.43,123.15) v1(192.43,113.15) v1(192.43,103.15) v1(192.43,93.15) v1(192.43,83.15) v1(192.43,73.15) v1(192.43,63.15) v1(192.43,53.15) v1(192.43,43.15) v1(192.43,33.15) v1(192.43,23.15) v1(192.48,10.99) v1(192.48,0.99) v1(192.43,-6.85) v1(193.04,134.29) v1(193.22,139.12) v1(193.28,144.99) v1(193.32,29.24) v1(193.32,25.58) v1(193.32,23.75) v1(193.32,21.92) v1(193.32,14.6) v1(193.32,10.95) v1(193.32,9.12) v1(193.32,5.46) v1(193.32,1.8) v1(193.32,-0.03) v1(193.32,-5.51) v1(193.32,-7.34) v1(193.32,-11) v1(193.32,-14.66) v1(193.32,-20.14) v1(193.31,-33.64) v1(193.42,39.95) v1(193.42,34.47) v1(193.42,32.64) v1(193.47,132.26) v1(193.47,124.94) v1(193.47,123.11) v1(193.47,121.28) v1(193.47,113.97) v1(193.47,112.14) v1(193.47,104.83) v1(193.47,103) v1(193.47,99.34) v1(193.47,93.85) v1(193.47,92.02) v1(193.47,89.94) v1(193.47,84.71) v1(193.47,82.88) v1(193.47,79.22) v1(193.47,73.74) v1(193.47,71.91) v1(193.47,64.59) v1(193.47,62.76) v1(193.47,59.11) v1(193.47,55.45) v1(193.47,53.62) v1(193.47,51.79) v1(193.47,49.96) v1(193.57,43) v1(193.61,-16.82) v1(194.21,39.01) v1(194.21,37.19) v1(194.21,35.36) v1(194.21,33.53) v1(194.16,28.5) v1(194.16,26.67) v1(194.16,24.84) v1(194.16,23.01) v1(194.16,12.04) v1(194.16,10.21) v1(194.16,8.38) v1(194.16,6.55) v1(194.16,2.9) v1(194.16,1.07) v1(194.16,-0.76) v1(194.16,-2.59) v1(194.16,-4.42) v1(194.16,-6.25) v1(194.16,-9.91) v1(194.16,-11.73) v1(194.16,-13.56) v1(194.16,-19.05) v1(194.16,-20.88) v1(194.16,-22.71) v1(194.26,133.15) v1(194.26,131.32) v1(194.26,127.66) v1(194.26,125.83) v1(194.26,124) v1(194.26,122.17) v1(194.26,120.35) v1(194.26,116.69) v1(194.26,114.86) v1(194.26,113.03) v1(194.26,111.2) v1(194.26,107.54) v1(194.26,105.71) v1(194.26,103.89) v1(194.26,102.06) v1(194.26,98.4) v1(194.26,96.57) v1(194.26,94.74) v1(194.26,92.91) v1(194.26,89.26) v1(194.26,87.43) v1(194.26,85.6) v1(194.26,83.77) v1(194.26,81.94) v1(194.26,78.28) v1(194.26,76.45) v1(194.26,74.63) v1(194.26,72.8) v1(194.26,70.97) v1(194.26,67.31) v1(194.26,65.48) v1(194.26,63.65) v1(194.26,61.82) v1(194.26,59.99) v1(194.26,58.17) v1(194.26,56.34) v1(194.26,54.51) v1(194.26,52.68) v1(194.26,48.97) v1(194.26,31.9) v1(194.26,29.97) v1(194.36,99.97) v1(194.36,47.55) v1(194.36,45.72) v1(194.36,43.89) v1(194.36,42.06) v1(194.51,-15.93) v1(195.07,57.61) v1(195.15,29.24) v1(195.15,27.41) v1(195.15,25.58) v1(195.15,23.75) v1(195.15,21.97) v1(195.15,12.78) v1(195.15,10.95) v1(195.15,9.12) v1(195.15,7.29) v1(195.15,3.63) v1(195.15,1.8) v1(195.15,-0.03) v1(195.15,-1.85) v1(195.15,-3.68) v1(195.15,-5.51) v1(195.15,-9.17) v1(195.15,-11) v1(195.15,-12.83) v1(195.15,-18.31) v1(195.15,-20.14) v1(195.15,-21.97) v1(195.31,144.99) v1(195.3,132.26) v1(195.3,130.43) v1(195.3,126.77) v1(195.3,124.94) v1(195.3,123.11) v1(195.3,121.28) v1(195.3,119.46) v1(195.3,115.8) v1(195.3,113.97) v1(195.3,112.14) v1(195.3,110.31) v1(195.3,106.65) v1(195.3,104.83) v1(195.3,103) v1(195.3,99.34) v1(195.3,97.51) v1(195.3,95.68) v1(195.3,93.85) v1(195.3,92.02) v1(195.3,89.94) v1(195.3,88.37) v1(195.3,86.54) v1(195.3,84.71) v1(195.3,82.88) v1(195.3,81.05) v1(195.3,77.39) v1(195.3,75.56) v1(195.3,73.74) v1(195.3,71.91) v1(195.3,70.08) v1(195.3,66.42) v1(195.3,64.59) v1(195.3,62.76) v1(195.3,59.11) v1(195.3,55.45) v1(195.3,53.62) v1(195.3,51.79) v1(195.3,48.34) v1(195.25,39.95) v1(195.25,38.13) v1(195.25,36.3) v1(195.25,34.47) v1(195.25,32.64) v1(195.4,46.66) v1(195.4,44.83) v1(195.4,43) v1(195.34,-33.64) v1(195.45,-15) v1(195.68,59.94) v1(195.74,134.12) v1(195.99,28.5) v1(195.99,26.67) v1(195.99,24.84) v1(195.99,23.01) v1(195.99,13.87) v1(195.99,12.04) v1(195.99,10.21) v1(195.99,8.38) v1(195.99,4.72) v1(195.99,2.9) v1(195.99,1.07) v1(195.99,-0.76) v1(195.99,-2.59) v1(195.99,-4.42) v1(195.99,-8.08) v1(195.99,-9.91) v1(195.99,-11.73) v1(195.99,-17.22) v1(195.99,-19.05) v1(195.99,-20.88) v1(196.09,131.32) v1(196.09,129.49) v1(196.09,120.35) v1(196.09,118.52) v1(196.09,114.86) v1(196.09,113.03) v1(196.09,111.2) v1(196.09,109.37) v1(196.09,105.71) v1(196.09,103.89) v1(196.09,102.06) v1(196.09,98.4) v1(196.09,96.57) v1(196.09,94.74) v1(196.09,92.91) v1(196.09,89.26) v1(196.09,87.43) v1(196.09,85.6) v1(196.09,83.77) v1(196.09,81.94) v1(196.09,80.11) v1(196.09,76.45) v1(196.09,74.63) v1(196.09,72.8) v1(196.09,70.97) v1(196.09,69.14) v1(196.09,65.48) v1(196.09,63.65) v1(196.09,61.82) v1(196.09,58.17) v1(196.09,56.34) v1(196.09,54.51) v1(196.09,52.68) v1(196.09,50.85) v1(196.04,39.01) v1(196.04,37.19) v1(196.04,35.36) v1(196.04,33.53) v1(196.09,31.9) v1(196.09,29.97) v1(196.09,15.28) v1(196.19,47.55) v1(196.19,45.72) v1(196.19,43.89) v1(196.19,42.06) v1(196.4,-14.05) v1(196.62,59.11) v1(196.62,57.28) v1(196.82,50.16) v1(196.98,29.24) v1(196.98,27.41) v1(196.98,25.58) v1(196.98,23.75) v1(196.99,16.17) v1(196.98,14.6) v1(196.98,5.46) v1(196.98,3.63) v1(196.98,1.8) v1(196.98,-0.03) v1(196.98,-1.85) v1(196.98,-3.68) v1(196.98,-7.34) v1(196.98,-9.17) v1(196.98,-11) v1(196.98,-16.48) v1(196.98,-18.31) v1(196.98,-20.14) v1(197.08,39.95) v1(197.08,38.13) v1(197.08,36.3) v1(197.08,34.47) v1(197.08,32.64) v1(197.13,130.43) v1(197.13,128.6) v1(197.13,126.77) v1(197.13,124.94) v1(197.13,123.11) v1(197.13,119.46) v1(197.13,117.63) v1(197.13,113.97) v1(197.13,112.14) v1(197.13,110.31) v1(197.13,108.48) v1(197.13,104.83) v1(197.13,103) v1(197.13,101.17) v1(197.13,97.51) v1(197.13,95.68) v1(197.13,93.85) v1(197.13,92.02) v1(197.13,88.37) v1(197.13,86.54) v1(197.13,84.71) v1(197.13,82.88) v1(197.13,81.05) v1(197.13,79.22) v1(197.13,75.56) v1(197.13,73.74) v1(197.13,71.91) v1(197.13,70.08) v1(197.13,68.25) v1(197.13,55.35) v1(197.13,53.62) v1(197.13,51.79) v1(197.13,48.34) v1(197.28,62.92) v1(197.23,46.66) v1(197.23,44.83) v1(197.23,43) v1(197.27,-13.18) v1(197.34,144.99) v1(197.33,61.09) v1(197.41,56.29) v1(197.37,-33.64) v1(197.52,136.51) v1(197.46,58.27) v1(197.64,141.99) v1(197.82,28.5) v1(197.82,26.67) v1(197.82,24.84) v1(197.79,12.83) v1(197.82,10.21) v1(197.82,8.38) v1(197.82,6.55) v1(197.82,4.72) v1(197.82,2.9) v1(197.82,1.07) v1(197.82,-0.76) v1(197.82,-2.59) v1(197.82,-6.25) v1(197.82,-8.08) v1(197.82,-9.91) v1(197.82,-15.39) v1(197.82,-17.22) v1(197.82,-19.05) v1(197.92,129.49) v1(197.92,127.66) v1(197.92,125.83) v1(197.92,124) v1(197.92,122.17) v1(197.92,118.52) v1(197.92,116.69) v1(197.92,113.03) v1(197.92,111.2) v1(197.92,109.37) v1(197.92,107.54) v1(197.92,103.89) v1(197.92,102.06) v1(197.92,100.23) v1(197.92,96.57) v1(197.92,94.74) v1(197.92,92.91) v1(197.92,91.08) v1(197.92,87.43) v1(197.92,85.6) v1(197.92,83.77) v1(197.92,81.94) v1(197.92,80.11) v1(197.92,78.28) v1(197.92,74.63) v1(197.92,72.8) v1(197.92,70.97) v1(197.92,69.14) v1(197.92,67.31) v1(197.92,65.48) v1(197.92,52.68) v1(197.92,50.85) v1(197.87,39.01) v1(197.87,37.19) v1(197.87,35.36) v1(197.87,33.53) v1(197.92,29.97) v1(197.97,54.56) v1(198.02,47.55) v1(198.02,45.72) v1(198.02,43.89) v1(198.02,42.06) v1(198.09,55.6) v1(198.06,15.74) v1(198.13,131.63) v1(198.17,62.03) v1(198.3,139.12) v1(198.22,60.15) v1(198.22,31.85) v1(198.26,-12.19) v1(198.4,57.33) v1(198.65,50.16) v1(198.68,13.82) v1(198.7,-14.55) v1(198.74,126.75) v1(198.81,29.24) v1(198.81,27.41) v1(198.81,25.58) v1(198.79,17.97) v1(198.81,10.95) v1(198.81,9.12) v1(198.81,7.29) v1(198.81,5.46) v1(198.81,3.63) v1(198.81,1.8) v1(198.81,-0.03) v1(198.81,-1.85) v1(198.81,-5.51) v1(198.81,-7.34) v1(198.81,-9.17) v1(198.81,-16.48) v1(198.81,-18.31) v1(198.91,39.95) v1(198.91,38.13) v1(198.91,36.3) v1(198.91,34.47) v1(198.91,32.64) v1(198.96,123.11) v1(198.96,121.28) v1(198.96,117.63) v1(198.96,115.8) v1(198.96,112.14) v1(198.96,110.31) v1(198.96,108.48) v1(198.96,106.65) v1(198.96,103) v1(198.96,101.17) v1(198.96,99.34) v1(198.96,95.68) v1(198.96,93.85) v1(198.96,92.02) v1(198.96,90.2) v1(198.96,86.54) v1(198.96,84.71) v1(198.96,82.88) v1(198.96,81.05) v1(198.96,79.22) v1(198.96,77.39) v1(198.96,73.74) v1(198.96,71.91) v1(198.96,70.08) v1(198.96,68.25) v1(198.96,66.42) v1(198.96,64.59) v1(198.96,53.57) v1(198.96,51.79) v1(198.96,48.34) v1(198.96,16.63) v1(199.11,61.09) v1(199.06,59.31) v1(199.03,54.71) v1(199.06,46.66) v1(199.06,44.83) v1(199.06,43) v1(199.19,-11.25) v1(199.37,144.99) v1(199.41,-33.64) v1(199.59,56.18) v1(199.56,14.68) v1(199.69,39.01) v1(199.69,37.19) v1(199.69,35.36) v1(199.69,33.53) v1(199.64,28.5) v1(199.64,26.67) v1(199.69,18.87) v1(199.64,13.87) v1(199.64,12.04) v1(199.64,10.21) v1(199.64,8.38) v1(199.64,6.55) v1(199.64,4.72) v1(199.64,2.9) v1(199.64,1.07) v1(199.64,-0.76) v1(199.64,-4.42) v1(199.64,-6.25) v1(199.64,-8.08) v1(199.64,-13.56) v1(199.64,-15.39) v1(199.64,-17.22) v1(199.75,122.17) v1(199.75,120.35) v1(199.75,116.69) v1(199.75,114.86) v1(199.75,111.2) v1(199.75,109.37) v1(199.75,107.54) v1(199.75,105.71) v1(199.75,102.06) v1(199.75,100.23) v1(199.75,98.4) v1(199.75,94.74) v1(199.75,92.91) v1(199.75,91.08) v1(199.75,89.26) v1(199.75,85.6) v1(199.75,83.77) v1(199.75,81.94) v1(199.75,80.11) v1(199.75,78.28) v1(199.75,76.45) v1(199.75,72.8) v1(199.75,70.97) v1(199.75,69.14) v1(199.75,67.31) v1(199.75,65.48) v1(199.75,63.65) v1(199.8,52.73) v1(199.75,50.85) v1(199.75,29.97) v1(199.9,58.47) v1(199.85,47.55) v1(199.85,45.72) v1(199.85,43.89) v1(199.85,42.06) v1(199.85,17.53) v1(200.1,60.1) v1(200.03,53.67) v1(200.11,-10.34) v1(200.25,75.13) v1(200.32,24.74) v1(200.37,40.01) v1(200.37,34.12) v1(200.4,23.28) v1(200.35,22.1) v1(200.32,-7.29) v1(200.48,50.16) v1(200.46,15.58) v1(200.57,134.12) v1(200.57,129.19) v1(200.57,124.26) v1(200.58,19.77) v1(200.53,-12.62) v1(200.63,55.09) v1(200.63,29.24) v1(200.63,14.6) v1(200.67,13.85) v1(200.63,12.78) v1(200.63,10.95) v1(200.63,9.12) v1(200.63,7.29) v1(200.63,5.46) v1(200.63,3.63) v1(200.63,1.8) v1(200.63,-0.03) v1(200.63,-3.68) v1(200.63,-14.66) v1(200.63,-16.48) v1(200.79,121.28) v1(200.79,119.46) v1(200.79,115.8) v1(200.79,113.97) v1(200.79,110.31) v1(200.79,108.48) v1(200.79,106.65) v1(200.79,104.83) v1(200.79,101.17) v1(200.79,99.34) v1(200.79,97.51) v1(200.79,93.85) v1(200.79,92.02) v1(200.79,90.2) v1(200.79,88.37) v1(200.79,84.71) v1(200.79,82.88) v1(200.79,81.05) v1(200.79,79.22) v1(200.79,77.39) v1(200.79,71.91) v1(200.79,70.08) v1(200.79,68.25) v1(200.79,66.42) v1(200.79,64.59) v1(200.79,62.76) v1(200.74,57.63) v1(200.79,48.34) v1(200.74,38.13) v1(200.74,36.3) v1(200.82,30.47) v1(200.75,18.43) v1(200.84,51.64) v1(200.89,46.66) v1(200.89,44.83) v1(200.89,43) v1(200.89,-5.31) v1(200.94,59.26) v1(200.96,52.73) v1(200.96,27.95) v1(200.99,-9.43) v1(201.17,74.17) v1(201.22,25.64) v1(201.21,15) v1(201.27,75.34) v1(201.27,35.02) v1(201.3,24.18) v1(201.25,22.99) v1(201.26,-6.38) v1(201.4,144.99) v1(201.36,16.48) v1(201.5,29.79) v1(201.48,20.66) v1(201.44,-33.64) v1(201.57,120.35) v1(201.57,118.52) v1(201.57,114.86) v1(201.57,113.03) v1(201.57,109.37) v1(201.57,107.54) v1(201.57,105.71) v1(201.57,103.89) v1(201.57,100.23) v1(201.57,98.4) v1(201.57,96.57) v1(201.57,92.91) v1(201.57,91.08) v1(201.57,89.26) v1(201.57,70.97) v1(201.57,69.14) v1(201.57,67.31) v1(201.57,65.48) v1(201.57,63.65) v1(201.57,61.82) v1(201.57,56.79) v1(201.52,54.15) v1(201.57,50.85) v1(201.52,39.01) v1(201.52,37.19) v1(201.68,47.55) v1(201.68,45.72) v1(201.68,43.89) v1(201.68,42.06) v1(201.64,40.01) v1(201.65,19.33) v1(201.63,-13.67) v1(201.73,31.35) v1(201.73,-11.33) v1(201.83,58.37) v1(201.86,28.85) v1(201.86,-2.08) v1(201.83,-4.4) v1(201.98,73.36) v1(202.12,26.54) v1(202.11,15.9) v1(202.04,-8.42) v1(202.18,74.37) v1(202.17,35.92) v1(202.2,25.08) v1(202.15,23.89) v1(202.2,-5.47) v1(202.26,51.49) v1(202.31,50.16) v1(202.26,17.38) v1(202.41,55.96) v1(202.41,53.37) v1(202.39,30.69) v1(202.38,21.56) v1(202.5,13.39) v1(202.49,12.09) v1(202.44,10.46) v1(202.44,9.04) v1(202.44,7.87) v1(202.44,5.74) v1(202.49,4.17) v1(202.44,1.98) v1(202.49,0.15) v1(202.62,119.46) v1(202.62,117.63) v1(202.62,113.97) v1(202.62,112.14) v1(202.62,108.48) v1(202.62,106.65) v1(202.62,104.83) v1(202.62,103) v1(202.62,99.34) v1(202.62,97.51) v1(202.62,95.68) v1(202.62,92.02) v1(202.62,90.2) v1(202.62,88.37) v1(202.62,86.54) v1(202.62,84.71) v1(202.62,82.88) v1(202.62,81.05) v1(202.62,79.22) v1(202.62,77.39) v1(202.62,70.08) v1(202.62,68.25) v1(202.62,66.42) v1(202.62,64.59) v1(202.62,62.76) v1(202.62,60.93) v1(202.62,48.34) v1(202.56,38.13) v1(202.55,20.23) v1(202.72,46.66) v1(202.72,44.83) v1(202.72,43) v1(202.63,32.25) v1(202.69,-12.6) v1(202.77,57.43) v1(202.76,29.74) v1(202.91,40.01) v1(203,73.56) v1(203.01,27.44) v1(203.01,16.8) v1(202.95,-10.21) v1(203.05,72.29) v1(203.1,36.78) v1(203.1,25.98) v1(203.05,24.79) v1(203.21,131.63) v1(203.21,126.7) v1(203.21,121.77) v1(203.2,52.58) v1(203.16,18.27) v1(203.2,14.22) v1(203.2,-7.24) v1(203.25,55.12) v1(203.29,31.58) v1(203.28,22.46) v1(203.36,139.2) v1(203.4,118.52) v1(203.4,116.69) v1(203.4,113.03) v1(203.4,111.2) v1(203.4,107.54) v1(203.4,105.71) v1(203.4,103.89) v1(203.4,102.06) v1(203.4,98.4) v1(203.4,96.57) v1(203.4,94.74) v1(203.4,91.08) v1(203.4,89.26) v1(203.4,87.43) v1(203.4,85.6) v1(203.4,83.77) v1(203.4,81.94) v1(203.4,80.11) v1(203.4,78.28) v1(203.4,76.45) v1(203.4,69.14) v1(203.4,67.31) v1(203.4,65.48) v1(203.4,63.65) v1(203.4,59.99) v1(203.4,50.85) v1(203.4,11.2) v1(203.4,9.93) v1(203.4,8.66) v1(203.4,7.39) v1(203.4,6.12) v1(203.4,4.85) v1(203.4,3.58) v1(203.4,2.31) v1(203.4,1.04) v1(203.4,-0.23) v1(203.4,-1.5) v1(203.4,-2.77) v1(203.4,-4.04) v1(203.4,-5.31) v1(203.44,144.99) v1(203.5,47.55) v1(203.5,45.72) v1(203.5,43.89) v1(203.5,42.06) v1(203.45,21.12) v1(203.47,-33.64) v1(203.53,33.14) v1(203.66,56.54) v1(203.67,39.21) v1(203.66,30.64) v1(203.91,75.36) v1(203.91,28.33) v1(203.91,17.69) v1(203.87,-9.35) v1(204,37.68) v1(203.99,26.88) v1(203.94,25.69) v1(203.96,-11.18) v1(204.06,72.49) v1(204.11,71.27) v1(204.09,54.28) v1(204.05,19.17) v1(204.14,51.59) v1(204.18,40.01) v1(204.19,32.48) v1(204.18,23.36) v1(204.21,-6.18) v1(204.3,12.1) v1(204.25,8.08) v1(204.25,6.81) v1(204.25,5.54) v1(204.25,4.27) v1(204.25,3) v1(204.25,1.73) v1(204.25,0.46) v1(204.25,-0.81) v1(204.25,-2.08) v1(204.25,-3.35) v1(204.25,-4.62) v1(204.34,22.02) v1(204.42,15.39) v1(204.44,117.63) v1(204.44,115.8) v1(204.44,112.14) v1(204.44,110.31) v1(204.44,106.65) v1(204.44,104.83) v1(204.44,103) v1(204.44,101.17) v1(204.44,97.51) v1(204.44,95.68) v1(204.44,93.85) v1(204.44,90.2) v1(204.44,88.37) v1(204.44,86.54) v1(204.44,84.71) v1(204.44,82.88) v1(204.44,81.05) v1(204.44,79.22) v1(204.44,77.39) v1(204.44,68.25) v1(204.44,66.42) v1(204.44,64.59) v1(204.44,50.11) v1(204.44,48.34) v1(204.43,34.04) v1(204.48,14.24) v1(204.48,10.63) v1(204.6,55.6) v1(204.55,46.66) v1(204.55,44.83) v1(204.55,43) v1(204.56,31.54) v1(204.55,9.31) v1(204.81,29.23) v1(204.8,18.59) v1(204.77,-8.46) v1(204.83,74.39) v1(204.9,38.57) v1(204.89,27.77) v1(204.84,26.59) v1(204.93,75.56) v1(204.98,70.41) v1(204.93,53.44) v1(204.95,20.07) v1(204.98,-9.51) v1(205.09,33.38) v1(205.07,24.26) v1(205.13,71.48) v1(205.2,13) v1(205.23,116.69) v1(205.23,114.86) v1(205.23,111.2) v1(205.23,109.37) v1(205.23,105.71) v1(205.23,103.89) v1(205.23,102.06) v1(205.23,100.23) v1(205.23,96.57) v1(205.23,94.74) v1(205.23,92.91) v1(205.23,67.31) v1(205.23,65.48) v1(205.23,58.17) v1(205.23,50.85) v1(205.24,22.92) v1(205.33,47.55) v1(205.33,45.72) v1(205.33,43.89) v1(205.4,40.38) v1(205.33,34.94) v1(205.37,11.53) v1(205.38,10.27) v1(205.47,144.99) v1(205.49,54.71) v1(205.45,32.44) v1(205.44,16.46) v1(205.49,15.19) v1(205.5,-33.64) v1(205.65,129.19) v1(205.65,124.26) v1(205.65,119.34) v1(205.64,73.58) v1(205.71,30.13) v1(205.7,19.49) v1(205.64,-7.53) v1(205.79,69.55) v1(205.82,52.7) v1(205.8,39.47) v1(205.79,28.67) v1(205.74,27.48) v1(205.9,134.12) v1(205.84,74.6) v1(205.85,20.97) v1(205.88,-8.62) v1(205.99,70.61) v1(205.99,34.28) v1(205.97,25.15) v1(206.09,13.9) v1(206.06,7.64) v1(206.06,6.37) v1(206.06,5.1) v1(206.06,3.83) v1(206.06,2.56) v1(206.06,1.29) v1(206.06,0.02) v1(206.06,-1.25) v1(206.06,-2.52) v1(206.06,-3.79) v1(206.06,-5.06) v1(206.06,-6.33) v1(206.14,23.82) v1(206.27,115.8) v1(206.27,113.97) v1(206.27,110.31) v1(206.27,108.48) v1(206.27,104.83) v1(206.27,103) v1(206.27,101.17) v1(206.27,99.34) v1(206.27,95.68) v1(206.27,93.85) v1(206.27,92.02) v1(206.27,90.2) v1(206.27,88.37) v1(206.27,86.54) v1(206.27,84.71) v1(206.27,82.88) v1(206.27,81.05) v1(206.27,79.22) v1(206.27,77.39) v1(206.27,66.42) v1(206.27,57.28) v1(206.27,50.11) v1(206.27,48.34) v1(206.22,35.84) v1(206.27,12.43) v1(206.28,11.17) v1(206.38,46.66) v1(206.38,44.83) v1(206.33,41.24) v1(206.35,33.34) v1(206.43,53.77) v1(206.45,17.48) v1(206.5,16.14) v1(206.5,8.83) v1(206.61,31.03) v1(206.6,20.39) v1(206.65,73.78) v1(206.71,72.51) v1(206.65,68.68) v1(206.7,40.37) v1(206.69,29.57) v1(206.64,28.38) v1(206.81,69.75) v1(206.75,21.87) v1(206.78,-7.72) v1(206.89,35.18) v1(206.87,26.05) v1(206.99,14.79) v1(207.06,114.86) v1(207.06,113.03) v1(207.06,109.37) v1(207.06,107.54) v1(207.06,103.89) v1(207.06,102.06) v1(207.06,100.23) v1(207.06,98.4) v1(207.06,94.74) v1(207.06,92.91) v1(207.06,91.08) v1(207.06,89.26) v1(207.06,87.43) v1(207.06,85.6) v1(207.06,83.77) v1(207.06,81.94) v1(207.06,80.11) v1(207.06,78.28) v1(207.06,76.45) v1(207.06,65.48) v1(207.06,58.17) v1(207.06,56.34) v1(207.06,52.68) v1(207.06,50.85) v1(207.12,36.74) v1(207.04,24.72) v1(207.03,8.15) v1(207.03,6.88) v1(207.03,5.61) v1(207.03,4.34) v1(207.03,3.07) v1(207.03,1.8) v1(207.03,0.53) v1(207.03,-0.74) v1(207.03,-2.01) v1(207.03,-3.28) v1(207.03,-4.55) v1(207.03,-5.82) v1(207.03,-6.73) v1(207.16,47.55) v1(207.16,45.72) v1(207.17,13.33) v1(207.18,12.06) v1(207.23,42.14) v1(207.25,34.23) v1(207.4,9.73) v1(207.5,144.99) v1(207.5,31.93) v1(207.5,21.29) v1(207.51,17.09) v1(207.57,75.56) v1(207.59,30.47) v1(207.54,29.28) v1(207.57,18.64) v1(207.53,-33.64) v1(207.72,72.72) v1(207.67,68.88) v1(207.72,67.61) v1(207.63,41.23) v1(207.65,22.76) v1(207.7,8.67) v1(207.77,71.5) v1(207.78,36.07) v1(207.77,26.95) v1(207.9,53.37) v1(207.89,15.69) v1(208.02,37.63) v1(207.94,25.61) v1(208.09,116.9) v1(208.1,113.97) v1(208.1,112.14) v1(208.1,108.48) v1(208.1,106.65) v1(208.1,103) v1(208.1,101.17) v1(208.1,99.34) v1(208.1,97.51) v1(208.1,93.85) v1(208.1,92.02) v1(208.1,90.2) v1(208.1,88.37) v1(208.1,86.54) v1(208.1,84.71) v1(208.1,82.88) v1(208.1,81.05) v1(208.1,79.22) v1(208.1,77.39) v1(208.1,64.59) v1(208.1,57.28) v1(208.1,55.45) v1(208.1,50.11) v1(208.1,48.34) v1(208.07,14.22) v1(208.08,12.96) v1(208.2,46.66) v1(208.13,43.04) v1(208.15,35.13) v1(208.3,10.62) v1(208.4,32.83) v1(208.4,22.18) v1(208.48,74.6) v1(208.48,31.37) v1(208.43,30.18) v1(208.52,18.04) v1(208.58,75.76) v1(208.53,42.13) v1(208.54,23.66) v1(208.53,19.61) v1(208.6,9.56) v1(208.64,70.63) v1(208.68,36.97) v1(208.67,27.85) v1(208.79,71.7) v1(208.74,67.82) v1(208.79,16.59) v1(208.89,113.03) v1(208.89,111.2) v1(208.89,107.54) v1(208.89,105.71) v1(208.89,102.06) v1(208.89,100.23) v1(208.89,98.4) v1(208.89,96.57) v1(208.89,66.45) v1(208.89,63.65) v1(208.89,58.17) v1(208.89,56.34) v1(208.89,52.68) v1(208.89,50.85) v1(208.92,38.53) v1(208.83,26.51) v1(208.99,47.55) v1(208.97,15.12) v1(208.98,13.86) v1(209.03,43.93) v1(209.05,36.03) v1(209.2,11.52) v1(209.16,7.27) v1(209.16,-2.89) v1(209.3,73.78) v1(209.3,33.72) v1(209.29,23.08) v1(209.38,32.26) v1(209.33,31.08) v1(209.5,74.8) v1(209.45,69.77) v1(209.43,43.03) v1(209.44,24.56) v1(209.45,20.47) v1(209.5,10.46) v1(209.53,144.99) v1(209.58,37.87) v1(209.56,28.75) v1(209.53,19) v1(209.53,2.12) v1(209.53,-8.04) v1(209.53,-18.2) v1(209.57,-33.64) v1(209.71,138.04) v1(209.65,70.84) v1(209.69,17.49) v1(209.73,53.37) v1(209.82,39.43) v1(209.73,27.41) v1(209.91,66.65) v1(209.86,16.02) v1(209.87,14.76) v1(209.93,112.14) v1(209.93,110.31) v1(209.93,106.65) v1(209.93,104.83) v1(209.93,101.17) v1(209.93,99.34) v1(209.93,97.51) v1(209.93,95.68) v1(209.93,93.85) v1(209.93,92.02) v1(209.93,90.2) v1(209.93,88.37) v1(209.93,86.54) v1(209.93,84.71) v1(209.93,82.88) v1(209.93,81.05) v1(209.93,79.22) v1(209.93,77.39) v1(209.93,62.76) v1(209.93,60.93) v1(209.93,59.11) v1(209.93,57.28) v1(209.93,55.45) v1(209.93,50.11) v1(209.93,48.34) v1(209.93,44.83) v1(209.94,36.93) v1(210.1,12.42) v1(210.16,65.18) v1(210.2,34.62) v1(210.19,23.98) v1(210.21,21.23) v1(210.31,73.99) v1(210.31,68.91) v1(210.28,33.16) v1(210.23,31.97) v1(210.36,72.72) v1(210.33,43.92) v1(210.34,25.46) v1(210.39,11.36) v1(210.46,69.97) v1(210.48,38.77) v1(210.46,29.64) v1(210.52,114.46) v1(210.54,19.95) v1(210.58,18.39) v1(210.72,111.2) v1(210.72,109.37) v1(210.72,105.71) v1(210.72,103.89) v1(210.72,100.23) v1(210.72,98.4) v1(210.72,96.57) v1(210.72,94.74) v1(210.72,92.91) v1(210.72,91.08) v1(210.72,89.26) v1(210.72,87.43) v1(210.72,85.6) v1(210.72,83.77) v1(210.72,81.94) v1(210.72,80.11) v1(210.72,78.28) v1(210.72,76.45) v1(210.72,61.82) v1(210.72,59.99) v1(210.72,58.17) v1(210.72,56.34) v1(210.72,52.68) v1(210.72,50.85) v1(210.71,40.33) v1(210.63,28.31) v1(210.76,16.92) v1(210.77,15.66) v1(210.83,45.72) v1(210.84,37.83) v1(210.95,47.62) v1(210.99,13.32) v1(211.1,35.52) v1(211.09,24.88) v1(211.18,65.38) v1(211.18,34.06) v1(211.13,32.87) v1(211.23,75.77) v1(211.22,44.82) v1(211.24,26.36) v1(211.28,22.25) v1(211.29,12.26) v1(211.38,72.92) v1(211.33,69.11) v1(211.38,67.84) v1(211.37,39.67) v1(211.36,30.54) v1(211.43,71.7) v1(211.43,63.91) v1(211.48,19.28) v1(211.56,144.99) v1(211.56,53.37) v1(211.61,41.23) v1(211.53,29.21) v1(211.55,20.9) v1(211.6,-33.64) v1(211.69,131.24) v1(211.69,129.97) v1(211.69,128.7) v1(211.69,127.43) v1(211.69,126.16) v1(211.69,124.89) v1(211.69,123.62) v1(211.69,122.35) v1(211.69,121.08) v1(211.69,119.81) v1(211.69,118.54) v1(211.66,17.82) v1(211.67,16.56) v1(211.76,110.31) v1(211.76,108.48) v1(211.76,104.83) v1(211.76,103) v1(211.76,99.34) v1(211.76,97.51) v1(211.76,95.68) v1(211.76,93.85) v1(211.76,92.02) v1(211.76,90.2) v1(211.76,88.37) v1(211.76,86.54) v1(211.76,84.71) v1(211.76,82.88) v1(211.76,81.05) v1(211.76,79.22) v1(211.76,77.39) v1(211.76,60.93) v1(211.76,59.11) v1(211.76,57.28) v1(211.76,55.45) v1(211.76,50.11) v1(211.76,48.34) v1(211.74,38.72) v1(211.89,14.22) v1(211.99,36.42) v1(211.99,25.78) v1(212.1,45.79) v1(212.08,34.96) v1(212.03,33.77) v1(212.07,7.2) v1(212.07,-2.96) v1(212.07,-13.12) v1(212.14,74.8) v1(212.14,27.25) v1(212.19,13.16) v1(212.24,75.97) v1(212.29,70.84) v1(212.27,40.57) v1(212.26,31.44) v1(212.24,23.16) v1(212.39,68.04) v1(212.45,71.9) v1(212.45,64.11) v1(212.51,42.12) v1(212.43,30.1) v1(212.43,19.99) v1(212.55,113.03) v1(212.55,103.89) v1(212.55,102.06) v1(212.55,98.4) v1(212.55,96.57) v1(212.55,94.74) v1(212.55,92.91) v1(212.55,91.08) v1(212.55,89.26) v1(212.55,87.43) v1(212.55,85.6) v1(212.55,83.77) v1(212.55,81.94) v1(212.55,80.11) v1(212.55,78.28) v1(212.55,66.67) v1(212.55,59.99) v1(212.55,58.17) v1(212.55,56.34) v1(212.55,52.68) v1(212.55,50.85) v1(212.56,21.85) v1(212.56,18.71) v1(212.57,17.45) v1(212.65,62.69) v1(212.64,39.62) v1(212.78,47.62) v1(212.79,15.11) v1(212.9,111.84) v1(212.9,110.57) v1(212.9,109.3) v1(212.9,108.03) v1(212.89,37.32) v1(212.89,26.67) v1(212.96,131.24) v1(212.96,129.97) v1(212.96,128.7) v1(212.96,127.43) v1(212.96,126.16) v1(212.96,124.89) v1(212.96,123.62) v1(212.96,122.35) v1(212.96,121.08) v1(212.96,119.81) v1(212.96,118.54) v1(212.95,73.99) v1(212.97,35.86) v1(212.93,34.67) v1(213.11,69.97) v1(213.03,28.15) v1(213.09,14.05) v1(213.16,75) v1(213.17,41.46) v1(213.16,32.34) v1(213.31,71.04) v1(213.31,24.38) v1(213.39,53.37) v1(213.37,45.79) v1(213.39,45.01) v1(213.41,43.02) v1(213.32,31) v1(213.33,20.89) v1(213.46,19.61) v1(213.47,18.35) v1(213.6,144.99) v1(213.56,66.87) v1(213.59,59.11) v1(213.59,57.28) v1(213.59,55.45) v1(213.59,50.11) v1(213.56,48.31) v1(213.54,40.52) v1(213.57,22.8) v1(213.66,62.89) v1(213.69,16.01) v1(213.63,-33.64) v1(213.82,65.4) v1(213.79,38.21) v1(213.78,27.57) v1(213.87,61.47) v1(213.87,36.75) v1(213.82,35.57) v1(213.97,74.19) v1(214.02,72.92) v1(213.97,69.11) v1(213.93,29.05) v1(213.99,14.95) v1(214.07,42.36) v1(214.06,33.24) v1(214.17,111.84) v1(214.17,110.57) v1(214.17,109.3) v1(214.17,108.03) v1(214.12,70.18) v1(214.23,131.24) v1(214.23,129.97) v1(214.23,128.7) v1(214.23,127.43) v1(214.23,126.16) v1(214.23,124.89) v1(214.23,123.62) v1(214.23,122.35) v1(214.23,121.08) v1(214.23,119.81) v1(214.23,118.54) v1(214.27,100.03) v1(214.22,31.9) v1(214.22,21.79) v1(214.38,102.16) v1(214.38,97.2) v1(214.38,95.37) v1(214.38,93.54) v1(214.38,91.72) v1(214.38,89.89) v1(214.38,88.06) v1(214.38,86.23) v1(214.38,84.4) v1(214.38,82.57) v1(214.38,80.74) v1(214.38,78.91) v1(214.38,77.09) v1(214.38,58.17) v1(214.38,56.34) v1(214.38,52.68) v1(214.38,50.85) v1(214.36,19.25) v1(214.43,41.42) v1(214.6,47.62) v1(214.58,23.75) v1(214.54,20.65) v1(214.59,16.91) v1(214.61,2.12) v1(214.64,45.79) v1(214.66,45.05) v1(214.66,43.24) v1(214.69,39.11) v1(214.72,36.46) v1(214.68,28.47) v1(214.63,25.55) v1(214.64,10.96) v1(214.77,37.65) v1(214.76,-8.29) v1(214.88,76.05) v1(214.83,65.6) v1(214.88,61.67) v1(214.83,29.95) v1(214.88,15.85) v1(214.99,69.31) v1(214.95,34.13) v1(214.97,-18.26) v1(215.04,73.12) v1(215.09,71.9) v1(215.04,68.04) v1(215.09,64.13) v1(215.12,32.8) v1(215.17,98.09) v1(215.17,96.26) v1(215.17,94.43) v1(215.17,92.6) v1(215.17,90.78) v1(215.17,88.95) v1(215.17,87.12) v1(215.17,85.29) v1(215.17,83.46) v1(215.17,81.63) v1(215.17,79.8) v1(215.17,77.97) v1(215.14,60.2) v1(215.21,53.37) v1(215.12,22.69) v1(215.26,20.15) v1(215.39,101.14) v1(215.42,57.28) v1(215.42,55.45) v1(215.42,50.11) v1(215.39,48.31) v1(215.4,42.24) v1(215.44,111.84) v1(215.44,110.57) v1(215.44,109.3) v1(215.44,108.03) v1(215.44,21.55) v1(215.48,17.81) v1(215.6,99.72) v1(215.59,40.01) v1(215.62,37.36) v1(215.58,29.37) v1(215.59,24.7) v1(215.63,144.99) v1(215.68,75.25) v1(215.67,38.55) v1(215.66,-33.64) v1(215.73,30.85) v1(215.78,16.75) v1(215.91,45.79) v1(215.85,35.03) v1(215.85,26.82) v1(215.95,71.04) v1(215.93,45.05) v1(215.93,43.24) v1(216.02,33.7) v1(216.02,23.58) v1(216.1,72.11) v1(216.05,68.25) v1(216.1,64.33) v1(216.21,97.2) v1(216.21,95.37) v1(216.21,93.54) v1(216.21,91.72) v1(216.21,89.89) v1(216.21,88.06) v1(216.21,86.23) v1(216.21,84.4) v1(216.21,82.57) v1(216.21,80.74) v1(216.21,78.91) v1(216.21,77.09) v1(216.2,66.87) v1(216.15,60.4) v1(216.2,56.34) v1(216.2,52.68) v1(216.2,50.85) v1(216.16,21.05) v1(216.31,62.91) v1(216.41,58.93) v1(216.34,22.45) v1(216.38,18.71) v1(216.43,47.62) v1(216.52,38.26) v1(216.48,30.27) v1(216.59,74.29) v1(216.57,39.45) v1(216.6,25.65) v1(216.71,111.84) v1(216.71,110.57) v1(216.71,109.3) v1(216.71,108.03) v1(216.7,75.46) v1(216.64,42.52) v1(216.65,40.71) v1(216.63,31.74) v1(216.68,17.65) v1(216.76,70.18) v1(216.75,35.93) v1(216.92,34.59) v1(216.92,24.48) v1(216.97,71.24) v1(217.04,53.37) v1(217.06,21.94) v1(217.22,67.08) v1(217.22,48.31) v1(217.18,45.79) v1(217.2,45.05) v1(217.2,43.24) v1(217.17,28.09) v1(217.18,16.04) v1(217.18,5.88) v1(217.25,55.45) v1(217.25,50.11) v1(217.23,23.35) v1(217.28,19.6) v1(217.41,73.48) v1(217.32,63.12) v1(217.41,39.16) v1(217.38,31.16) v1(217.47,65.6) v1(217.42,59.13) v1(217.46,40.35) v1(217.61,74.49) v1(217.53,61.69) v1(217.58,57.81) v1(217.52,32.64) v1(217.61,26.6) v1(217.58,18.54) v1(217.66,144.99) v1(217.63,69.31) v1(217.65,36.83) v1(217.69,-33.64) v1(217.78,70.38) v1(217.81,35.49) v1(217.82,25.38) v1(217.91,42.52) v1(217.92,40.71) v1(217.98,111.84) v1(217.98,110.57) v1(217.98,109.3) v1(217.98,108.03) v1(217.96,22.84) v1(218.03,52.68) v1(218.03,50.85) v1(218.13,24.24) v1(218.18,20.5) v1(218.26,47.62) v1(218.27,32.06) v1(218.29,29.21) v1(218.39,58.42) v1(218.42,73.68) v1(218.47,72.41) v1(218.49,65.81) v1(218.45,45.79) v1(218.47,45.05) v1(218.47,43.24) v1(218.47,39.86) v1(218.42,33.54) v1(218.48,19.44) v1(218.54,61.9) v1(218.55,37.73) v1(218.62,27.55) v1(218.64,69.52) v1(218.69,68.25) v1(218.71,36.39) v1(218.71,26.28) v1(218.74,64.33) v1(218.8,60.42) v1(218.9,57.86) v1(218.87,53.37) v1(218.85,23.74) v1(219.07,55.45) v1(219.07,50.11) v1(219.05,48.31) v1(219.03,25.14) v1(219.08,21.4) v1(219.25,111.84) v1(219.25,110.57) v1(219.25,109.3) v1(219.25,108.03) v1(219.69,144.99) v1(219.75,24.64) v1(219.72,10.96) v1(219.73,-33.64) v1(219.87,138.04) v1(219.97,22.3) v1(220.06,-16.16) v1(220.52,111.84) v1(220.52,110.57) v1(220.52,109.3) v1(220.52,108.03) v1(220.87,23.2) v1(221.17,22.14) v1(221.72,144.99) v1(221.79,111.84) v1(221.79,110.57) v1(221.79,109.3) v1(221.79,108.03) v1(221.77,24.09) v1(221.76,-33.64) v1(222.07,23.03) v1(222.26,16.04) v1(222.53,5.87) v1(222.97,23.93) v1(223.06,111.84) v1(223.06,110.57) v1(223.06,109.3) v1(223.06,108.03) v1(223.76,144.99) v1(223.79,-33.64) v1(224.95,138.04) v1(225.79,144.99) v1(225.82,-33.64) v1(225.96,9.23) v1(227.82,144.99) v1(227.85,-33.64) v1(229.44,-4.77) v1(229.44,-14.93) v1(229.52,1.07) v1(229.85,144.99) v1(229.89,-33.64) v1(230.03,138.04) v1(231.14,-8.6) v1(231.88,144.99) v1(231.92,-33.64) v1(231.98,-9.85) v1(233.92,144.99) v1(233.83,-8.6) v1(233.95,-33.64) v1(234.51,90.59) v1(234.52,-4.77) v1(234.52,-14.93) v1(235.95,144.99) v1(235.98,-33.64) v1(237.01,5.26) v1(237.05,85.51) v1(237.06,8.95) v1(237.06,-9.85) v1(237.98,144.99) v1(238.01,-33.64) v1(239.59,90.59) v1(239.59,80.43) v1(240.01,144.99) v1(239.96,-22.04) v1(240.05,-33.64) v1(242.04,144.99) v1(242.08,-33.64) v1(242.13,85.51) v1(242.22,-23.49) v1(244.08,144.99) v1(244.05,69.55) v1(244.05,59.39) v1(244.05,49.23) v1(244.05,39.07) v1(244.05,28.91) v1(244.05,18.75) v1(244.05,8.59) v1(244.11,-33.64) v1(244.67,90.59) v1(244.67,80.43) v1(245.32,-25.52) v1(246.11,144.99) v1(246.14,-33.64) v1(246.39,97.46) v1(246.59,94.95) v1(246.59,84.79) v1(246.59,74.63) v1(246.59,64.47) v1(246.59,54.31) v1(246.59,44.15) v1(246.59,33.99) v1(246.59,23.83) v1(246.59,13.67) v1(246.59,3.51) v1(246.59,-6.65) v1(246.59,-16.81) v1(246.59,-26.97) v1(248.14,144.99) v1(248.17,-33.64) v1(248.55,86.71) v1(248.93,102.54) v1(249.13,89.87) v1(249.13,79.71) v1(249.13,69.55) v1(249.13,59.39) v1(249.13,49.23) v1(249.13,39.07) v1(249.13,28.91) v1(249.13,18.75) v1(249.13,8.59) v1(249.13,-11.73) v1(249.13,-21.89) v1(249.13,-32.05) v1(250.17,144.99) v1(250.21,-33.64) v1(250.97,-25.4) v1(251.4,115.45) v1(251.4,114.18) v1(251.4,112.91) v1(251.4,111.64) v1(251.4,110.37) v1(251.4,109.1) v1(251.4,107.83) v1(251.4,106.56) v1(251.47,97.46) v1(251.67,94.95) v1(251.67,84.79) v1(251.67,74.63) v1(251.67,64.47) v1(251.67,54.31) v1(251.67,44.15) v1(251.67,33.99) v1(251.67,23.83) v1(251.67,13.67) v1(251.67,3.51) v1(251.67,-6.65) v1(251.67,-16.81) v1(251.7,-21.82) v1(252.2,144.99) v1(252.24,-33.64) v1(252.67,115.45) v1(252.67,114.18) v1(252.67,112.91) v1(252.67,111.64) v1(252.67,110.37) v1(252.67,109.1) v1(252.67,107.83) v1(252.67,106.56) v1(254.01,112.7) v1(254.01,102.54) v1(253.96,49.28) v1(253.96,39.12) v1(253.96,28.96) v1(253.96,18.8) v1(253.96,8.64) v1(253.96,-1.52) v1(254.04,59.99) v1(254.1,-6.63) v1(254.21,89.87) v1(254.21,79.71) v1(254.21,69.55) v1(254.21,-11.73) v1(254.21,-32.05) v1(254.24,144.99) v1(254.27,-33.64) v1(254.39,-21.82) v1(255.82,59.15) v1(255.84,54.21) v1(255.84,44.05) v1(255.84,33.89) v1(255.84,23.73) v1(255.84,13.57) v1(255.84,3.41) v1(256.09,-25.41) v1(256.27,144.99) v1(256.3,-33.64) v1(256.55,107.62) v1(256.55,97.46) v1(256.75,94.95) v1(256.75,84.79) v1(256.75,74.63) v1(256.75,-6.65) v1(256.75,-16.81) v1(256.75,-26.97) v1(256.95,126.85) v1(256.95,125.58) v1(256.95,124.31) v1(256.95,123.04) v1(256.95,121.77) v1(256.95,120.5) v1(257.61,-20.25) v1(257.96,54.03) v1(257.97,49.13) v1(257.97,38.97) v1(257.97,28.81) v1(257.97,18.65) v1(257.97,8.49) v1(257.97,-1.67) v1(258.22,126.85) v1(258.22,125.58) v1(258.22,124.31) v1(258.22,123.04) v1(258.22,121.77) v1(258.22,120.5) v1(258.3,144.99) v1(258.28,64.47) v1(258.33,-33.64) v1(259.09,112.7) v1(259.09,102.54) v1(259.29,89.87) v1(259.29,79.71) v1(259.29,69.55) v1(259.29,-32.05) v1(259.91,59.28) v1(259.95,53.04) v1(259.95,42.88) v1(259.95,32.72) v1(259.95,22.56) v1(259.95,12.4) v1(259.95,2.24) v1(260.3,-20.25) v1(260.33,144.99) v1(260.37,-33.64) v1(261.63,107.62) v1(261.63,97.46) v1(261.83,94.95) v1(261.83,84.79) v1(261.83,74.63) v1(261.83,64.47) v1(261.83,54.31) v1(261.83,44.15) v1(261.83,33.99) v1(261.83,23.83) v1(261.83,13.67) v1(261.83,3.51) v1(261.83,-6.65) v1(261.83,-16.81) v1(261.83,-26.97) v1(262.36,144.99) v1(262.4,-33.64) v1(263.76,69.7) v1(263.91,-25.4) v1(264.07,56.39) v1(264.04,-4.31) v1(264.17,133.02) v1(264.17,122.86) v1(264.17,112.7) v1(264.17,102.54) v1(264.22,59.39) v1(264.4,144.99) v1(264.37,89.87) v1(264.37,79.71) v1(264.37,49.23) v1(264.37,39.07) v1(264.37,28.91) v1(264.37,18.75) v1(264.37,8.59) v1(264.37,-1.57) v1(264.37,-11.73) v1(264.37,-21.89) v1(264.37,-32.05) v1(264.52,63.96) v1(264.5,-20.27) v1(264.43,-33.64) v1(264.75,-8.03) v1(266.43,144.99) v1(266.46,-33.64) v1(266.71,117.78) v1(266.71,107.62) v1(266.71,97.46) v1(266.91,94.95) v1(266.91,84.79) v1(266.91,74.63) v1(266.91,54.31) v1(266.91,44.15) v1(266.91,33.99) v1(266.91,23.83) v1(266.91,13.67) v1(266.91,3.51) v1(266.91,-6.65) v1(266.91,-16.81) v1(266.91,-26.97) v1(267.2,-20.27) v1(268.46,144.99) v1(268.49,-33.64) v1(268.9,-23.17) v1(269.25,133.02) v1(269.25,122.86) v1(269.25,102.54) v1(269.34,64.67) v1(269.45,89.87) v1(269.45,79.71) v1(269.45,59.39) v1(269.45,49.23) v1(269.45,39.07) v1(269.45,28.91) v1(269.45,18.75) v1(269.45,8.59) v1(269.45,-11.73) v1(269.45,-21.89) v1(269.45,-32.05) v1(270.1,69.6) v1(270.49,144.99) v1(270.53,-33.64) v1(271.79,127.94) v1(271.79,97.46) v1(271.75,77.86) v1(271.99,94.95) v1(271.99,84.79) v1(271.99,74.63) v1(271.99,64.47) v1(271.99,54.31) v1(271.99,44.15) v1(271.99,33.99) v1(271.99,23.83) v1(271.99,13.67) v1(271.99,3.51) v1(271.99,-6.65) v1(271.99,-16.81) v1(272.52,144.99) v1(272.56,-33.64) v1(274.33,133.02) v1(274.33,122.86) v1(274.33,112.7) v1(274.33,102.54) v1(274.56,144.99) v1(274.53,89.87) v1(274.53,69.55) v1(274.53,59.39) v1(274.53,49.23) v1(274.53,39.07) v1(274.53,28.91) v1(274.53,18.75) v1(274.53,8.59) v1(274.53,-1.57) v1(274.53,-11.73) v1(274.53,-21.89) v1(274.53,-32.05) v1(274.59,-33.64) v1(275.13,81.29) v1(276.11,75.65) v1(276.59,144.99) v1(276.62,-33.64) v1(276.87,127.94) v1(277.07,84.79) v1(277.07,64.47) v1(277.07,54.31) v1(277.07,44.15) v1(277.07,33.99) v1(277.07,23.83) v1(277.07,13.67) v1(277.07,3.51) v1(277.07,-6.65) v1(277.07,-16.81) v1(278.09,-21.47) v1(278.23,73.51) v1(278.62,144.99) v1(278.65,-33.64) v1(279.41,133.02) v1(279.41,122.86) v1(279.41,112.7) v1(279.61,69.55) v1(279.61,59.39) v1(279.61,49.23) v1(279.61,39.07) v1(279.61,28.91) v1(279.61,18.75) v1(279.61,8.59) v1(279.61,-1.57) v1(279.61,-11.73) v1(279.61,-21.89) v1(279.61,-32.05) v1(280.65,144.99) v1(280.69,-33.64) v1(281.95,127.94) v1(281.95,117.78) v1(282.15,74.63) v1(282.15,64.47) v1(282.15,54.31) v1(282.15,44.15) v1(282.15,33.99) v1(282.15,23.83) v1(282.15,13.67) v1(282.15,3.51) v1(282.15,-6.65) v1(282.15,-16.81) v1(282.68,144.99) v1(282.72,-33.64) v1(284.49,133.02) v1(284.49,122.86) v1(284.49,112.7) v1(284.72,144.99) v1(284.69,69.55) v1(284.69,59.39) v1(284.69,49.23) v1(284.69,39.07) v1(284.69,28.91) v1(284.69,18.75) v1(284.69,8.59) v1(284.69,-11.73) v1(284.69,-32.05) v1(284.75,-33.64) v1(286.75,144.99) v1(286.78,-33.64) v1(287.03,127.94) v1(287.03,117.78) v1(287.03,107.62) v1(287.03,97.46) v1(287.23,64.47) v1(287.23,54.31) v1(287.23,44.15) v1(287.23,33.99) v1(287.23,23.83) v1(287.23,13.67) v1(287.23,3.51) v1(287.23,-6.65) v1(287.23,-16.81) v1(287.23,-26.97) v1(287.38,90.68) v1(288.78,144.99) v1(288.81,-33.64) v1(288.93,88.33) v1(289.57,133.02) v1(289.57,122.86) v1(289.57,112.7) v1(289.57,102.54) v1(289.67,90.39) v1(289.81,92.62) v1(289.77,69.55) v1(289.77,59.39) v1(289.77,49.23) v1(289.77,39.07) v1(289.77,28.91) v1(289.77,18.75) v1(289.77,8.59) v1(289.77,-11.73) v1(289.77,-32.05) v1(290.47,129.79) v1(290.47,128.52) v1(290.47,127.25) v1(290.81,144.99) v1(290.85,-33.64) v1(291.74,129.79) v1(291.74,128.52) v1(291.74,127.25) v1(292.84,144.99) v1(292.88,-33.64) v1(293.01,129.79) v1(293.01,128.52) v1(293.01,127.25) v1(294.28,129.79) v1(294.28,128.52) v1(294.28,127.25) v1(294.58,98.04) v1(294.64,133.05) v1(294.75,90.39) v1(294.88,144.99) v1(294.89,92.62) v1(294.85,69.55) v1(294.85,59.39) v1(294.85,49.23) v1(294.85,39.07) v1(294.85,28.91) v1(294.85,18.75) v1(294.85,8.59) v1(294.85,-1.57) v1(294.85,-11.73) v1(294.85,-32.05) v1(294.91,-33.64) v1(294.93,88.38) v1(295.55,129.79) v1(295.55,128.52) v1(295.55,127.25) v1(296.1,-24.99) v1(296.6,85.12) v1(296.82,129.79) v1(296.82,128.52) v1(296.82,127.25) v1(296.91,144.99) v1(296.94,-33.64) v1(297.39,64.47) v1(297.39,54.31) v1(297.39,44.15) v1(297.39,33.99) v1(297.39,23.83) v1(297.39,13.67) v1(297.39,3.51) v1(297.39,-6.65) v1(297.39,-16.81) v1(297.39,-26.97) v1(298.09,129.79) v1(298.09,128.52) v1(298.09,127.25) v1(298.94,144.99) v1(299.02,109.13) v1(298.97,-33.64) v1(299.36,129.79) v1(299.36,128.52) v1(299.36,127.25) v1(299.72,133.05) v1(299.83,90.39) v1(299.97,92.62) v1(300.01,88.38) v1(299.93,69.55) v1(299.93,59.39) v1(299.93,49.23) v1(299.93,39.07) v1(299.93,28.91) v1(299.93,18.75) v1(299.93,8.59) v1(299.93,-1.57) v1(299.93,-11.73) v1(299.93,-32.05) v1(300.63,129.79) v1(300.63,128.52) v1(300.63,127.25) v1(300.97,144.99) v1(301.01,-33.64) v1(301.15,75.23) v1(301.9,129.79) v1(301.9,128.52) v1(301.9,127.25) v1(302.47,64.47) v1(302.47,54.31) v1(302.47,44.15) v1(302.47,33.99) v1(302.47,23.83) v1(302.47,13.67) v1(302.47,3.51) v1(302.47,-6.65) v1(302.47,-16.81) v1(303,144.99) v1(303.04,-33.64) v1(303.17,129.79) v1(303.17,128.52) v1(303.17,127.25) v1(303.58,80.61) v1(303.82,77.87) v1(304.09,109.84) v1(304.44,129.79) v1(304.44,128.52) v1(304.44,127.25) v1(304.8,133.05) v1(304.91,90.39) v1(305.01,69.55) v1(305.01,59.39) v1(305.01,49.23) v1(305.01,39.07) v1(305.01,28.91) v1(305.01,18.75) v1(305.01,8.59) v1(305.01,-1.57) v1(305.01,-11.73) v1(305.01,-32.05) v1(305.04,144.99) v1(305.05,92.62) v1(305.09,88.38) v1(305.07,-33.64) v1(305.28,-25) v1(305.36,100.89) v1(307.07,144.99) v1(307.1,-33.64) v1(307.34,127.97) v1(307.55,64.47) v1(307.55,54.31) v1(307.55,44.15) v1(307.55,33.99) v1(307.55,23.83) v1(307.55,13.67) v1(307.55,3.51) v1(307.55,-6.65) v1(307.55,-16.81) v1(307.55,-26.97) v1(308.1,88.34) v1(308.54,119.15) v1(308.54,117.95) v1(308.54,116.75) v1(309.1,144.99) v1(309.13,-33.64) v1(309.55,86.97) v1(309.74,119.15) v1(309.74,117.95) v1(309.74,116.75) v1(309.88,133.05) v1(310.09,-32.05) v1(310.13,92.62) v1(310.13,90.68) v1(310.58,81.04) v1(310.94,119.15) v1(310.94,117.95) v1(310.94,116.75) v1(311.13,144.99) v1(311.15,88.19) v1(311.17,-33.64) v1(312.42,127.97) v1(312.58,88.2) v1(312.63,94.95) v1(312.63,64.47) v1(312.63,54.31) v1(312.63,44.15) v1(312.63,33.99) v1(312.63,23.83) v1(312.63,13.67) v1(312.63,3.51) v1(312.63,-6.65) v1(312.63,-16.81) v1(312.63,-26.97) v1(313.16,144.99) v1(313.2,-33.64) v1(314.92,-19.98) v1(314.96,133.05) v1(315.2,144.99) v1(315.17,89.87) v1(315.17,59.39) v1(315.17,49.23) v1(315.17,39.07) v1(315.17,28.91) v1(315.17,18.75) v1(315.17,8.59) v1(315.17,-1.57) v1(315.17,-11.73) v1(315.17,-32.05) v1(315.23,-33.64) v1(315.71,-23.64) v1(316.7,126.66) v1(316.7,125.39) v1(316.7,124.12) v1(316.88,7.62) v1(316.88,6.62) v1(316.88,5.62) v1(317.23,144.99) v1(317.26,-33.64) v1(317.5,127.97) v1(317.47,-18.07) v1(317.71,54.31) v1(317.71,44.15) v1(317.71,33.99) v1(317.71,23.83) v1(317.71,13.67) v1(317.71,3.51) v1(317.71,-6.65) v1(317.71,-16.81) v1(317.71,-26.97) v1(317.88,7.62) v1(317.88,6.62) v1(317.88,5.62) v1(317.97,126.66) v1(317.97,125.39) v1(317.97,124.12) v1(319.26,144.99) v1(319.24,126.66) v1(319.24,125.39) v1(319.24,124.12) v1(319.29,-33.64) v1(320.04,133.05) v1(320.25,18.75) v1(320.25,8.59) v1(320.25,-1.57) v1(320.25,-11.73) v1(320.25,-21.89) v1(320.25,-32.05) v1(320.51,126.66) v1(320.51,125.39) v1(320.51,124.12) v1(321.29,144.99) v1(321.33,-33.64) v1(321.78,126.66) v1(321.78,125.39) v1(321.78,124.12) v1(322.58,127.97) v1(323.05,126.66) v1(323.05,125.39) v1(323.05,124.12) v1(323.32,144.99) v1(323.36,-33.64) v1(324.32,126.66) v1(324.32,125.39) v1(324.32,124.12) v1(325.12,133.05) v1(325.36,144.99) v1(325.39,-33.64) v1(325.59,126.66) v1(325.59,125.39) v1(325.59,124.12) v1(326.86,126.66) v1(326.86,125.39) v1(326.86,124.12) v1(327.39,144.99) v1(327.42,-33.64) v1(327.66,127.97) v1(328.13,126.66) v1(328.13,125.39) v1(328.13,124.12) v1(329.42,144.99) v1(329.4,126.66) v1(329.4,125.39) v1(329.4,124.12) v1(329.45,-33.64) v1(330.2,133.05) v1(330.26,-14.98) v1(330.26,-25.14) v1(330.67,126.66) v1(330.67,125.39) v1(330.67,124.12) v1(330.68,58.02) v1(330.82,77.95) v1(331.01,43.57) v1(331.22,72.69) v1(331.14,64.83) v1(331.45,144.99) v1(331.49,-33.64) v1(331.62,82.4) v1(331.67,33.12) v1(331.62,16.92) v1(331.77,27.38) v1(331.83,23.62) v1(332.02,50.81) v1(332.08,93.62) v1(332.09,60.57) v1(332.23,103.68) v1(332.33,14.27) v1(332.58,38.51) v1(332.74,127.97) v1(332.74,117.81) v1(332.74,107.65) v1(332.8,-20.06) v1(332.84,91.14) v1(332.89,83.47) v1(332.9,51.42) v1(332.92,71.75) v1(332.95,53.96) v1(332.99,34.29) v1(333.03,55.34) v1(333.33,114.51) v1(333.36,36.85) v1(333.4,30.33) v1(333.4,22.71) v1(333.48,144.99) v1(333.45,25.96) v1(333.52,-33.64) v1(333.59,88.95) v1(333.78,44.92) v1(333.81,12.95) v1(333.99,104.28) v1(334.08,41.99) v1(334.26,40.35) v1(334.26,24.18) v1(334.37,21.54) v1(334.64,99.17) v1(334.78,51.96) v1(335.28,133.05) v1(335.28,122.89) v1(335.28,112.73) v1(335.28,102.57) v1(335.32,45.55) v1(335.34,-14.98) v1(335.34,-25.14) v1(335.52,144.99) v1(335.43,11.38) v1(335.55,-33.64) v1(335.72,50.72) v1(335.89,38.63) v1(335.97,40.54) v1(336.02,36.75) v1(335.94,33.48) v1(335.94,30.99) v1(335.94,29.58) v1(335.95,24.04) v1(336.11,47.5) v1(336.09,20.52) v1(336.28,43.24) v1(336.91,9.91) v1(337.55,144.99) v1(337.58,-33.64) v1(337.82,127.97) v1(337.82,117.81) v1(337.82,107.65) v1(337.76,55.35) v1(337.87,121.11) v1(337.88,-20.06) v1(338.18,37.52) v1(338.25,45.35) v1(338.28,8.23) v1(338.42,53.21) v1(338.35,0.51) v1(338.35,-0.62) v1(338.35,-3.33) v1(338.35,-4.47) v1(338.43,14.12) v1(338.66,40.54) v1(338.64,33.48) v1(338.64,29.58) v1(338.65,24.04) v1(339.51,57.83) v1(339.58,144.99) v1(339.61,-33.64) v1(339.8,52.95) v1(339.97,55.28) v1(340.06,90.79) v1(340.06,82.35) v1(340.36,133.05) v1(340.36,122.89) v1(340.36,112.73) v1(340.36,102.57) v1(340.36,6.4) v1(340.42,-14.98) v1(340.42,-25.14) v1(340.81,60.25) v1(340.82,41.94) v1(340.86,86.14) v1(340.84,71.45) v1(340.87,18.85) v1(341.2,108.35) v1(341.31,50.31) v1(341.26,10.1) v1(341.29,4.43) v1(341.46,15.32) v1(341.61,144.99) v1(341.65,-33.64) v1(341.77,100.59) v1(341.86,2.82) v1(341.86,0.92) v1(341.86,-1) v1(341.86,-2.93) v1(341.86,-4.88) v1(341.86,-6.78) v1(341.98,91.56) v1(342.17,113.46) v1(342.15,82.52) v1(342.17,58.17) v1(342.59,120.59) v1(342.64,42.37) v1(342.9,127.97) v1(342.9,117.81) v1(342.9,107.65) v1(342.89,52.96) v1(343.01,13.99) v1(342.96,-20.06) v1(343.29,37.46) v1(343.31,8.43) v1(343.64,144.99) v1(343.72,69.59) v1(343.68,-33.64) v1(344.02,77.72) v1(344.27,61.11) v1(344.43,42.97) v1(344.66,51.68) v1(344.68,45.06) v1(344.83,79.3) v1(345.34,121) v1(345.38,49.64) v1(345.33,39.24) v1(345.44,133.05) v1(345.44,112.73) v1(345.44,102.57) v1(345.5,-14.98) v1(345.5,-25.14) v1(345.68,144.99) v1(345.64,41.5) v1(345.71,-33.64) v1(346.06,55.78) v1(346.2,69.9) v1(346.52,47.76) v1(346.46,45.78) v1(346.43,37.13) v1(346.61,62.03) v1(346.99,124.99) v1(347.17,58.06) v1(347.18,55.15) v1(347.71,144.99) v1(347.78,43.59) v1(347.74,-33.64) v1(347.98,127.97) v1(347.98,117.81) v1(347.98,107.65) v1(347.94,49.23) v1(348.08,39.42) v1(348.04,-20.06) v1(348.55,123.26) v1(348.54,69.9) v1(348.74,63.2) v1(348.74,46.63) v1(349.1,71.93) v1(349.3,126.9) v1(349.56,131.09) v1(349.56,130.09) v1(349.74,144.99) v1(349.77,-33.64) v1(350.11,55.6) v1(350.24,37.26) v1(350.42,125.14) v1(350.52,112.73) v1(350.52,102.57) v1(350.58,-14.98) v1(350.58,-25.14) v1(351.38,39.42) v1(351.77,144.99) v1(351.81,-33.64) v1(352.49,77.71) v1(352.63,127.37) v1(352.65,37.26) v1(353.06,117.81) v1(353.06,107.65) v1(353.12,-20.06) v1(353.8,144.99) v1(353.84,-33.64) v1(353.92,39.42) v1(354.59,123.5) v1(355.19,37.26) v1(355.4,55.05) v1(355.4,54.05) v1(355.4,53.05) v1(355.4,52.05) v1(355.4,51.05) v1(355.4,50.05) v1(355.4,49.05) v1(355.6,112.73) v1(355.6,102.57) v1(355.66,-14.98) v1(355.66,-25.14) v1(355.84,144.99) v1(355.9,35.02) v1(355.87,-33.64) v1(357.23,37.26) v1(357.63,70.83) v1(357.87,144.99) v1(357.92,45.36) v1(357.92,44.16) v1(357.92,42.96) v1(357.9,-33.64) v1(358.14,117.81) v1(358.14,107.65) v1(358.2,-20.06) v1(358.4,134.29) v1(358.4,49.05) v1(359,37.26) v1(359.12,45.36) v1(359.12,44.16) v1(359.12,42.96) v1(359.4,134.29) v1(359.35,123.52) v1(359.51,34.98) v1(359.9,144.99) v1(359.93,-33.64) v1(360.31,45.36) v1(360.31,44.16) v1(360.31,42.96) v1(360.68,112.73) v1(360.68,102.57) v1(361.67,39.55) v1(361.93,144.99) v1(361.92,37.01) v1(361.97,-33.64) v1(362.69,34.98) v1(362.76,77.19) v1(363.22,117.81) v1(363.22,107.65) v1(363.96,144.99) v1(364,-33.64) v1(364.59,138.23) v1(365.1,37.39) v1(365.76,112.73) v1(365.76,102.57) v1(366,144.99) v1(366.03,-33.64) v1(367.13,143.31) v1(367.61,47.78) v1(367.61,46.78) v1(367.61,45.78) v1(368.03,144.99) v1(368.06,-33.64) v1(368.3,117.81) v1(368.3,107.65) v1(368.61,47.78) v1(368.61,46.78) v1(368.61,45.78) v1(369.2,44.2) v1(369.33,41.25) v1(369.67,138.23) v1(370.06,144.99) v1(370.09,-33.64) v1(370.84,112.73) v1(370.84,102.57) v1(370.92,43.23) v1(371.48,16.74) v1(371.48,15.61) v1(371.48,14.61) v1(371.48,13.61) v1(371.48,12.61) v1(371.48,11.61) v1(371.71,49.42) v1(372.09,144.99) v1(372.21,143.31) v1(372.13,-33.64) v1(372.47,16.74) v1(372.47,15.61) v1(372.47,14.61) v1(372.47,13.61) v1(372.47,12.61) v1(372.47,11.61) v1(372.72,47.68) v1(373.38,117.81) v1(373.38,107.65) v1(374.12,144.99) v1(374.16,-33.64) v1(374.23,46.51) v1(374.47,52.2) v1(374.56,33.82) v1(374.56,32.82) v1(374.56,31.82) v1(374.56,30.82) v1(374.56,29.82) v1(374.56,28.82) v1(374.56,27.82) v1(374.56,26.82) v1(374.56,25.82) v1(374.56,24.82) v1(374.56,23.82) v1(374.56,22.82) v1(374.56,21.82) v1(374.56,20.82) v1(374.56,19.82) v1(374.56,18.82) v1(374.75,138.23) v1(374.75,49.71) v1(375.56,33.82) v1(375.56,32.82) v1(375.56,31.82) v1(375.56,30.82) v1(375.56,29.82) v1(375.56,28.82) v1(375.56,27.82) v1(375.56,26.82) v1(375.56,25.82) v1(375.56,24.82) v1(375.56,23.82) v1(375.56,22.82) v1(375.56,21.82) v1(375.56,20.82) v1(375.56,19.82) v1(375.56,18.82) v1(375.92,112.73) v1(375.92,102.57) v1(376.16,144.99) v1(376.19,-33.64) v1(376.55,-12.26) v1(377.29,143.31) v1(378.19,144.99) v1(378.22,-33.64) v1(378.46,117.81) v1(378.46,107.65) v1(379.19,64.29) v1(379.19,62.94) v1(379.83,138.23) v1(380.22,144.99) v1(380.25,-33.64) v1(380.46,65.56) v1(380.46,64.29) v1(380.46,62.94) v1(381,112.73) v1(381,102.57) v1(381,40.03) v1(381,38.76) v1(381,37.49) v1(381.51,53.11) v1(381.51,51.1) v1(381.51,49) v1(381.73,65.56) v1(381.73,64.29) v1(381.73,62.94) v1(382.25,144.99) v1(382.27,40.03) v1(382.27,38.76) v1(382.27,37.49) v1(382.29,-33.64) v1(382.37,143.31) v1(382.37,4.47) v1(382.37,3.2) v1(382.37,1.93) v1(383.54,117.81) v1(383.54,107.65) v1(383.54,40.03) v1(383.54,38.76) v1(383.54,37.49) v1(383.64,5.74) v1(383.64,4.47) v1(383.64,3.2) v1(383.64,1.93) v1(384.28,144.99) v1(384.32,-33.64) v1(384.91,138.23) v1(384.91,5.74) v1(384.91,4.47) v1(384.91,3.2) v1(384.91,1.93) v1(386.08,112.73) v1(386.08,102.57) v1(386.21,51.05) v1(386.18,4.47) v1(386.18,3.2) v1(386.32,144.99) v1(386.35,-33.64) v1(387.07,51.05) v1(387.45,143.31) v1(388.35,144.99) v1(388.38,-33.64) v1(388.62,117.81) v1(388.62,107.65) v1(389.71,36.75) v1(389.83,63.39) v1(389.83,61.75) v1(389.99,138.23) v1(390.09,0.13) v1(390.22,38.63) v1(390.38,144.99) v1(390.41,-33.64) v1(390.59,2.97) v1(391.16,112.73) v1(391.16,102.57) v1(392.41,144.99) v1(392.45,-33.64) v1(392.53,143.31) v1(392.91,38.63) v1(393.7,117.81) v1(393.7,107.65) v1(394.44,144.99) v1(394.48,-33.64) v1(395.07,138.23) v1(396.24,112.73) v1(396.24,102.57) v1(396.48,144.99) v1(396.51,-33.64) v1(397.61,143.31) v1(398.51,144.99) v1(398.54,-33.64) v1(398.78,117.81) v1(398.78,107.65) v1(400.15,138.23) v1(400.54,144.99) v1(400.57,-33.64) v1(401.32,112.73) v1(401.32,102.57) v1(402.61,-33.64) v1(403.86,117.81) v1(403.86,107.65) v1(404.64,-33.64) v1(406.64,144.99) v1(406.64,142.96) v1(406.64,140.92) v1(406.64,138.89) v1(406.64,136.86) v1(406.64,134.83) v1(406.64,132.8) v1(406.64,130.76) v1(406.64,128.73) v1(406.64,126.7) v1(406.64,124.67) v1(406.64,122.64) v1(406.64,120.6) v1(406.64,118.57) v1(406.64,116.54) v1(406.64,114.51) v1(406.64,112.48) v1(406.64,110.44) v1(406.64,108.41) v1(406.64,106.38) v1(406.64,104.35) v1(406.64,102.32) v1(406.64,100.28) v1(406.64,98.25) v1(406.64,96.22) v1(406.64,94.19) v1(406.64,92.16) v1(406.64,90.12) v1(406.64,88.09) v1(406.64,86.06) v1(406.64,84.03) v1(406.64,82) v1(406.64,79.96) v1(406.64,77.93) v1(406.64,75.9) v1(406.64,73.87) v1(406.64,53.55) v1(406.64,51.52) v1(406.64,49.48) v1(406.64,47.45) v1(406.64,45.42) v1(406.64,43.39) v1(406.64,41.36) v1(406.64,39.32) v1(406.64,37.29) v1(406.64,35.26) v1(406.64,33.23) v1(406.64,31.2) v1(406.64,29.16) v1(406.64,27.13) v1(406.64,25.1) v1(406.64,23.07) v1(406.64,21.04) v1(406.64,19) v1(406.64,16.97) v1(406.64,14.94) v1(406.64,8.84) v1(406.64,6.81) v1(406.64,4.78) v1(406.64,2.75) v1(406.64,0.72) v1(406.64,-7.41) v1(406.64,-9.44) v1(406.64,-11.48) v1(406.64,-15.54) v1(406.64,-17.57) v1(406.64,-19.6) v1(406.64,-21.64) v1(406.64,-23.67) v1(406.64,-25.7) v1(406.64,-27.73) v1(406.64,-29.76) v1(406.64,-31.8) v1(406.67,-33.64)
